VERSION 5.8 ;
BUSBITCHARS "[]" ;
DIVIDERCHAR "/" ;
UNITS
    DATABASE MICRONS 1000 ;
END UNITS

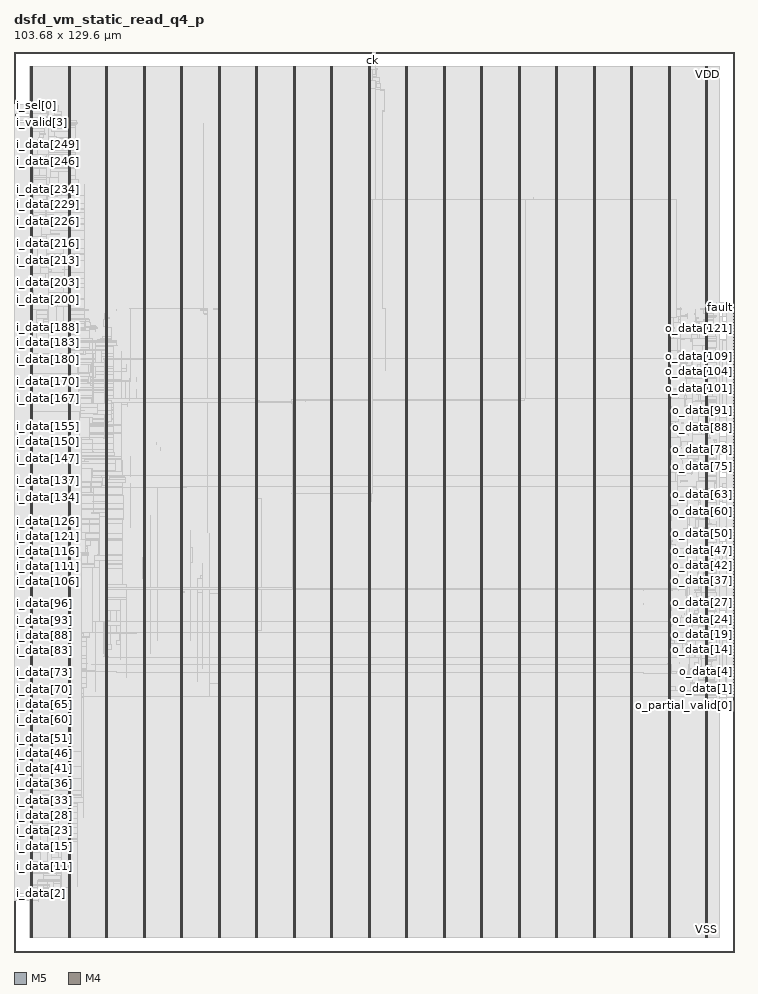
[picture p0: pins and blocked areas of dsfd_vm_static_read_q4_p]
MACRO dsfd_vm_static_read_q4_p
  FOREIGN dsfd_vm_static_read_q4_p 0 0 ;
  CLASS BLOCK ;
  SIZE 103.68 BY 129.6 ;
  PIN ck
    DIRECTION INPUT ;
    USE SIGNAL ;
    PORT
      LAYER M5 ;
        RECT  51.6 129.516 51.624 129.6 ;
    END
  END ck
  PIN fault
    DIRECTION OUTPUT ;
    USE SIGNAL ;
    PORT
      LAYER M4 ;
        RECT  103.596 92.832 103.68 92.856 ;
    END
  END fault
  PIN i_data[0]
    DIRECTION INPUT ;
    USE SIGNAL ;
    PORT
      LAYER M4 ;
        RECT  0 7.536 0.084 7.56 ;
    END
  END i_data[0]
  PIN i_data[100]
    DIRECTION INPUT ;
    USE SIGNAL ;
    PORT
      LAYER M4 ;
        RECT  0 50.736 0.084 50.76 ;
    END
  END i_data[100]
  PIN i_data[101]
    DIRECTION INPUT ;
    USE SIGNAL ;
    PORT
      LAYER M4 ;
        RECT  0 51.168 0.084 51.192 ;
    END
  END i_data[101]
  PIN i_data[102]
    DIRECTION INPUT ;
    USE SIGNAL ;
    PORT
      LAYER M4 ;
        RECT  0 51.6 0.084 51.624 ;
    END
  END i_data[102]
  PIN i_data[103]
    DIRECTION INPUT ;
    USE SIGNAL ;
    PORT
      LAYER M4 ;
        RECT  0 52.032 0.084 52.056 ;
    END
  END i_data[103]
  PIN i_data[104]
    DIRECTION INPUT ;
    USE SIGNAL ;
    PORT
      LAYER M4 ;
        RECT  0 52.464 0.084 52.488 ;
    END
  END i_data[104]
  PIN i_data[105]
    DIRECTION INPUT ;
    USE SIGNAL ;
    PORT
      LAYER M4 ;
        RECT  0 52.896 0.084 52.92 ;
    END
  END i_data[105]
  PIN i_data[106]
    DIRECTION INPUT ;
    USE SIGNAL ;
    PORT
      LAYER M4 ;
        RECT  0 53.328 0.084 53.352 ;
    END
  END i_data[106]
  PIN i_data[107]
    DIRECTION INPUT ;
    USE SIGNAL ;
    PORT
      LAYER M4 ;
        RECT  0 53.76 0.084 53.784 ;
    END
  END i_data[107]
  PIN i_data[108]
    DIRECTION INPUT ;
    USE SIGNAL ;
    PORT
      LAYER M4 ;
        RECT  0 54.192 0.084 54.216 ;
    END
  END i_data[108]
  PIN i_data[109]
    DIRECTION INPUT ;
    USE SIGNAL ;
    PORT
      LAYER M4 ;
        RECT  0 54.624 0.084 54.648 ;
    END
  END i_data[109]
  PIN i_data[10]
    DIRECTION INPUT ;
    USE SIGNAL ;
    PORT
      LAYER M4 ;
        RECT  0 11.856 0.084 11.88 ;
    END
  END i_data[10]
  PIN i_data[110]
    DIRECTION INPUT ;
    USE SIGNAL ;
    PORT
      LAYER M4 ;
        RECT  0 55.056 0.084 55.08 ;
    END
  END i_data[110]
  PIN i_data[111]
    DIRECTION INPUT ;
    USE SIGNAL ;
    PORT
      LAYER M4 ;
        RECT  0 55.488 0.084 55.512 ;
    END
  END i_data[111]
  PIN i_data[112]
    DIRECTION INPUT ;
    USE SIGNAL ;
    PORT
      LAYER M4 ;
        RECT  0 55.92 0.084 55.944 ;
    END
  END i_data[112]
  PIN i_data[113]
    DIRECTION INPUT ;
    USE SIGNAL ;
    PORT
      LAYER M4 ;
        RECT  0 56.352 0.084 56.376 ;
    END
  END i_data[113]
  PIN i_data[114]
    DIRECTION INPUT ;
    USE SIGNAL ;
    PORT
      LAYER M4 ;
        RECT  0 56.784 0.084 56.808 ;
    END
  END i_data[114]
  PIN i_data[115]
    DIRECTION INPUT ;
    USE SIGNAL ;
    PORT
      LAYER M4 ;
        RECT  0 57.216 0.084 57.24 ;
    END
  END i_data[115]
  PIN i_data[116]
    DIRECTION INPUT ;
    USE SIGNAL ;
    PORT
      LAYER M4 ;
        RECT  0 57.648 0.084 57.672 ;
    END
  END i_data[116]
  PIN i_data[117]
    DIRECTION INPUT ;
    USE SIGNAL ;
    PORT
      LAYER M4 ;
        RECT  0 58.08 0.084 58.104 ;
    END
  END i_data[117]
  PIN i_data[118]
    DIRECTION INPUT ;
    USE SIGNAL ;
    PORT
      LAYER M4 ;
        RECT  0 58.512 0.084 58.536 ;
    END
  END i_data[118]
  PIN i_data[119]
    DIRECTION INPUT ;
    USE SIGNAL ;
    PORT
      LAYER M4 ;
        RECT  0 58.944 0.084 58.968 ;
    END
  END i_data[119]
  PIN i_data[11]
    DIRECTION INPUT ;
    USE SIGNAL ;
    PORT
      LAYER M4 ;
        RECT  0 12.288 0.084 12.312 ;
    END
  END i_data[11]
  PIN i_data[120]
    DIRECTION INPUT ;
    USE SIGNAL ;
    PORT
      LAYER M4 ;
        RECT  0 59.376 0.084 59.4 ;
    END
  END i_data[120]
  PIN i_data[121]
    DIRECTION INPUT ;
    USE SIGNAL ;
    PORT
      LAYER M4 ;
        RECT  0 59.808 0.084 59.832 ;
    END
  END i_data[121]
  PIN i_data[122]
    DIRECTION INPUT ;
    USE SIGNAL ;
    PORT
      LAYER M4 ;
        RECT  0 60.24 0.084 60.264 ;
    END
  END i_data[122]
  PIN i_data[123]
    DIRECTION INPUT ;
    USE SIGNAL ;
    PORT
      LAYER M4 ;
        RECT  0 60.672 0.084 60.696 ;
    END
  END i_data[123]
  PIN i_data[124]
    DIRECTION INPUT ;
    USE SIGNAL ;
    PORT
      LAYER M4 ;
        RECT  0 61.104 0.084 61.128 ;
    END
  END i_data[124]
  PIN i_data[125]
    DIRECTION INPUT ;
    USE SIGNAL ;
    PORT
      LAYER M4 ;
        RECT  0 61.536 0.084 61.56 ;
    END
  END i_data[125]
  PIN i_data[126]
    DIRECTION INPUT ;
    USE SIGNAL ;
    PORT
      LAYER M4 ;
        RECT  0 61.968 0.084 61.992 ;
    END
  END i_data[126]
  PIN i_data[127]
    DIRECTION INPUT ;
    USE SIGNAL ;
    PORT
      LAYER M4 ;
        RECT  0 62.4 0.084 62.424 ;
    END
  END i_data[127]
  PIN i_data[128]
    DIRECTION INPUT ;
    USE SIGNAL ;
    PORT
      LAYER M4 ;
        RECT  0 62.832 0.084 62.856 ;
    END
  END i_data[128]
  PIN i_data[129]
    DIRECTION INPUT ;
    USE SIGNAL ;
    PORT
      LAYER M4 ;
        RECT  0 63.264 0.084 63.288 ;
    END
  END i_data[129]
  PIN i_data[12]
    DIRECTION INPUT ;
    USE SIGNAL ;
    PORT
      LAYER M4 ;
        RECT  0 12.72 0.084 12.744 ;
    END
  END i_data[12]
  PIN i_data[130]
    DIRECTION INPUT ;
    USE SIGNAL ;
    PORT
      LAYER M4 ;
        RECT  0 63.696 0.084 63.72 ;
    END
  END i_data[130]
  PIN i_data[131]
    DIRECTION INPUT ;
    USE SIGNAL ;
    PORT
      LAYER M4 ;
        RECT  0 64.128 0.084 64.152 ;
    END
  END i_data[131]
  PIN i_data[132]
    DIRECTION INPUT ;
    USE SIGNAL ;
    PORT
      LAYER M4 ;
        RECT  0 64.56 0.084 64.584 ;
    END
  END i_data[132]
  PIN i_data[133]
    DIRECTION INPUT ;
    USE SIGNAL ;
    PORT
      LAYER M4 ;
        RECT  0 64.992 0.084 65.016 ;
    END
  END i_data[133]
  PIN i_data[134]
    DIRECTION INPUT ;
    USE SIGNAL ;
    PORT
      LAYER M4 ;
        RECT  0 65.424 0.084 65.448 ;
    END
  END i_data[134]
  PIN i_data[135]
    DIRECTION INPUT ;
    USE SIGNAL ;
    PORT
      LAYER M4 ;
        RECT  0 65.856 0.084 65.88 ;
    END
  END i_data[135]
  PIN i_data[136]
    DIRECTION INPUT ;
    USE SIGNAL ;
    PORT
      LAYER M4 ;
        RECT  0 66.288 0.084 66.312 ;
    END
  END i_data[136]
  PIN i_data[137]
    DIRECTION INPUT ;
    USE SIGNAL ;
    PORT
      LAYER M4 ;
        RECT  0 66.72 0.084 66.744 ;
    END
  END i_data[137]
  PIN i_data[138]
    DIRECTION INPUT ;
    USE SIGNAL ;
    PORT
      LAYER M4 ;
        RECT  0 67.152 0.084 67.176 ;
    END
  END i_data[138]
  PIN i_data[139]
    DIRECTION INPUT ;
    USE SIGNAL ;
    PORT
      LAYER M4 ;
        RECT  0 67.584 0.084 67.608 ;
    END
  END i_data[139]
  PIN i_data[13]
    DIRECTION INPUT ;
    USE SIGNAL ;
    PORT
      LAYER M4 ;
        RECT  0 13.152 0.084 13.176 ;
    END
  END i_data[13]
  PIN i_data[140]
    DIRECTION INPUT ;
    USE SIGNAL ;
    PORT
      LAYER M4 ;
        RECT  0 68.016 0.084 68.04 ;
    END
  END i_data[140]
  PIN i_data[141]
    DIRECTION INPUT ;
    USE SIGNAL ;
    PORT
      LAYER M4 ;
        RECT  0 68.448 0.084 68.472 ;
    END
  END i_data[141]
  PIN i_data[142]
    DIRECTION INPUT ;
    USE SIGNAL ;
    PORT
      LAYER M4 ;
        RECT  0 68.88 0.084 68.904 ;
    END
  END i_data[142]
  PIN i_data[143]
    DIRECTION INPUT ;
    USE SIGNAL ;
    PORT
      LAYER M4 ;
        RECT  0 69.312 0.084 69.336 ;
    END
  END i_data[143]
  PIN i_data[144]
    DIRECTION INPUT ;
    USE SIGNAL ;
    PORT
      LAYER M4 ;
        RECT  0 69.744 0.084 69.768 ;
    END
  END i_data[144]
  PIN i_data[145]
    DIRECTION INPUT ;
    USE SIGNAL ;
    PORT
      LAYER M4 ;
        RECT  0 70.176 0.084 70.2 ;
    END
  END i_data[145]
  PIN i_data[146]
    DIRECTION INPUT ;
    USE SIGNAL ;
    PORT
      LAYER M4 ;
        RECT  0 70.608 0.084 70.632 ;
    END
  END i_data[146]
  PIN i_data[147]
    DIRECTION INPUT ;
    USE SIGNAL ;
    PORT
      LAYER M4 ;
        RECT  0 71.04 0.084 71.064 ;
    END
  END i_data[147]
  PIN i_data[148]
    DIRECTION INPUT ;
    USE SIGNAL ;
    PORT
      LAYER M4 ;
        RECT  0 71.472 0.084 71.496 ;
    END
  END i_data[148]
  PIN i_data[149]
    DIRECTION INPUT ;
    USE SIGNAL ;
    PORT
      LAYER M4 ;
        RECT  0 71.904 0.084 71.928 ;
    END
  END i_data[149]
  PIN i_data[14]
    DIRECTION INPUT ;
    USE SIGNAL ;
    PORT
      LAYER M4 ;
        RECT  0 13.584 0.084 13.608 ;
    END
  END i_data[14]
  PIN i_data[150]
    DIRECTION INPUT ;
    USE SIGNAL ;
    PORT
      LAYER M4 ;
        RECT  0 72.336 0.084 72.36 ;
    END
  END i_data[150]
  PIN i_data[151]
    DIRECTION INPUT ;
    USE SIGNAL ;
    PORT
      LAYER M4 ;
        RECT  0 72.768 0.084 72.792 ;
    END
  END i_data[151]
  PIN i_data[152]
    DIRECTION INPUT ;
    USE SIGNAL ;
    PORT
      LAYER M4 ;
        RECT  0 73.2 0.084 73.224 ;
    END
  END i_data[152]
  PIN i_data[153]
    DIRECTION INPUT ;
    USE SIGNAL ;
    PORT
      LAYER M4 ;
        RECT  0 73.632 0.084 73.656 ;
    END
  END i_data[153]
  PIN i_data[154]
    DIRECTION INPUT ;
    USE SIGNAL ;
    PORT
      LAYER M4 ;
        RECT  0 74.064 0.084 74.088 ;
    END
  END i_data[154]
  PIN i_data[155]
    DIRECTION INPUT ;
    USE SIGNAL ;
    PORT
      LAYER M4 ;
        RECT  0 74.496 0.084 74.52 ;
    END
  END i_data[155]
  PIN i_data[156]
    DIRECTION INPUT ;
    USE SIGNAL ;
    PORT
      LAYER M4 ;
        RECT  0 74.928 0.084 74.952 ;
    END
  END i_data[156]
  PIN i_data[157]
    DIRECTION INPUT ;
    USE SIGNAL ;
    PORT
      LAYER M4 ;
        RECT  0 75.36 0.084 75.384 ;
    END
  END i_data[157]
  PIN i_data[158]
    DIRECTION INPUT ;
    USE SIGNAL ;
    PORT
      LAYER M4 ;
        RECT  0 75.792 0.084 75.816 ;
    END
  END i_data[158]
  PIN i_data[159]
    DIRECTION INPUT ;
    USE SIGNAL ;
    PORT
      LAYER M4 ;
        RECT  0 76.224 0.084 76.248 ;
    END
  END i_data[159]
  PIN i_data[15]
    DIRECTION INPUT ;
    USE SIGNAL ;
    PORT
      LAYER M4 ;
        RECT  0 14.016 0.084 14.04 ;
    END
  END i_data[15]
  PIN i_data[160]
    DIRECTION INPUT ;
    USE SIGNAL ;
    PORT
      LAYER M4 ;
        RECT  0 76.656 0.084 76.68 ;
    END
  END i_data[160]
  PIN i_data[161]
    DIRECTION INPUT ;
    USE SIGNAL ;
    PORT
      LAYER M4 ;
        RECT  0 77.088 0.084 77.112 ;
    END
  END i_data[161]
  PIN i_data[162]
    DIRECTION INPUT ;
    USE SIGNAL ;
    PORT
      LAYER M4 ;
        RECT  0 77.52 0.084 77.544 ;
    END
  END i_data[162]
  PIN i_data[163]
    DIRECTION INPUT ;
    USE SIGNAL ;
    PORT
      LAYER M4 ;
        RECT  0 77.952 0.084 77.976 ;
    END
  END i_data[163]
  PIN i_data[164]
    DIRECTION INPUT ;
    USE SIGNAL ;
    PORT
      LAYER M4 ;
        RECT  0 78.384 0.084 78.408 ;
    END
  END i_data[164]
  PIN i_data[165]
    DIRECTION INPUT ;
    USE SIGNAL ;
    PORT
      LAYER M4 ;
        RECT  0 78.816 0.084 78.84 ;
    END
  END i_data[165]
  PIN i_data[166]
    DIRECTION INPUT ;
    USE SIGNAL ;
    PORT
      LAYER M4 ;
        RECT  0 79.248 0.084 79.272 ;
    END
  END i_data[166]
  PIN i_data[167]
    DIRECTION INPUT ;
    USE SIGNAL ;
    PORT
      LAYER M4 ;
        RECT  0 79.68 0.084 79.704 ;
    END
  END i_data[167]
  PIN i_data[168]
    DIRECTION INPUT ;
    USE SIGNAL ;
    PORT
      LAYER M4 ;
        RECT  0 80.112 0.084 80.136 ;
    END
  END i_data[168]
  PIN i_data[169]
    DIRECTION INPUT ;
    USE SIGNAL ;
    PORT
      LAYER M4 ;
        RECT  0 80.544 0.084 80.568 ;
    END
  END i_data[169]
  PIN i_data[16]
    DIRECTION INPUT ;
    USE SIGNAL ;
    PORT
      LAYER M4 ;
        RECT  0 14.448 0.084 14.472 ;
    END
  END i_data[16]
  PIN i_data[170]
    DIRECTION INPUT ;
    USE SIGNAL ;
    PORT
      LAYER M4 ;
        RECT  0 80.976 0.084 81 ;
    END
  END i_data[170]
  PIN i_data[171]
    DIRECTION INPUT ;
    USE SIGNAL ;
    PORT
      LAYER M4 ;
        RECT  0 81.408 0.084 81.432 ;
    END
  END i_data[171]
  PIN i_data[172]
    DIRECTION INPUT ;
    USE SIGNAL ;
    PORT
      LAYER M4 ;
        RECT  0 81.84 0.084 81.864 ;
    END
  END i_data[172]
  PIN i_data[173]
    DIRECTION INPUT ;
    USE SIGNAL ;
    PORT
      LAYER M4 ;
        RECT  0 82.272 0.084 82.296 ;
    END
  END i_data[173]
  PIN i_data[174]
    DIRECTION INPUT ;
    USE SIGNAL ;
    PORT
      LAYER M4 ;
        RECT  0 82.704 0.084 82.728 ;
    END
  END i_data[174]
  PIN i_data[175]
    DIRECTION INPUT ;
    USE SIGNAL ;
    PORT
      LAYER M4 ;
        RECT  0 83.136 0.084 83.16 ;
    END
  END i_data[175]
  PIN i_data[176]
    DIRECTION INPUT ;
    USE SIGNAL ;
    PORT
      LAYER M4 ;
        RECT  0 83.568 0.084 83.592 ;
    END
  END i_data[176]
  PIN i_data[177]
    DIRECTION INPUT ;
    USE SIGNAL ;
    PORT
      LAYER M4 ;
        RECT  0 84 0.084 84.024 ;
    END
  END i_data[177]
  PIN i_data[178]
    DIRECTION INPUT ;
    USE SIGNAL ;
    PORT
      LAYER M4 ;
        RECT  0 84.432 0.084 84.456 ;
    END
  END i_data[178]
  PIN i_data[179]
    DIRECTION INPUT ;
    USE SIGNAL ;
    PORT
      LAYER M4 ;
        RECT  0 84.864 0.084 84.888 ;
    END
  END i_data[179]
  PIN i_data[17]
    DIRECTION INPUT ;
    USE SIGNAL ;
    PORT
      LAYER M4 ;
        RECT  0 14.88 0.084 14.904 ;
    END
  END i_data[17]
  PIN i_data[180]
    DIRECTION INPUT ;
    USE SIGNAL ;
    PORT
      LAYER M4 ;
        RECT  0 85.296 0.084 85.32 ;
    END
  END i_data[180]
  PIN i_data[181]
    DIRECTION INPUT ;
    USE SIGNAL ;
    PORT
      LAYER M4 ;
        RECT  0 85.728 0.084 85.752 ;
    END
  END i_data[181]
  PIN i_data[182]
    DIRECTION INPUT ;
    USE SIGNAL ;
    PORT
      LAYER M4 ;
        RECT  0 86.16 0.084 86.184 ;
    END
  END i_data[182]
  PIN i_data[183]
    DIRECTION INPUT ;
    USE SIGNAL ;
    PORT
      LAYER M4 ;
        RECT  0 86.592 0.084 86.616 ;
    END
  END i_data[183]
  PIN i_data[184]
    DIRECTION INPUT ;
    USE SIGNAL ;
    PORT
      LAYER M4 ;
        RECT  0 87.024 0.084 87.048 ;
    END
  END i_data[184]
  PIN i_data[185]
    DIRECTION INPUT ;
    USE SIGNAL ;
    PORT
      LAYER M4 ;
        RECT  0 87.456 0.084 87.48 ;
    END
  END i_data[185]
  PIN i_data[186]
    DIRECTION INPUT ;
    USE SIGNAL ;
    PORT
      LAYER M4 ;
        RECT  0 87.888 0.084 87.912 ;
    END
  END i_data[186]
  PIN i_data[187]
    DIRECTION INPUT ;
    USE SIGNAL ;
    PORT
      LAYER M4 ;
        RECT  0 88.32 0.084 88.344 ;
    END
  END i_data[187]
  PIN i_data[188]
    DIRECTION INPUT ;
    USE SIGNAL ;
    PORT
      LAYER M4 ;
        RECT  0 88.752 0.084 88.776 ;
    END
  END i_data[188]
  PIN i_data[189]
    DIRECTION INPUT ;
    USE SIGNAL ;
    PORT
      LAYER M4 ;
        RECT  0 89.184 0.084 89.208 ;
    END
  END i_data[189]
  PIN i_data[18]
    DIRECTION INPUT ;
    USE SIGNAL ;
    PORT
      LAYER M4 ;
        RECT  0 15.312 0.084 15.336 ;
    END
  END i_data[18]
  PIN i_data[190]
    DIRECTION INPUT ;
    USE SIGNAL ;
    PORT
      LAYER M4 ;
        RECT  0 89.616 0.084 89.64 ;
    END
  END i_data[190]
  PIN i_data[191]
    DIRECTION INPUT ;
    USE SIGNAL ;
    PORT
      LAYER M4 ;
        RECT  0 90.048 0.084 90.072 ;
    END
  END i_data[191]
  PIN i_data[192]
    DIRECTION INPUT ;
    USE SIGNAL ;
    PORT
      LAYER M4 ;
        RECT  0 90.48 0.084 90.504 ;
    END
  END i_data[192]
  PIN i_data[193]
    DIRECTION INPUT ;
    USE SIGNAL ;
    PORT
      LAYER M4 ;
        RECT  0 90.912 0.084 90.936 ;
    END
  END i_data[193]
  PIN i_data[194]
    DIRECTION INPUT ;
    USE SIGNAL ;
    PORT
      LAYER M4 ;
        RECT  0 91.344 0.084 91.368 ;
    END
  END i_data[194]
  PIN i_data[195]
    DIRECTION INPUT ;
    USE SIGNAL ;
    PORT
      LAYER M4 ;
        RECT  0 91.776 0.084 91.8 ;
    END
  END i_data[195]
  PIN i_data[196]
    DIRECTION INPUT ;
    USE SIGNAL ;
    PORT
      LAYER M4 ;
        RECT  0 92.208 0.084 92.232 ;
    END
  END i_data[196]
  PIN i_data[197]
    DIRECTION INPUT ;
    USE SIGNAL ;
    PORT
      LAYER M4 ;
        RECT  0 92.64 0.084 92.664 ;
    END
  END i_data[197]
  PIN i_data[198]
    DIRECTION INPUT ;
    USE SIGNAL ;
    PORT
      LAYER M4 ;
        RECT  0 93.072 0.084 93.096 ;
    END
  END i_data[198]
  PIN i_data[199]
    DIRECTION INPUT ;
    USE SIGNAL ;
    PORT
      LAYER M4 ;
        RECT  0 93.504 0.084 93.528 ;
    END
  END i_data[199]
  PIN i_data[19]
    DIRECTION INPUT ;
    USE SIGNAL ;
    PORT
      LAYER M4 ;
        RECT  0 15.744 0.084 15.768 ;
    END
  END i_data[19]
  PIN i_data[1]
    DIRECTION INPUT ;
    USE SIGNAL ;
    PORT
      LAYER M4 ;
        RECT  0 7.968 0.084 7.992 ;
    END
  END i_data[1]
  PIN i_data[200]
    DIRECTION INPUT ;
    USE SIGNAL ;
    PORT
      LAYER M4 ;
        RECT  0 93.936 0.084 93.96 ;
    END
  END i_data[200]
  PIN i_data[201]
    DIRECTION INPUT ;
    USE SIGNAL ;
    PORT
      LAYER M4 ;
        RECT  0 94.368 0.084 94.392 ;
    END
  END i_data[201]
  PIN i_data[202]
    DIRECTION INPUT ;
    USE SIGNAL ;
    PORT
      LAYER M4 ;
        RECT  0 94.8 0.084 94.824 ;
    END
  END i_data[202]
  PIN i_data[203]
    DIRECTION INPUT ;
    USE SIGNAL ;
    PORT
      LAYER M4 ;
        RECT  0 95.232 0.084 95.256 ;
    END
  END i_data[203]
  PIN i_data[204]
    DIRECTION INPUT ;
    USE SIGNAL ;
    PORT
      LAYER M4 ;
        RECT  0 95.664 0.084 95.688 ;
    END
  END i_data[204]
  PIN i_data[205]
    DIRECTION INPUT ;
    USE SIGNAL ;
    PORT
      LAYER M4 ;
        RECT  0 96.096 0.084 96.12 ;
    END
  END i_data[205]
  PIN i_data[206]
    DIRECTION INPUT ;
    USE SIGNAL ;
    PORT
      LAYER M4 ;
        RECT  0 96.528 0.084 96.552 ;
    END
  END i_data[206]
  PIN i_data[207]
    DIRECTION INPUT ;
    USE SIGNAL ;
    PORT
      LAYER M4 ;
        RECT  0 96.96 0.084 96.984 ;
    END
  END i_data[207]
  PIN i_data[208]
    DIRECTION INPUT ;
    USE SIGNAL ;
    PORT
      LAYER M4 ;
        RECT  0 97.392 0.084 97.416 ;
    END
  END i_data[208]
  PIN i_data[209]
    DIRECTION INPUT ;
    USE SIGNAL ;
    PORT
      LAYER M4 ;
        RECT  0 97.824 0.084 97.848 ;
    END
  END i_data[209]
  PIN i_data[20]
    DIRECTION INPUT ;
    USE SIGNAL ;
    PORT
      LAYER M4 ;
        RECT  0 16.176 0.084 16.2 ;
    END
  END i_data[20]
  PIN i_data[210]
    DIRECTION INPUT ;
    USE SIGNAL ;
    PORT
      LAYER M4 ;
        RECT  0 98.256 0.084 98.28 ;
    END
  END i_data[210]
  PIN i_data[211]
    DIRECTION INPUT ;
    USE SIGNAL ;
    PORT
      LAYER M4 ;
        RECT  0 98.688 0.084 98.712 ;
    END
  END i_data[211]
  PIN i_data[212]
    DIRECTION INPUT ;
    USE SIGNAL ;
    PORT
      LAYER M4 ;
        RECT  0 99.12 0.084 99.144 ;
    END
  END i_data[212]
  PIN i_data[213]
    DIRECTION INPUT ;
    USE SIGNAL ;
    PORT
      LAYER M4 ;
        RECT  0 99.552 0.084 99.576 ;
    END
  END i_data[213]
  PIN i_data[214]
    DIRECTION INPUT ;
    USE SIGNAL ;
    PORT
      LAYER M4 ;
        RECT  0 99.984 0.084 100.008 ;
    END
  END i_data[214]
  PIN i_data[215]
    DIRECTION INPUT ;
    USE SIGNAL ;
    PORT
      LAYER M4 ;
        RECT  0 100.416 0.084 100.44 ;
    END
  END i_data[215]
  PIN i_data[216]
    DIRECTION INPUT ;
    USE SIGNAL ;
    PORT
      LAYER M4 ;
        RECT  0 100.848 0.084 100.872 ;
    END
  END i_data[216]
  PIN i_data[217]
    DIRECTION INPUT ;
    USE SIGNAL ;
    PORT
      LAYER M4 ;
        RECT  0 101.28 0.084 101.304 ;
    END
  END i_data[217]
  PIN i_data[218]
    DIRECTION INPUT ;
    USE SIGNAL ;
    PORT
      LAYER M4 ;
        RECT  0 101.712 0.084 101.736 ;
    END
  END i_data[218]
  PIN i_data[219]
    DIRECTION INPUT ;
    USE SIGNAL ;
    PORT
      LAYER M4 ;
        RECT  0 102.144 0.084 102.168 ;
    END
  END i_data[219]
  PIN i_data[21]
    DIRECTION INPUT ;
    USE SIGNAL ;
    PORT
      LAYER M4 ;
        RECT  0 16.608 0.084 16.632 ;
    END
  END i_data[21]
  PIN i_data[220]
    DIRECTION INPUT ;
    USE SIGNAL ;
    PORT
      LAYER M4 ;
        RECT  0 102.576 0.084 102.6 ;
    END
  END i_data[220]
  PIN i_data[221]
    DIRECTION INPUT ;
    USE SIGNAL ;
    PORT
      LAYER M4 ;
        RECT  0 103.008 0.084 103.032 ;
    END
  END i_data[221]
  PIN i_data[222]
    DIRECTION INPUT ;
    USE SIGNAL ;
    PORT
      LAYER M4 ;
        RECT  0 103.44 0.084 103.464 ;
    END
  END i_data[222]
  PIN i_data[223]
    DIRECTION INPUT ;
    USE SIGNAL ;
    PORT
      LAYER M4 ;
        RECT  0 103.872 0.084 103.896 ;
    END
  END i_data[223]
  PIN i_data[224]
    DIRECTION INPUT ;
    USE SIGNAL ;
    PORT
      LAYER M4 ;
        RECT  0 104.304 0.084 104.328 ;
    END
  END i_data[224]
  PIN i_data[225]
    DIRECTION INPUT ;
    USE SIGNAL ;
    PORT
      LAYER M4 ;
        RECT  0 104.736 0.084 104.76 ;
    END
  END i_data[225]
  PIN i_data[226]
    DIRECTION INPUT ;
    USE SIGNAL ;
    PORT
      LAYER M4 ;
        RECT  0 105.168 0.084 105.192 ;
    END
  END i_data[226]
  PIN i_data[227]
    DIRECTION INPUT ;
    USE SIGNAL ;
    PORT
      LAYER M4 ;
        RECT  0 105.6 0.084 105.624 ;
    END
  END i_data[227]
  PIN i_data[228]
    DIRECTION INPUT ;
    USE SIGNAL ;
    PORT
      LAYER M4 ;
        RECT  0 106.032 0.084 106.056 ;
    END
  END i_data[228]
  PIN i_data[229]
    DIRECTION INPUT ;
    USE SIGNAL ;
    PORT
      LAYER M4 ;
        RECT  0 106.464 0.084 106.488 ;
    END
  END i_data[229]
  PIN i_data[22]
    DIRECTION INPUT ;
    USE SIGNAL ;
    PORT
      LAYER M4 ;
        RECT  0 17.04 0.084 17.064 ;
    END
  END i_data[22]
  PIN i_data[230]
    DIRECTION INPUT ;
    USE SIGNAL ;
    PORT
      LAYER M4 ;
        RECT  0 106.896 0.084 106.92 ;
    END
  END i_data[230]
  PIN i_data[231]
    DIRECTION INPUT ;
    USE SIGNAL ;
    PORT
      LAYER M4 ;
        RECT  0 107.328 0.084 107.352 ;
    END
  END i_data[231]
  PIN i_data[232]
    DIRECTION INPUT ;
    USE SIGNAL ;
    PORT
      LAYER M4 ;
        RECT  0 107.76 0.084 107.784 ;
    END
  END i_data[232]
  PIN i_data[233]
    DIRECTION INPUT ;
    USE SIGNAL ;
    PORT
      LAYER M4 ;
        RECT  0 108.192 0.084 108.216 ;
    END
  END i_data[233]
  PIN i_data[234]
    DIRECTION INPUT ;
    USE SIGNAL ;
    PORT
      LAYER M4 ;
        RECT  0 108.624 0.084 108.648 ;
    END
  END i_data[234]
  PIN i_data[235]
    DIRECTION INPUT ;
    USE SIGNAL ;
    PORT
      LAYER M4 ;
        RECT  0 109.056 0.084 109.08 ;
    END
  END i_data[235]
  PIN i_data[236]
    DIRECTION INPUT ;
    USE SIGNAL ;
    PORT
      LAYER M4 ;
        RECT  0 109.488 0.084 109.512 ;
    END
  END i_data[236]
  PIN i_data[237]
    DIRECTION INPUT ;
    USE SIGNAL ;
    PORT
      LAYER M4 ;
        RECT  0 109.92 0.084 109.944 ;
    END
  END i_data[237]
  PIN i_data[238]
    DIRECTION INPUT ;
    USE SIGNAL ;
    PORT
      LAYER M4 ;
        RECT  0 110.352 0.084 110.376 ;
    END
  END i_data[238]
  PIN i_data[239]
    DIRECTION INPUT ;
    USE SIGNAL ;
    PORT
      LAYER M4 ;
        RECT  0 110.784 0.084 110.808 ;
    END
  END i_data[239]
  PIN i_data[23]
    DIRECTION INPUT ;
    USE SIGNAL ;
    PORT
      LAYER M4 ;
        RECT  0 17.472 0.084 17.496 ;
    END
  END i_data[23]
  PIN i_data[240]
    DIRECTION INPUT ;
    USE SIGNAL ;
    PORT
      LAYER M4 ;
        RECT  0 111.216 0.084 111.24 ;
    END
  END i_data[240]
  PIN i_data[241]
    DIRECTION INPUT ;
    USE SIGNAL ;
    PORT
      LAYER M4 ;
        RECT  0 111.648 0.084 111.672 ;
    END
  END i_data[241]
  PIN i_data[242]
    DIRECTION INPUT ;
    USE SIGNAL ;
    PORT
      LAYER M4 ;
        RECT  0 112.08 0.084 112.104 ;
    END
  END i_data[242]
  PIN i_data[243]
    DIRECTION INPUT ;
    USE SIGNAL ;
    PORT
      LAYER M4 ;
        RECT  0 112.512 0.084 112.536 ;
    END
  END i_data[243]
  PIN i_data[244]
    DIRECTION INPUT ;
    USE SIGNAL ;
    PORT
      LAYER M4 ;
        RECT  0 112.944 0.084 112.968 ;
    END
  END i_data[244]
  PIN i_data[245]
    DIRECTION INPUT ;
    USE SIGNAL ;
    PORT
      LAYER M4 ;
        RECT  0 113.376 0.084 113.4 ;
    END
  END i_data[245]
  PIN i_data[246]
    DIRECTION INPUT ;
    USE SIGNAL ;
    PORT
      LAYER M4 ;
        RECT  0 113.808 0.084 113.832 ;
    END
  END i_data[246]
  PIN i_data[247]
    DIRECTION INPUT ;
    USE SIGNAL ;
    PORT
      LAYER M4 ;
        RECT  0 114.24 0.084 114.264 ;
    END
  END i_data[247]
  PIN i_data[248]
    DIRECTION INPUT ;
    USE SIGNAL ;
    PORT
      LAYER M4 ;
        RECT  0 114.672 0.084 114.696 ;
    END
  END i_data[248]
  PIN i_data[249]
    DIRECTION INPUT ;
    USE SIGNAL ;
    PORT
      LAYER M4 ;
        RECT  0 115.104 0.084 115.128 ;
    END
  END i_data[249]
  PIN i_data[24]
    DIRECTION INPUT ;
    USE SIGNAL ;
    PORT
      LAYER M4 ;
        RECT  0 17.904 0.084 17.928 ;
    END
  END i_data[24]
  PIN i_data[250]
    DIRECTION INPUT ;
    USE SIGNAL ;
    PORT
      LAYER M4 ;
        RECT  0 115.536 0.084 115.56 ;
    END
  END i_data[250]
  PIN i_data[251]
    DIRECTION INPUT ;
    USE SIGNAL ;
    PORT
      LAYER M4 ;
        RECT  0 115.968 0.084 115.992 ;
    END
  END i_data[251]
  PIN i_data[252]
    DIRECTION INPUT ;
    USE SIGNAL ;
    PORT
      LAYER M4 ;
        RECT  0 116.4 0.084 116.424 ;
    END
  END i_data[252]
  PIN i_data[253]
    DIRECTION INPUT ;
    USE SIGNAL ;
    PORT
      LAYER M4 ;
        RECT  0 116.832 0.084 116.856 ;
    END
  END i_data[253]
  PIN i_data[254]
    DIRECTION INPUT ;
    USE SIGNAL ;
    PORT
      LAYER M4 ;
        RECT  0 117.264 0.084 117.288 ;
    END
  END i_data[254]
  PIN i_data[255]
    DIRECTION INPUT ;
    USE SIGNAL ;
    PORT
      LAYER M4 ;
        RECT  0 117.696 0.084 117.72 ;
    END
  END i_data[255]
  PIN i_data[25]
    DIRECTION INPUT ;
    USE SIGNAL ;
    PORT
      LAYER M4 ;
        RECT  0 18.336 0.084 18.36 ;
    END
  END i_data[25]
  PIN i_data[26]
    DIRECTION INPUT ;
    USE SIGNAL ;
    PORT
      LAYER M4 ;
        RECT  0 18.768 0.084 18.792 ;
    END
  END i_data[26]
  PIN i_data[27]
    DIRECTION INPUT ;
    USE SIGNAL ;
    PORT
      LAYER M4 ;
        RECT  0 19.2 0.084 19.224 ;
    END
  END i_data[27]
  PIN i_data[28]
    DIRECTION INPUT ;
    USE SIGNAL ;
    PORT
      LAYER M4 ;
        RECT  0 19.632 0.084 19.656 ;
    END
  END i_data[28]
  PIN i_data[29]
    DIRECTION INPUT ;
    USE SIGNAL ;
    PORT
      LAYER M4 ;
        RECT  0 20.064 0.084 20.088 ;
    END
  END i_data[29]
  PIN i_data[2]
    DIRECTION INPUT ;
    USE SIGNAL ;
    PORT
      LAYER M4 ;
        RECT  0 8.4 0.084 8.424 ;
    END
  END i_data[2]
  PIN i_data[30]
    DIRECTION INPUT ;
    USE SIGNAL ;
    PORT
      LAYER M4 ;
        RECT  0 20.496 0.084 20.52 ;
    END
  END i_data[30]
  PIN i_data[31]
    DIRECTION INPUT ;
    USE SIGNAL ;
    PORT
      LAYER M4 ;
        RECT  0 20.928 0.084 20.952 ;
    END
  END i_data[31]
  PIN i_data[32]
    DIRECTION INPUT ;
    USE SIGNAL ;
    PORT
      LAYER M4 ;
        RECT  0 21.36 0.084 21.384 ;
    END
  END i_data[32]
  PIN i_data[33]
    DIRECTION INPUT ;
    USE SIGNAL ;
    PORT
      LAYER M4 ;
        RECT  0 21.792 0.084 21.816 ;
    END
  END i_data[33]
  PIN i_data[34]
    DIRECTION INPUT ;
    USE SIGNAL ;
    PORT
      LAYER M4 ;
        RECT  0 22.224 0.084 22.248 ;
    END
  END i_data[34]
  PIN i_data[35]
    DIRECTION INPUT ;
    USE SIGNAL ;
    PORT
      LAYER M4 ;
        RECT  0 22.656 0.084 22.68 ;
    END
  END i_data[35]
  PIN i_data[36]
    DIRECTION INPUT ;
    USE SIGNAL ;
    PORT
      LAYER M4 ;
        RECT  0 23.088 0.084 23.112 ;
    END
  END i_data[36]
  PIN i_data[37]
    DIRECTION INPUT ;
    USE SIGNAL ;
    PORT
      LAYER M4 ;
        RECT  0 23.52 0.084 23.544 ;
    END
  END i_data[37]
  PIN i_data[38]
    DIRECTION INPUT ;
    USE SIGNAL ;
    PORT
      LAYER M4 ;
        RECT  0 23.952 0.084 23.976 ;
    END
  END i_data[38]
  PIN i_data[39]
    DIRECTION INPUT ;
    USE SIGNAL ;
    PORT
      LAYER M4 ;
        RECT  0 24.384 0.084 24.408 ;
    END
  END i_data[39]
  PIN i_data[3]
    DIRECTION INPUT ;
    USE SIGNAL ;
    PORT
      LAYER M4 ;
        RECT  0 8.832 0.084 8.856 ;
    END
  END i_data[3]
  PIN i_data[40]
    DIRECTION INPUT ;
    USE SIGNAL ;
    PORT
      LAYER M4 ;
        RECT  0 24.816 0.084 24.84 ;
    END
  END i_data[40]
  PIN i_data[41]
    DIRECTION INPUT ;
    USE SIGNAL ;
    PORT
      LAYER M4 ;
        RECT  0 25.248 0.084 25.272 ;
    END
  END i_data[41]
  PIN i_data[42]
    DIRECTION INPUT ;
    USE SIGNAL ;
    PORT
      LAYER M4 ;
        RECT  0 25.68 0.084 25.704 ;
    END
  END i_data[42]
  PIN i_data[43]
    DIRECTION INPUT ;
    USE SIGNAL ;
    PORT
      LAYER M4 ;
        RECT  0 26.112 0.084 26.136 ;
    END
  END i_data[43]
  PIN i_data[44]
    DIRECTION INPUT ;
    USE SIGNAL ;
    PORT
      LAYER M4 ;
        RECT  0 26.544 0.084 26.568 ;
    END
  END i_data[44]
  PIN i_data[45]
    DIRECTION INPUT ;
    USE SIGNAL ;
    PORT
      LAYER M4 ;
        RECT  0 26.976 0.084 27 ;
    END
  END i_data[45]
  PIN i_data[46]
    DIRECTION INPUT ;
    USE SIGNAL ;
    PORT
      LAYER M4 ;
        RECT  0 27.408 0.084 27.432 ;
    END
  END i_data[46]
  PIN i_data[47]
    DIRECTION INPUT ;
    USE SIGNAL ;
    PORT
      LAYER M4 ;
        RECT  0 27.84 0.084 27.864 ;
    END
  END i_data[47]
  PIN i_data[48]
    DIRECTION INPUT ;
    USE SIGNAL ;
    PORT
      LAYER M4 ;
        RECT  0 28.272 0.084 28.296 ;
    END
  END i_data[48]
  PIN i_data[49]
    DIRECTION INPUT ;
    USE SIGNAL ;
    PORT
      LAYER M4 ;
        RECT  0 28.704 0.084 28.728 ;
    END
  END i_data[49]
  PIN i_data[4]
    DIRECTION INPUT ;
    USE SIGNAL ;
    PORT
      LAYER M4 ;
        RECT  0 9.264 0.084 9.288 ;
    END
  END i_data[4]
  PIN i_data[50]
    DIRECTION INPUT ;
    USE SIGNAL ;
    PORT
      LAYER M4 ;
        RECT  0 29.136 0.084 29.16 ;
    END
  END i_data[50]
  PIN i_data[51]
    DIRECTION INPUT ;
    USE SIGNAL ;
    PORT
      LAYER M4 ;
        RECT  0 29.568 0.084 29.592 ;
    END
  END i_data[51]
  PIN i_data[52]
    DIRECTION INPUT ;
    USE SIGNAL ;
    PORT
      LAYER M4 ;
        RECT  0 30 0.084 30.024 ;
    END
  END i_data[52]
  PIN i_data[53]
    DIRECTION INPUT ;
    USE SIGNAL ;
    PORT
      LAYER M4 ;
        RECT  0 30.432 0.084 30.456 ;
    END
  END i_data[53]
  PIN i_data[54]
    DIRECTION INPUT ;
    USE SIGNAL ;
    PORT
      LAYER M4 ;
        RECT  0 30.864 0.084 30.888 ;
    END
  END i_data[54]
  PIN i_data[55]
    DIRECTION INPUT ;
    USE SIGNAL ;
    PORT
      LAYER M4 ;
        RECT  0 31.296 0.084 31.32 ;
    END
  END i_data[55]
  PIN i_data[56]
    DIRECTION INPUT ;
    USE SIGNAL ;
    PORT
      LAYER M4 ;
        RECT  0 31.728 0.084 31.752 ;
    END
  END i_data[56]
  PIN i_data[57]
    DIRECTION INPUT ;
    USE SIGNAL ;
    PORT
      LAYER M4 ;
        RECT  0 32.16 0.084 32.184 ;
    END
  END i_data[57]
  PIN i_data[58]
    DIRECTION INPUT ;
    USE SIGNAL ;
    PORT
      LAYER M4 ;
        RECT  0 32.592 0.084 32.616 ;
    END
  END i_data[58]
  PIN i_data[59]
    DIRECTION INPUT ;
    USE SIGNAL ;
    PORT
      LAYER M4 ;
        RECT  0 33.024 0.084 33.048 ;
    END
  END i_data[59]
  PIN i_data[5]
    DIRECTION INPUT ;
    USE SIGNAL ;
    PORT
      LAYER M4 ;
        RECT  0 9.696 0.084 9.72 ;
    END
  END i_data[5]
  PIN i_data[60]
    DIRECTION INPUT ;
    USE SIGNAL ;
    PORT
      LAYER M4 ;
        RECT  0 33.456 0.084 33.48 ;
    END
  END i_data[60]
  PIN i_data[61]
    DIRECTION INPUT ;
    USE SIGNAL ;
    PORT
      LAYER M4 ;
        RECT  0 33.888 0.084 33.912 ;
    END
  END i_data[61]
  PIN i_data[62]
    DIRECTION INPUT ;
    USE SIGNAL ;
    PORT
      LAYER M4 ;
        RECT  0 34.32 0.084 34.344 ;
    END
  END i_data[62]
  PIN i_data[63]
    DIRECTION INPUT ;
    USE SIGNAL ;
    PORT
      LAYER M4 ;
        RECT  0 34.752 0.084 34.776 ;
    END
  END i_data[63]
  PIN i_data[64]
    DIRECTION INPUT ;
    USE SIGNAL ;
    PORT
      LAYER M4 ;
        RECT  0 35.184 0.084 35.208 ;
    END
  END i_data[64]
  PIN i_data[65]
    DIRECTION INPUT ;
    USE SIGNAL ;
    PORT
      LAYER M4 ;
        RECT  0 35.616 0.084 35.64 ;
    END
  END i_data[65]
  PIN i_data[66]
    DIRECTION INPUT ;
    USE SIGNAL ;
    PORT
      LAYER M4 ;
        RECT  0 36.048 0.084 36.072 ;
    END
  END i_data[66]
  PIN i_data[67]
    DIRECTION INPUT ;
    USE SIGNAL ;
    PORT
      LAYER M4 ;
        RECT  0 36.48 0.084 36.504 ;
    END
  END i_data[67]
  PIN i_data[68]
    DIRECTION INPUT ;
    USE SIGNAL ;
    PORT
      LAYER M4 ;
        RECT  0 36.912 0.084 36.936 ;
    END
  END i_data[68]
  PIN i_data[69]
    DIRECTION INPUT ;
    USE SIGNAL ;
    PORT
      LAYER M4 ;
        RECT  0 37.344 0.084 37.368 ;
    END
  END i_data[69]
  PIN i_data[6]
    DIRECTION INPUT ;
    USE SIGNAL ;
    PORT
      LAYER M4 ;
        RECT  0 10.128 0.084 10.152 ;
    END
  END i_data[6]
  PIN i_data[70]
    DIRECTION INPUT ;
    USE SIGNAL ;
    PORT
      LAYER M4 ;
        RECT  0 37.776 0.084 37.8 ;
    END
  END i_data[70]
  PIN i_data[71]
    DIRECTION INPUT ;
    USE SIGNAL ;
    PORT
      LAYER M4 ;
        RECT  0 38.208 0.084 38.232 ;
    END
  END i_data[71]
  PIN i_data[72]
    DIRECTION INPUT ;
    USE SIGNAL ;
    PORT
      LAYER M4 ;
        RECT  0 38.64 0.084 38.664 ;
    END
  END i_data[72]
  PIN i_data[73]
    DIRECTION INPUT ;
    USE SIGNAL ;
    PORT
      LAYER M4 ;
        RECT  0 39.072 0.084 39.096 ;
    END
  END i_data[73]
  PIN i_data[74]
    DIRECTION INPUT ;
    USE SIGNAL ;
    PORT
      LAYER M4 ;
        RECT  0 39.504 0.084 39.528 ;
    END
  END i_data[74]
  PIN i_data[75]
    DIRECTION INPUT ;
    USE SIGNAL ;
    PORT
      LAYER M4 ;
        RECT  0 39.936 0.084 39.96 ;
    END
  END i_data[75]
  PIN i_data[76]
    DIRECTION INPUT ;
    USE SIGNAL ;
    PORT
      LAYER M4 ;
        RECT  0 40.368 0.084 40.392 ;
    END
  END i_data[76]
  PIN i_data[77]
    DIRECTION INPUT ;
    USE SIGNAL ;
    PORT
      LAYER M4 ;
        RECT  0 40.8 0.084 40.824 ;
    END
  END i_data[77]
  PIN i_data[78]
    DIRECTION INPUT ;
    USE SIGNAL ;
    PORT
      LAYER M4 ;
        RECT  0 41.232 0.084 41.256 ;
    END
  END i_data[78]
  PIN i_data[79]
    DIRECTION INPUT ;
    USE SIGNAL ;
    PORT
      LAYER M4 ;
        RECT  0 41.664 0.084 41.688 ;
    END
  END i_data[79]
  PIN i_data[7]
    DIRECTION INPUT ;
    USE SIGNAL ;
    PORT
      LAYER M4 ;
        RECT  0 10.56 0.084 10.584 ;
    END
  END i_data[7]
  PIN i_data[80]
    DIRECTION INPUT ;
    USE SIGNAL ;
    PORT
      LAYER M4 ;
        RECT  0 42.096 0.084 42.12 ;
    END
  END i_data[80]
  PIN i_data[81]
    DIRECTION INPUT ;
    USE SIGNAL ;
    PORT
      LAYER M4 ;
        RECT  0 42.528 0.084 42.552 ;
    END
  END i_data[81]
  PIN i_data[82]
    DIRECTION INPUT ;
    USE SIGNAL ;
    PORT
      LAYER M4 ;
        RECT  0 42.96 0.084 42.984 ;
    END
  END i_data[82]
  PIN i_data[83]
    DIRECTION INPUT ;
    USE SIGNAL ;
    PORT
      LAYER M4 ;
        RECT  0 43.392 0.084 43.416 ;
    END
  END i_data[83]
  PIN i_data[84]
    DIRECTION INPUT ;
    USE SIGNAL ;
    PORT
      LAYER M4 ;
        RECT  0 43.824 0.084 43.848 ;
    END
  END i_data[84]
  PIN i_data[85]
    DIRECTION INPUT ;
    USE SIGNAL ;
    PORT
      LAYER M4 ;
        RECT  0 44.256 0.084 44.28 ;
    END
  END i_data[85]
  PIN i_data[86]
    DIRECTION INPUT ;
    USE SIGNAL ;
    PORT
      LAYER M4 ;
        RECT  0 44.688 0.084 44.712 ;
    END
  END i_data[86]
  PIN i_data[87]
    DIRECTION INPUT ;
    USE SIGNAL ;
    PORT
      LAYER M4 ;
        RECT  0 45.12 0.084 45.144 ;
    END
  END i_data[87]
  PIN i_data[88]
    DIRECTION INPUT ;
    USE SIGNAL ;
    PORT
      LAYER M4 ;
        RECT  0 45.552 0.084 45.576 ;
    END
  END i_data[88]
  PIN i_data[89]
    DIRECTION INPUT ;
    USE SIGNAL ;
    PORT
      LAYER M4 ;
        RECT  0 45.984 0.084 46.008 ;
    END
  END i_data[89]
  PIN i_data[8]
    DIRECTION INPUT ;
    USE SIGNAL ;
    PORT
      LAYER M4 ;
        RECT  0 10.992 0.084 11.016 ;
    END
  END i_data[8]
  PIN i_data[90]
    DIRECTION INPUT ;
    USE SIGNAL ;
    PORT
      LAYER M4 ;
        RECT  0 46.416 0.084 46.44 ;
    END
  END i_data[90]
  PIN i_data[91]
    DIRECTION INPUT ;
    USE SIGNAL ;
    PORT
      LAYER M4 ;
        RECT  0 46.848 0.084 46.872 ;
    END
  END i_data[91]
  PIN i_data[92]
    DIRECTION INPUT ;
    USE SIGNAL ;
    PORT
      LAYER M4 ;
        RECT  0 47.28 0.084 47.304 ;
    END
  END i_data[92]
  PIN i_data[93]
    DIRECTION INPUT ;
    USE SIGNAL ;
    PORT
      LAYER M4 ;
        RECT  0 47.712 0.084 47.736 ;
    END
  END i_data[93]
  PIN i_data[94]
    DIRECTION INPUT ;
    USE SIGNAL ;
    PORT
      LAYER M4 ;
        RECT  0 48.144 0.084 48.168 ;
    END
  END i_data[94]
  PIN i_data[95]
    DIRECTION INPUT ;
    USE SIGNAL ;
    PORT
      LAYER M4 ;
        RECT  0 48.576 0.084 48.6 ;
    END
  END i_data[95]
  PIN i_data[96]
    DIRECTION INPUT ;
    USE SIGNAL ;
    PORT
      LAYER M4 ;
        RECT  0 49.008 0.084 49.032 ;
    END
  END i_data[96]
  PIN i_data[97]
    DIRECTION INPUT ;
    USE SIGNAL ;
    PORT
      LAYER M4 ;
        RECT  0 49.44 0.084 49.464 ;
    END
  END i_data[97]
  PIN i_data[98]
    DIRECTION INPUT ;
    USE SIGNAL ;
    PORT
      LAYER M4 ;
        RECT  0 49.872 0.084 49.896 ;
    END
  END i_data[98]
  PIN i_data[99]
    DIRECTION INPUT ;
    USE SIGNAL ;
    PORT
      LAYER M4 ;
        RECT  0 50.304 0.084 50.328 ;
    END
  END i_data[99]
  PIN i_data[9]
    DIRECTION INPUT ;
    USE SIGNAL ;
    PORT
      LAYER M4 ;
        RECT  0 11.424 0.084 11.448 ;
    END
  END i_data[9]
  PIN i_expected[0]
    DIRECTION INPUT ;
    USE SIGNAL ;
    PORT
      LAYER M4 ;
        RECT  0 119.856 0.084 119.88 ;
    END
  END i_expected[0]
  PIN i_expected[1]
    DIRECTION INPUT ;
    USE SIGNAL ;
    PORT
      LAYER M4 ;
        RECT  0 120.288 0.084 120.312 ;
    END
  END i_expected[1]
  PIN i_sel[0]
    DIRECTION INPUT ;
    USE SIGNAL ;
    PORT
      LAYER M4 ;
        RECT  0 120.72 0.084 120.744 ;
    END
  END i_sel[0]
  PIN i_sel[1]
    DIRECTION INPUT ;
    USE SIGNAL ;
    PORT
      LAYER M4 ;
        RECT  0 121.152 0.084 121.176 ;
    END
  END i_sel[1]
  PIN i_sel[2]
    DIRECTION INPUT ;
    USE SIGNAL ;
    PORT
      LAYER M4 ;
        RECT  0 121.584 0.084 121.608 ;
    END
  END i_sel[2]
  PIN i_sel[3]
    DIRECTION INPUT ;
    USE SIGNAL ;
    PORT
      LAYER M4 ;
        RECT  0 122.016 0.084 122.04 ;
    END
  END i_sel[3]
  PIN i_valid[0]
    DIRECTION INPUT ;
    USE SIGNAL ;
    PORT
      LAYER M4 ;
        RECT  0 118.128 0.084 118.152 ;
    END
  END i_valid[0]
  PIN i_valid[1]
    DIRECTION INPUT ;
    USE SIGNAL ;
    PORT
      LAYER M4 ;
        RECT  0 118.56 0.084 118.584 ;
    END
  END i_valid[1]
  PIN i_valid[2]
    DIRECTION INPUT ;
    USE SIGNAL ;
    PORT
      LAYER M4 ;
        RECT  0 118.992 0.084 119.016 ;
    END
  END i_valid[2]
  PIN i_valid[3]
    DIRECTION INPUT ;
    USE SIGNAL ;
    PORT
      LAYER M4 ;
        RECT  0 119.424 0.084 119.448 ;
    END
  END i_valid[3]
  PIN o_data[0]
    DIRECTION OUTPUT ;
    USE SIGNAL ;
    PORT
      LAYER M4 ;
        RECT  103.596 37.536 103.68 37.56 ;
    END
  END o_data[0]
  PIN o_data[100]
    DIRECTION OUTPUT ;
    USE SIGNAL ;
    PORT
      LAYER M4 ;
        RECT  103.596 80.736 103.68 80.76 ;
    END
  END o_data[100]
  PIN o_data[101]
    DIRECTION OUTPUT ;
    USE SIGNAL ;
    PORT
      LAYER M4 ;
        RECT  103.596 81.168 103.68 81.192 ;
    END
  END o_data[101]
  PIN o_data[102]
    DIRECTION OUTPUT ;
    USE SIGNAL ;
    PORT
      LAYER M4 ;
        RECT  103.596 81.6 103.68 81.624 ;
    END
  END o_data[102]
  PIN o_data[103]
    DIRECTION OUTPUT ;
    USE SIGNAL ;
    PORT
      LAYER M4 ;
        RECT  103.596 82.032 103.68 82.056 ;
    END
  END o_data[103]
  PIN o_data[104]
    DIRECTION OUTPUT ;
    USE SIGNAL ;
    PORT
      LAYER M4 ;
        RECT  103.596 82.464 103.68 82.488 ;
    END
  END o_data[104]
  PIN o_data[105]
    DIRECTION OUTPUT ;
    USE SIGNAL ;
    PORT
      LAYER M4 ;
        RECT  103.596 82.896 103.68 82.92 ;
    END
  END o_data[105]
  PIN o_data[106]
    DIRECTION OUTPUT ;
    USE SIGNAL ;
    PORT
      LAYER M4 ;
        RECT  103.596 83.328 103.68 83.352 ;
    END
  END o_data[106]
  PIN o_data[107]
    DIRECTION OUTPUT ;
    USE SIGNAL ;
    PORT
      LAYER M4 ;
        RECT  103.596 83.76 103.68 83.784 ;
    END
  END o_data[107]
  PIN o_data[108]
    DIRECTION OUTPUT ;
    USE SIGNAL ;
    PORT
      LAYER M4 ;
        RECT  103.596 84.192 103.68 84.216 ;
    END
  END o_data[108]
  PIN o_data[109]
    DIRECTION OUTPUT ;
    USE SIGNAL ;
    PORT
      LAYER M4 ;
        RECT  103.596 84.624 103.68 84.648 ;
    END
  END o_data[109]
  PIN o_data[10]
    DIRECTION OUTPUT ;
    USE SIGNAL ;
    PORT
      LAYER M4 ;
        RECT  103.596 41.856 103.68 41.88 ;
    END
  END o_data[10]
  PIN o_data[110]
    DIRECTION OUTPUT ;
    USE SIGNAL ;
    PORT
      LAYER M4 ;
        RECT  103.596 85.056 103.68 85.08 ;
    END
  END o_data[110]
  PIN o_data[111]
    DIRECTION OUTPUT ;
    USE SIGNAL ;
    PORT
      LAYER M4 ;
        RECT  103.596 85.488 103.68 85.512 ;
    END
  END o_data[111]
  PIN o_data[112]
    DIRECTION OUTPUT ;
    USE SIGNAL ;
    PORT
      LAYER M4 ;
        RECT  103.596 85.92 103.68 85.944 ;
    END
  END o_data[112]
  PIN o_data[113]
    DIRECTION OUTPUT ;
    USE SIGNAL ;
    PORT
      LAYER M4 ;
        RECT  103.596 86.352 103.68 86.376 ;
    END
  END o_data[113]
  PIN o_data[114]
    DIRECTION OUTPUT ;
    USE SIGNAL ;
    PORT
      LAYER M4 ;
        RECT  103.596 86.784 103.68 86.808 ;
    END
  END o_data[114]
  PIN o_data[115]
    DIRECTION OUTPUT ;
    USE SIGNAL ;
    PORT
      LAYER M4 ;
        RECT  103.596 87.216 103.68 87.24 ;
    END
  END o_data[115]
  PIN o_data[116]
    DIRECTION OUTPUT ;
    USE SIGNAL ;
    PORT
      LAYER M4 ;
        RECT  103.596 87.648 103.68 87.672 ;
    END
  END o_data[116]
  PIN o_data[117]
    DIRECTION OUTPUT ;
    USE SIGNAL ;
    PORT
      LAYER M4 ;
        RECT  103.596 88.08 103.68 88.104 ;
    END
  END o_data[117]
  PIN o_data[118]
    DIRECTION OUTPUT ;
    USE SIGNAL ;
    PORT
      LAYER M4 ;
        RECT  103.596 88.512 103.68 88.536 ;
    END
  END o_data[118]
  PIN o_data[119]
    DIRECTION OUTPUT ;
    USE SIGNAL ;
    PORT
      LAYER M4 ;
        RECT  103.596 88.944 103.68 88.968 ;
    END
  END o_data[119]
  PIN o_data[11]
    DIRECTION OUTPUT ;
    USE SIGNAL ;
    PORT
      LAYER M4 ;
        RECT  103.596 42.288 103.68 42.312 ;
    END
  END o_data[11]
  PIN o_data[120]
    DIRECTION OUTPUT ;
    USE SIGNAL ;
    PORT
      LAYER M4 ;
        RECT  103.596 89.376 103.68 89.4 ;
    END
  END o_data[120]
  PIN o_data[121]
    DIRECTION OUTPUT ;
    USE SIGNAL ;
    PORT
      LAYER M4 ;
        RECT  103.596 89.808 103.68 89.832 ;
    END
  END o_data[121]
  PIN o_data[122]
    DIRECTION OUTPUT ;
    USE SIGNAL ;
    PORT
      LAYER M4 ;
        RECT  103.596 90.24 103.68 90.264 ;
    END
  END o_data[122]
  PIN o_data[123]
    DIRECTION OUTPUT ;
    USE SIGNAL ;
    PORT
      LAYER M4 ;
        RECT  103.596 90.672 103.68 90.696 ;
    END
  END o_data[123]
  PIN o_data[124]
    DIRECTION OUTPUT ;
    USE SIGNAL ;
    PORT
      LAYER M4 ;
        RECT  103.596 91.104 103.68 91.128 ;
    END
  END o_data[124]
  PIN o_data[125]
    DIRECTION OUTPUT ;
    USE SIGNAL ;
    PORT
      LAYER M4 ;
        RECT  103.596 91.536 103.68 91.56 ;
    END
  END o_data[125]
  PIN o_data[126]
    DIRECTION OUTPUT ;
    USE SIGNAL ;
    PORT
      LAYER M4 ;
        RECT  103.596 91.968 103.68 91.992 ;
    END
  END o_data[126]
  PIN o_data[127]
    DIRECTION OUTPUT ;
    USE SIGNAL ;
    PORT
      LAYER M4 ;
        RECT  103.596 92.4 103.68 92.424 ;
    END
  END o_data[127]
  PIN o_data[12]
    DIRECTION OUTPUT ;
    USE SIGNAL ;
    PORT
      LAYER M4 ;
        RECT  103.596 42.72 103.68 42.744 ;
    END
  END o_data[12]
  PIN o_data[13]
    DIRECTION OUTPUT ;
    USE SIGNAL ;
    PORT
      LAYER M4 ;
        RECT  103.596 43.152 103.68 43.176 ;
    END
  END o_data[13]
  PIN o_data[14]
    DIRECTION OUTPUT ;
    USE SIGNAL ;
    PORT
      LAYER M4 ;
        RECT  103.596 43.584 103.68 43.608 ;
    END
  END o_data[14]
  PIN o_data[15]
    DIRECTION OUTPUT ;
    USE SIGNAL ;
    PORT
      LAYER M4 ;
        RECT  103.596 44.016 103.68 44.04 ;
    END
  END o_data[15]
  PIN o_data[16]
    DIRECTION OUTPUT ;
    USE SIGNAL ;
    PORT
      LAYER M4 ;
        RECT  103.596 44.448 103.68 44.472 ;
    END
  END o_data[16]
  PIN o_data[17]
    DIRECTION OUTPUT ;
    USE SIGNAL ;
    PORT
      LAYER M4 ;
        RECT  103.596 44.88 103.68 44.904 ;
    END
  END o_data[17]
  PIN o_data[18]
    DIRECTION OUTPUT ;
    USE SIGNAL ;
    PORT
      LAYER M4 ;
        RECT  103.596 45.312 103.68 45.336 ;
    END
  END o_data[18]
  PIN o_data[19]
    DIRECTION OUTPUT ;
    USE SIGNAL ;
    PORT
      LAYER M4 ;
        RECT  103.596 45.744 103.68 45.768 ;
    END
  END o_data[19]
  PIN o_data[1]
    DIRECTION OUTPUT ;
    USE SIGNAL ;
    PORT
      LAYER M4 ;
        RECT  103.596 37.968 103.68 37.992 ;
    END
  END o_data[1]
  PIN o_data[20]
    DIRECTION OUTPUT ;
    USE SIGNAL ;
    PORT
      LAYER M4 ;
        RECT  103.596 46.176 103.68 46.2 ;
    END
  END o_data[20]
  PIN o_data[21]
    DIRECTION OUTPUT ;
    USE SIGNAL ;
    PORT
      LAYER M4 ;
        RECT  103.596 46.608 103.68 46.632 ;
    END
  END o_data[21]
  PIN o_data[22]
    DIRECTION OUTPUT ;
    USE SIGNAL ;
    PORT
      LAYER M4 ;
        RECT  103.596 47.04 103.68 47.064 ;
    END
  END o_data[22]
  PIN o_data[23]
    DIRECTION OUTPUT ;
    USE SIGNAL ;
    PORT
      LAYER M4 ;
        RECT  103.596 47.472 103.68 47.496 ;
    END
  END o_data[23]
  PIN o_data[24]
    DIRECTION OUTPUT ;
    USE SIGNAL ;
    PORT
      LAYER M4 ;
        RECT  103.596 47.904 103.68 47.928 ;
    END
  END o_data[24]
  PIN o_data[25]
    DIRECTION OUTPUT ;
    USE SIGNAL ;
    PORT
      LAYER M4 ;
        RECT  103.596 48.336 103.68 48.36 ;
    END
  END o_data[25]
  PIN o_data[26]
    DIRECTION OUTPUT ;
    USE SIGNAL ;
    PORT
      LAYER M4 ;
        RECT  103.596 48.768 103.68 48.792 ;
    END
  END o_data[26]
  PIN o_data[27]
    DIRECTION OUTPUT ;
    USE SIGNAL ;
    PORT
      LAYER M4 ;
        RECT  103.596 49.2 103.68 49.224 ;
    END
  END o_data[27]
  PIN o_data[28]
    DIRECTION OUTPUT ;
    USE SIGNAL ;
    PORT
      LAYER M4 ;
        RECT  103.596 49.632 103.68 49.656 ;
    END
  END o_data[28]
  PIN o_data[29]
    DIRECTION OUTPUT ;
    USE SIGNAL ;
    PORT
      LAYER M4 ;
        RECT  103.596 50.064 103.68 50.088 ;
    END
  END o_data[29]
  PIN o_data[2]
    DIRECTION OUTPUT ;
    USE SIGNAL ;
    PORT
      LAYER M4 ;
        RECT  103.596 38.4 103.68 38.424 ;
    END
  END o_data[2]
  PIN o_data[30]
    DIRECTION OUTPUT ;
    USE SIGNAL ;
    PORT
      LAYER M4 ;
        RECT  103.596 50.496 103.68 50.52 ;
    END
  END o_data[30]
  PIN o_data[31]
    DIRECTION OUTPUT ;
    USE SIGNAL ;
    PORT
      LAYER M4 ;
        RECT  103.596 50.928 103.68 50.952 ;
    END
  END o_data[31]
  PIN o_data[32]
    DIRECTION OUTPUT ;
    USE SIGNAL ;
    PORT
      LAYER M4 ;
        RECT  103.596 51.36 103.68 51.384 ;
    END
  END o_data[32]
  PIN o_data[33]
    DIRECTION OUTPUT ;
    USE SIGNAL ;
    PORT
      LAYER M4 ;
        RECT  103.596 51.792 103.68 51.816 ;
    END
  END o_data[33]
  PIN o_data[34]
    DIRECTION OUTPUT ;
    USE SIGNAL ;
    PORT
      LAYER M4 ;
        RECT  103.596 52.224 103.68 52.248 ;
    END
  END o_data[34]
  PIN o_data[35]
    DIRECTION OUTPUT ;
    USE SIGNAL ;
    PORT
      LAYER M4 ;
        RECT  103.596 52.656 103.68 52.68 ;
    END
  END o_data[35]
  PIN o_data[36]
    DIRECTION OUTPUT ;
    USE SIGNAL ;
    PORT
      LAYER M4 ;
        RECT  103.596 53.088 103.68 53.112 ;
    END
  END o_data[36]
  PIN o_data[37]
    DIRECTION OUTPUT ;
    USE SIGNAL ;
    PORT
      LAYER M4 ;
        RECT  103.596 53.52 103.68 53.544 ;
    END
  END o_data[37]
  PIN o_data[38]
    DIRECTION OUTPUT ;
    USE SIGNAL ;
    PORT
      LAYER M4 ;
        RECT  103.596 53.952 103.68 53.976 ;
    END
  END o_data[38]
  PIN o_data[39]
    DIRECTION OUTPUT ;
    USE SIGNAL ;
    PORT
      LAYER M4 ;
        RECT  103.596 54.384 103.68 54.408 ;
    END
  END o_data[39]
  PIN o_data[3]
    DIRECTION OUTPUT ;
    USE SIGNAL ;
    PORT
      LAYER M4 ;
        RECT  103.596 38.832 103.68 38.856 ;
    END
  END o_data[3]
  PIN o_data[40]
    DIRECTION OUTPUT ;
    USE SIGNAL ;
    PORT
      LAYER M4 ;
        RECT  103.596 54.816 103.68 54.84 ;
    END
  END o_data[40]
  PIN o_data[41]
    DIRECTION OUTPUT ;
    USE SIGNAL ;
    PORT
      LAYER M4 ;
        RECT  103.596 55.248 103.68 55.272 ;
    END
  END o_data[41]
  PIN o_data[42]
    DIRECTION OUTPUT ;
    USE SIGNAL ;
    PORT
      LAYER M4 ;
        RECT  103.596 55.68 103.68 55.704 ;
    END
  END o_data[42]
  PIN o_data[43]
    DIRECTION OUTPUT ;
    USE SIGNAL ;
    PORT
      LAYER M4 ;
        RECT  103.596 56.112 103.68 56.136 ;
    END
  END o_data[43]
  PIN o_data[44]
    DIRECTION OUTPUT ;
    USE SIGNAL ;
    PORT
      LAYER M4 ;
        RECT  103.596 56.544 103.68 56.568 ;
    END
  END o_data[44]
  PIN o_data[45]
    DIRECTION OUTPUT ;
    USE SIGNAL ;
    PORT
      LAYER M4 ;
        RECT  103.596 56.976 103.68 57 ;
    END
  END o_data[45]
  PIN o_data[46]
    DIRECTION OUTPUT ;
    USE SIGNAL ;
    PORT
      LAYER M4 ;
        RECT  103.596 57.408 103.68 57.432 ;
    END
  END o_data[46]
  PIN o_data[47]
    DIRECTION OUTPUT ;
    USE SIGNAL ;
    PORT
      LAYER M4 ;
        RECT  103.596 57.84 103.68 57.864 ;
    END
  END o_data[47]
  PIN o_data[48]
    DIRECTION OUTPUT ;
    USE SIGNAL ;
    PORT
      LAYER M4 ;
        RECT  103.596 58.272 103.68 58.296 ;
    END
  END o_data[48]
  PIN o_data[49]
    DIRECTION OUTPUT ;
    USE SIGNAL ;
    PORT
      LAYER M4 ;
        RECT  103.596 58.704 103.68 58.728 ;
    END
  END o_data[49]
  PIN o_data[4]
    DIRECTION OUTPUT ;
    USE SIGNAL ;
    PORT
      LAYER M4 ;
        RECT  103.596 39.264 103.68 39.288 ;
    END
  END o_data[4]
  PIN o_data[50]
    DIRECTION OUTPUT ;
    USE SIGNAL ;
    PORT
      LAYER M4 ;
        RECT  103.596 59.136 103.68 59.16 ;
    END
  END o_data[50]
  PIN o_data[51]
    DIRECTION OUTPUT ;
    USE SIGNAL ;
    PORT
      LAYER M4 ;
        RECT  103.596 59.568 103.68 59.592 ;
    END
  END o_data[51]
  PIN o_data[52]
    DIRECTION OUTPUT ;
    USE SIGNAL ;
    PORT
      LAYER M4 ;
        RECT  103.596 60 103.68 60.024 ;
    END
  END o_data[52]
  PIN o_data[53]
    DIRECTION OUTPUT ;
    USE SIGNAL ;
    PORT
      LAYER M4 ;
        RECT  103.596 60.432 103.68 60.456 ;
    END
  END o_data[53]
  PIN o_data[54]
    DIRECTION OUTPUT ;
    USE SIGNAL ;
    PORT
      LAYER M4 ;
        RECT  103.596 60.864 103.68 60.888 ;
    END
  END o_data[54]
  PIN o_data[55]
    DIRECTION OUTPUT ;
    USE SIGNAL ;
    PORT
      LAYER M4 ;
        RECT  103.596 61.296 103.68 61.32 ;
    END
  END o_data[55]
  PIN o_data[56]
    DIRECTION OUTPUT ;
    USE SIGNAL ;
    PORT
      LAYER M4 ;
        RECT  103.596 61.728 103.68 61.752 ;
    END
  END o_data[56]
  PIN o_data[57]
    DIRECTION OUTPUT ;
    USE SIGNAL ;
    PORT
      LAYER M4 ;
        RECT  103.596 62.16 103.68 62.184 ;
    END
  END o_data[57]
  PIN o_data[58]
    DIRECTION OUTPUT ;
    USE SIGNAL ;
    PORT
      LAYER M4 ;
        RECT  103.596 62.592 103.68 62.616 ;
    END
  END o_data[58]
  PIN o_data[59]
    DIRECTION OUTPUT ;
    USE SIGNAL ;
    PORT
      LAYER M4 ;
        RECT  103.596 63.024 103.68 63.048 ;
    END
  END o_data[59]
  PIN o_data[5]
    DIRECTION OUTPUT ;
    USE SIGNAL ;
    PORT
      LAYER M4 ;
        RECT  103.596 39.696 103.68 39.72 ;
    END
  END o_data[5]
  PIN o_data[60]
    DIRECTION OUTPUT ;
    USE SIGNAL ;
    PORT
      LAYER M4 ;
        RECT  103.596 63.456 103.68 63.48 ;
    END
  END o_data[60]
  PIN o_data[61]
    DIRECTION OUTPUT ;
    USE SIGNAL ;
    PORT
      LAYER M4 ;
        RECT  103.596 63.888 103.68 63.912 ;
    END
  END o_data[61]
  PIN o_data[62]
    DIRECTION OUTPUT ;
    USE SIGNAL ;
    PORT
      LAYER M4 ;
        RECT  103.596 64.32 103.68 64.344 ;
    END
  END o_data[62]
  PIN o_data[63]
    DIRECTION OUTPUT ;
    USE SIGNAL ;
    PORT
      LAYER M4 ;
        RECT  103.596 64.752 103.68 64.776 ;
    END
  END o_data[63]
  PIN o_data[64]
    DIRECTION OUTPUT ;
    USE SIGNAL ;
    PORT
      LAYER M4 ;
        RECT  103.596 65.184 103.68 65.208 ;
    END
  END o_data[64]
  PIN o_data[65]
    DIRECTION OUTPUT ;
    USE SIGNAL ;
    PORT
      LAYER M4 ;
        RECT  103.596 65.616 103.68 65.64 ;
    END
  END o_data[65]
  PIN o_data[66]
    DIRECTION OUTPUT ;
    USE SIGNAL ;
    PORT
      LAYER M4 ;
        RECT  103.596 66.048 103.68 66.072 ;
    END
  END o_data[66]
  PIN o_data[67]
    DIRECTION OUTPUT ;
    USE SIGNAL ;
    PORT
      LAYER M4 ;
        RECT  103.596 66.48 103.68 66.504 ;
    END
  END o_data[67]
  PIN o_data[68]
    DIRECTION OUTPUT ;
    USE SIGNAL ;
    PORT
      LAYER M4 ;
        RECT  103.596 66.912 103.68 66.936 ;
    END
  END o_data[68]
  PIN o_data[69]
    DIRECTION OUTPUT ;
    USE SIGNAL ;
    PORT
      LAYER M4 ;
        RECT  103.596 67.344 103.68 67.368 ;
    END
  END o_data[69]
  PIN o_data[6]
    DIRECTION OUTPUT ;
    USE SIGNAL ;
    PORT
      LAYER M4 ;
        RECT  103.596 40.128 103.68 40.152 ;
    END
  END o_data[6]
  PIN o_data[70]
    DIRECTION OUTPUT ;
    USE SIGNAL ;
    PORT
      LAYER M4 ;
        RECT  103.596 67.776 103.68 67.8 ;
    END
  END o_data[70]
  PIN o_data[71]
    DIRECTION OUTPUT ;
    USE SIGNAL ;
    PORT
      LAYER M4 ;
        RECT  103.596 68.208 103.68 68.232 ;
    END
  END o_data[71]
  PIN o_data[72]
    DIRECTION OUTPUT ;
    USE SIGNAL ;
    PORT
      LAYER M4 ;
        RECT  103.596 68.64 103.68 68.664 ;
    END
  END o_data[72]
  PIN o_data[73]
    DIRECTION OUTPUT ;
    USE SIGNAL ;
    PORT
      LAYER M4 ;
        RECT  103.596 69.072 103.68 69.096 ;
    END
  END o_data[73]
  PIN o_data[74]
    DIRECTION OUTPUT ;
    USE SIGNAL ;
    PORT
      LAYER M4 ;
        RECT  103.596 69.504 103.68 69.528 ;
    END
  END o_data[74]
  PIN o_data[75]
    DIRECTION OUTPUT ;
    USE SIGNAL ;
    PORT
      LAYER M4 ;
        RECT  103.596 69.936 103.68 69.96 ;
    END
  END o_data[75]
  PIN o_data[76]
    DIRECTION OUTPUT ;
    USE SIGNAL ;
    PORT
      LAYER M4 ;
        RECT  103.596 70.368 103.68 70.392 ;
    END
  END o_data[76]
  PIN o_data[77]
    DIRECTION OUTPUT ;
    USE SIGNAL ;
    PORT
      LAYER M4 ;
        RECT  103.596 70.8 103.68 70.824 ;
    END
  END o_data[77]
  PIN o_data[78]
    DIRECTION OUTPUT ;
    USE SIGNAL ;
    PORT
      LAYER M4 ;
        RECT  103.596 71.232 103.68 71.256 ;
    END
  END o_data[78]
  PIN o_data[79]
    DIRECTION OUTPUT ;
    USE SIGNAL ;
    PORT
      LAYER M4 ;
        RECT  103.596 71.664 103.68 71.688 ;
    END
  END o_data[79]
  PIN o_data[7]
    DIRECTION OUTPUT ;
    USE SIGNAL ;
    PORT
      LAYER M4 ;
        RECT  103.596 40.56 103.68 40.584 ;
    END
  END o_data[7]
  PIN o_data[80]
    DIRECTION OUTPUT ;
    USE SIGNAL ;
    PORT
      LAYER M4 ;
        RECT  103.596 72.096 103.68 72.12 ;
    END
  END o_data[80]
  PIN o_data[81]
    DIRECTION OUTPUT ;
    USE SIGNAL ;
    PORT
      LAYER M4 ;
        RECT  103.596 72.528 103.68 72.552 ;
    END
  END o_data[81]
  PIN o_data[82]
    DIRECTION OUTPUT ;
    USE SIGNAL ;
    PORT
      LAYER M4 ;
        RECT  103.596 72.96 103.68 72.984 ;
    END
  END o_data[82]
  PIN o_data[83]
    DIRECTION OUTPUT ;
    USE SIGNAL ;
    PORT
      LAYER M4 ;
        RECT  103.596 73.392 103.68 73.416 ;
    END
  END o_data[83]
  PIN o_data[84]
    DIRECTION OUTPUT ;
    USE SIGNAL ;
    PORT
      LAYER M4 ;
        RECT  103.596 73.824 103.68 73.848 ;
    END
  END o_data[84]
  PIN o_data[85]
    DIRECTION OUTPUT ;
    USE SIGNAL ;
    PORT
      LAYER M4 ;
        RECT  103.596 74.256 103.68 74.28 ;
    END
  END o_data[85]
  PIN o_data[86]
    DIRECTION OUTPUT ;
    USE SIGNAL ;
    PORT
      LAYER M4 ;
        RECT  103.596 74.688 103.68 74.712 ;
    END
  END o_data[86]
  PIN o_data[87]
    DIRECTION OUTPUT ;
    USE SIGNAL ;
    PORT
      LAYER M4 ;
        RECT  103.596 75.12 103.68 75.144 ;
    END
  END o_data[87]
  PIN o_data[88]
    DIRECTION OUTPUT ;
    USE SIGNAL ;
    PORT
      LAYER M4 ;
        RECT  103.596 75.552 103.68 75.576 ;
    END
  END o_data[88]
  PIN o_data[89]
    DIRECTION OUTPUT ;
    USE SIGNAL ;
    PORT
      LAYER M4 ;
        RECT  103.596 75.984 103.68 76.008 ;
    END
  END o_data[89]
  PIN o_data[8]
    DIRECTION OUTPUT ;
    USE SIGNAL ;
    PORT
      LAYER M4 ;
        RECT  103.596 40.992 103.68 41.016 ;
    END
  END o_data[8]
  PIN o_data[90]
    DIRECTION OUTPUT ;
    USE SIGNAL ;
    PORT
      LAYER M4 ;
        RECT  103.596 76.416 103.68 76.44 ;
    END
  END o_data[90]
  PIN o_data[91]
    DIRECTION OUTPUT ;
    USE SIGNAL ;
    PORT
      LAYER M4 ;
        RECT  103.596 76.848 103.68 76.872 ;
    END
  END o_data[91]
  PIN o_data[92]
    DIRECTION OUTPUT ;
    USE SIGNAL ;
    PORT
      LAYER M4 ;
        RECT  103.596 77.28 103.68 77.304 ;
    END
  END o_data[92]
  PIN o_data[93]
    DIRECTION OUTPUT ;
    USE SIGNAL ;
    PORT
      LAYER M4 ;
        RECT  103.596 77.712 103.68 77.736 ;
    END
  END o_data[93]
  PIN o_data[94]
    DIRECTION OUTPUT ;
    USE SIGNAL ;
    PORT
      LAYER M4 ;
        RECT  103.596 78.144 103.68 78.168 ;
    END
  END o_data[94]
  PIN o_data[95]
    DIRECTION OUTPUT ;
    USE SIGNAL ;
    PORT
      LAYER M4 ;
        RECT  103.596 78.576 103.68 78.6 ;
    END
  END o_data[95]
  PIN o_data[96]
    DIRECTION OUTPUT ;
    USE SIGNAL ;
    PORT
      LAYER M4 ;
        RECT  103.596 79.008 103.68 79.032 ;
    END
  END o_data[96]
  PIN o_data[97]
    DIRECTION OUTPUT ;
    USE SIGNAL ;
    PORT
      LAYER M4 ;
        RECT  103.596 79.44 103.68 79.464 ;
    END
  END o_data[97]
  PIN o_data[98]
    DIRECTION OUTPUT ;
    USE SIGNAL ;
    PORT
      LAYER M4 ;
        RECT  103.596 79.872 103.68 79.896 ;
    END
  END o_data[98]
  PIN o_data[99]
    DIRECTION OUTPUT ;
    USE SIGNAL ;
    PORT
      LAYER M4 ;
        RECT  103.596 80.304 103.68 80.328 ;
    END
  END o_data[99]
  PIN o_data[9]
    DIRECTION OUTPUT ;
    USE SIGNAL ;
    PORT
      LAYER M4 ;
        RECT  103.596 41.424 103.68 41.448 ;
    END
  END o_data[9]
  PIN o_partial_valid[0]
    DIRECTION OUTPUT ;
    USE SIGNAL ;
    PORT
      LAYER M4 ;
        RECT  103.596 36.672 103.68 36.696 ;
    END
  END o_partial_valid[0]
  PIN o_partial_valid[1]
    DIRECTION OUTPUT ;
    USE SIGNAL ;
    PORT
      LAYER M4 ;
        RECT  103.596 37.104 103.68 37.128 ;
    END
  END o_partial_valid[1]
  PIN rst_n
    DIRECTION INPUT ;
    USE SIGNAL ;
    PORT
      LAYER M5 ;
        RECT  52.032 129.516 52.056 129.6 ;
    END
  END rst_n
  PIN VDD
    DIRECTION INOUT ;
    USE POWER ;
    PORT
      LAYER M5 ;
        RECT  99.792 2.151 99.912 127.449 ;
        RECT  94.392 2.151 94.512 127.449 ;
        RECT  88.992 2.151 89.112 127.449 ;
        RECT  83.592 2.151 83.712 127.449 ;
        RECT  78.192 2.151 78.312 127.449 ;
        RECT  72.792 2.151 72.912 127.449 ;
        RECT  67.392 2.151 67.512 127.449 ;
        RECT  61.992 2.151 62.112 127.449 ;
        RECT  56.592 2.151 56.712 127.449 ;
        RECT  51.192 2.151 51.312 127.449 ;
        RECT  45.792 2.151 45.912 127.449 ;
        RECT  40.392 2.151 40.512 127.449 ;
        RECT  34.992 2.151 35.112 127.449 ;
        RECT  29.592 2.151 29.712 127.449 ;
        RECT  24.192 2.151 24.312 127.449 ;
        RECT  18.792 2.151 18.912 127.449 ;
        RECT  13.392 2.151 13.512 127.449 ;
        RECT  7.992 2.151 8.112 127.449 ;
        RECT  2.592 2.151 2.712 127.449 ;
    END
  END VDD
  PIN VSS
    DIRECTION INOUT ;
    USE GROUND ;
    PORT
      LAYER M5 ;
        RECT  99.6 2.137 99.72 127.463 ;
        RECT  94.2 2.137 94.32 127.463 ;
        RECT  88.8 2.137 88.92 127.463 ;
        RECT  83.4 2.137 83.52 127.463 ;
        RECT  78 2.137 78.12 127.463 ;
        RECT  72.6 2.137 72.72 127.463 ;
        RECT  67.2 2.137 67.32 127.463 ;
        RECT  61.8 2.137 61.92 127.463 ;
        RECT  56.4 2.137 56.52 127.463 ;
        RECT  51 2.137 51.12 127.463 ;
        RECT  45.6 2.137 45.72 127.463 ;
        RECT  40.2 2.137 40.32 127.463 ;
        RECT  34.8 2.137 34.92 127.463 ;
        RECT  29.4 2.137 29.52 127.463 ;
        RECT  24 2.137 24.12 127.463 ;
        RECT  18.6 2.137 18.72 127.463 ;
        RECT  13.2 2.137 13.32 127.463 ;
        RECT  7.8 2.137 7.92 127.463 ;
        RECT  2.4 2.137 2.52 127.463 ;
    END
  END VSS
  # OT_OBS_CLOSED layer=M5 d_um=1.536 added=75
  OBS
    LAYER RVTN ;
     RECT  2.16 2.16 101.52 2.295 ;
     RECT  2.16 2.565 101.52 2.835 ;
     RECT  2.16 3.105 101.52 3.375 ;
     RECT  2.16 3.645 101.52 3.915 ;
     RECT  2.16 4.185 101.52 4.455 ;
     RECT  2.16 4.725 101.52 4.995 ;
     RECT  2.16 5.265 101.52 5.535 ;
     RECT  2.16 5.805 101.52 6.075 ;
     RECT  2.16 6.345 101.52 6.615 ;
     RECT  2.16 6.885 101.52 7.155 ;
     RECT  2.16 7.425 101.52 7.695 ;
     RECT  2.16 7.965 101.52 8.235 ;
     RECT  2.16 8.505 101.52 8.775 ;
     RECT  2.16 9.045 101.52 9.315 ;
     RECT  2.16 9.585 101.52 9.855 ;
     RECT  2.16 10.125 101.52 10.395 ;
     RECT  2.16 10.665 101.52 10.935 ;
     RECT  2.16 11.205 101.52 11.475 ;
     RECT  2.16 11.745 101.52 12.015 ;
     RECT  2.16 12.285 101.52 12.555 ;
     RECT  2.16 12.825 101.52 13.095 ;
     RECT  2.16 13.365 101.52 13.635 ;
     RECT  2.16 13.905 101.52 14.175 ;
     RECT  2.16 14.445 101.52 14.715 ;
     RECT  2.16 14.985 101.52 15.255 ;
     RECT  2.16 15.525 101.52 15.795 ;
     RECT  2.16 16.065 101.52 16.335 ;
     RECT  2.16 16.605 101.52 16.875 ;
     RECT  2.16 17.145 101.52 17.415 ;
     RECT  2.16 17.685 101.52 17.955 ;
     RECT  2.16 18.225 101.52 18.495 ;
     RECT  2.16 18.765 101.52 19.035 ;
     RECT  2.16 19.305 101.52 19.575 ;
     RECT  2.16 19.845 101.52 20.115 ;
     RECT  2.16 20.385 101.52 20.655 ;
     RECT  2.16 20.925 101.52 21.195 ;
     RECT  2.16 21.465 101.52 21.735 ;
     RECT  2.16 22.005 101.52 22.275 ;
     RECT  2.16 22.545 101.52 22.815 ;
     RECT  2.16 23.085 101.52 23.355 ;
     RECT  2.16 23.625 101.52 23.895 ;
     RECT  2.16 24.165 101.52 24.435 ;
     RECT  2.16 24.705 101.52 24.975 ;
     RECT  2.16 25.245 101.52 25.515 ;
     RECT  2.16 25.785 101.52 26.055 ;
     RECT  2.16 26.325 101.52 26.595 ;
     RECT  2.16 26.865 101.52 27.135 ;
     RECT  2.16 27.405 101.52 27.675 ;
     RECT  2.16 27.945 101.52 28.215 ;
     RECT  2.16 28.485 101.52 28.755 ;
     RECT  2.16 29.025 101.52 29.295 ;
     RECT  2.16 29.565 101.52 29.835 ;
     RECT  2.16 30.105 101.52 30.375 ;
     RECT  2.16 30.645 101.52 30.915 ;
     RECT  2.16 31.185 101.52 31.455 ;
     RECT  2.16 31.725 101.52 31.995 ;
     RECT  2.16 32.265 101.52 32.535 ;
     RECT  2.16 32.805 101.52 33.075 ;
     RECT  2.16 33.345 101.52 33.615 ;
     RECT  2.16 33.885 101.52 34.155 ;
     RECT  2.16 34.425 101.52 34.695 ;
     RECT  2.16 34.965 101.52 35.235 ;
     RECT  2.16 35.505 101.52 35.775 ;
     RECT  2.16 36.045 101.52 36.315 ;
     RECT  2.16 36.585 101.52 36.855 ;
     RECT  2.16 37.125 101.52 37.395 ;
     RECT  2.16 37.665 101.52 37.935 ;
     RECT  2.16 38.205 101.52 38.475 ;
     RECT  2.16 38.745 101.52 39.015 ;
     RECT  2.16 39.285 101.52 39.555 ;
     RECT  2.16 39.825 101.52 40.095 ;
     RECT  2.16 40.365 101.52 40.635 ;
     RECT  2.16 40.905 101.52 41.175 ;
     RECT  2.16 41.445 101.52 41.715 ;
     RECT  2.16 41.985 101.52 42.255 ;
     RECT  2.16 42.525 101.52 42.795 ;
     RECT  2.16 43.065 101.52 43.335 ;
     RECT  2.16 43.605 101.52 43.875 ;
     RECT  2.16 44.145 101.52 44.415 ;
     RECT  2.16 44.685 101.52 44.955 ;
     RECT  2.16 45.225 101.52 45.495 ;
     RECT  2.16 45.765 101.52 46.035 ;
     RECT  2.16 46.305 101.52 46.575 ;
     RECT  2.16 46.845 101.52 47.115 ;
     RECT  2.16 47.385 101.52 47.655 ;
     RECT  2.16 47.925 101.52 48.195 ;
     RECT  2.16 48.465 101.52 48.735 ;
     RECT  2.16 49.005 101.52 49.275 ;
     RECT  2.16 49.545 101.52 49.815 ;
     RECT  2.16 50.085 101.52 50.355 ;
     RECT  2.16 50.625 101.52 50.895 ;
     RECT  2.16 51.165 101.52 51.435 ;
     RECT  2.16 51.705 101.52 51.975 ;
     RECT  2.16 52.245 101.52 52.515 ;
     RECT  2.16 52.785 101.52 53.055 ;
     RECT  2.16 53.325 101.52 53.595 ;
     RECT  2.16 53.865 101.52 54.135 ;
     RECT  2.16 54.405 101.52 54.675 ;
     RECT  2.16 54.945 101.52 55.215 ;
     RECT  2.16 55.485 101.52 55.755 ;
     RECT  2.16 56.025 101.52 56.295 ;
     RECT  2.16 56.565 101.52 56.835 ;
     RECT  2.16 57.105 101.52 57.375 ;
     RECT  2.16 57.645 101.52 57.915 ;
     RECT  2.16 58.185 101.52 58.455 ;
     RECT  2.16 58.725 101.52 58.995 ;
     RECT  2.16 59.265 101.52 59.535 ;
     RECT  2.16 59.805 101.52 60.075 ;
     RECT  2.16 60.345 101.52 60.615 ;
     RECT  2.16 60.885 101.52 61.155 ;
     RECT  2.16 61.425 101.52 61.695 ;
     RECT  2.16 61.965 101.52 62.235 ;
     RECT  2.16 62.505 101.52 62.775 ;
     RECT  2.16 63.045 101.52 63.315 ;
     RECT  2.16 63.585 101.52 63.855 ;
     RECT  2.16 64.125 101.52 64.395 ;
     RECT  2.16 64.665 101.52 64.935 ;
     RECT  2.16 65.205 101.52 65.475 ;
     RECT  2.16 65.745 101.52 66.015 ;
     RECT  2.16 66.285 101.52 66.555 ;
     RECT  2.16 66.825 101.52 67.095 ;
     RECT  2.16 67.365 101.52 67.635 ;
     RECT  2.16 67.905 101.52 68.175 ;
     RECT  2.16 68.445 101.52 68.715 ;
     RECT  2.16 68.985 101.52 69.255 ;
     RECT  2.16 69.525 101.52 69.795 ;
     RECT  2.16 70.065 101.52 70.335 ;
     RECT  2.16 70.605 101.52 70.875 ;
     RECT  2.16 71.145 101.52 71.415 ;
     RECT  2.16 71.685 101.52 71.955 ;
     RECT  2.16 72.225 101.52 72.495 ;
     RECT  2.16 72.765 101.52 73.035 ;
     RECT  2.16 73.305 101.52 73.575 ;
     RECT  2.16 73.845 101.52 74.115 ;
     RECT  2.16 74.385 101.52 74.655 ;
     RECT  2.16 74.925 101.52 75.195 ;
     RECT  2.16 75.465 101.52 75.735 ;
     RECT  2.16 76.005 101.52 76.275 ;
     RECT  2.16 76.545 101.52 76.815 ;
     RECT  2.16 77.085 101.52 77.355 ;
     RECT  2.16 77.625 101.52 77.895 ;
     RECT  2.16 78.165 101.52 78.435 ;
     RECT  2.16 78.705 101.52 78.975 ;
     RECT  2.16 79.245 101.52 79.515 ;
     RECT  2.16 79.785 101.52 80.055 ;
     RECT  2.16 80.325 101.52 80.595 ;
     RECT  2.16 80.865 101.52 81.135 ;
     RECT  2.16 81.405 101.52 81.675 ;
     RECT  2.16 81.945 101.52 82.215 ;
     RECT  2.16 82.485 101.52 82.755 ;
     RECT  2.16 83.025 101.52 83.295 ;
     RECT  2.16 83.565 101.52 83.835 ;
     RECT  2.16 84.105 101.52 84.375 ;
     RECT  2.16 84.645 101.52 84.915 ;
     RECT  2.16 85.185 101.52 85.455 ;
     RECT  2.16 85.725 101.52 85.995 ;
     RECT  2.16 86.265 101.52 86.535 ;
     RECT  2.16 86.805 101.52 87.075 ;
     RECT  2.16 87.345 101.52 87.615 ;
     RECT  2.16 87.885 101.52 88.155 ;
     RECT  2.16 88.425 101.52 88.695 ;
     RECT  2.16 88.965 101.52 89.235 ;
     RECT  2.16 89.505 101.52 89.775 ;
     RECT  2.16 90.045 101.52 90.315 ;
     RECT  2.16 90.585 101.52 90.855 ;
     RECT  2.16 91.125 101.52 91.395 ;
     RECT  2.16 91.665 101.52 91.935 ;
     RECT  2.16 92.205 101.52 92.475 ;
     RECT  2.16 92.745 101.52 93.015 ;
     RECT  2.16 93.285 101.52 93.555 ;
     RECT  2.16 93.825 101.52 94.095 ;
     RECT  2.16 94.365 101.52 94.635 ;
     RECT  2.16 94.905 101.52 95.175 ;
     RECT  2.16 95.445 101.52 95.715 ;
     RECT  2.16 95.985 101.52 96.255 ;
     RECT  2.16 96.525 101.52 96.795 ;
     RECT  2.16 97.065 101.52 97.335 ;
     RECT  2.16 97.605 101.52 97.875 ;
     RECT  2.16 98.145 101.52 98.415 ;
     RECT  2.16 98.685 101.52 98.955 ;
     RECT  2.16 99.225 101.52 99.495 ;
     RECT  2.16 99.765 101.52 100.035 ;
     RECT  2.16 100.305 101.52 100.575 ;
     RECT  2.16 100.845 101.52 101.115 ;
     RECT  2.16 101.385 101.52 101.655 ;
     RECT  2.16 101.925 101.52 102.195 ;
     RECT  2.16 102.465 101.52 102.735 ;
     RECT  2.16 103.005 101.52 103.275 ;
     RECT  2.16 103.545 101.52 103.815 ;
     RECT  2.16 104.085 101.52 104.355 ;
     RECT  2.16 104.625 101.52 104.895 ;
     RECT  2.16 105.165 101.52 105.435 ;
     RECT  2.16 105.705 101.52 105.975 ;
     RECT  2.16 106.245 101.52 106.515 ;
     RECT  2.16 106.785 101.52 107.055 ;
     RECT  2.16 107.325 101.52 107.595 ;
     RECT  2.16 107.865 101.52 108.135 ;
     RECT  2.16 108.405 101.52 108.675 ;
     RECT  2.16 108.945 101.52 109.215 ;
     RECT  2.16 109.485 101.52 109.755 ;
     RECT  2.16 110.025 101.52 110.295 ;
     RECT  2.16 110.565 101.52 110.835 ;
     RECT  2.16 111.105 101.52 111.375 ;
     RECT  2.16 111.645 101.52 111.915 ;
     RECT  2.16 112.185 101.52 112.455 ;
     RECT  2.16 112.725 101.52 112.995 ;
     RECT  2.16 113.265 101.52 113.535 ;
     RECT  2.16 113.805 101.52 114.075 ;
     RECT  2.16 114.345 101.52 114.615 ;
     RECT  2.16 114.885 101.52 115.155 ;
     RECT  2.16 115.425 101.52 115.695 ;
     RECT  2.16 115.965 101.52 116.235 ;
     RECT  2.16 116.505 101.52 116.775 ;
     RECT  2.16 117.045 101.52 117.315 ;
     RECT  2.16 117.585 101.52 117.855 ;
     RECT  2.16 118.125 101.52 118.395 ;
     RECT  2.16 118.665 101.52 118.935 ;
     RECT  2.16 119.205 101.52 119.475 ;
     RECT  2.16 119.745 101.52 120.015 ;
     RECT  2.16 120.285 101.52 120.555 ;
     RECT  2.16 120.825 101.52 121.095 ;
     RECT  2.16 121.365 101.52 121.635 ;
     RECT  2.16 121.905 101.52 122.175 ;
     RECT  2.16 122.445 101.52 122.715 ;
     RECT  2.16 122.985 101.52 123.255 ;
     RECT  2.16 123.525 101.52 123.795 ;
     RECT  2.16 124.065 101.52 124.335 ;
     RECT  2.16 124.605 101.52 124.875 ;
     RECT  2.16 125.145 101.52 125.415 ;
     RECT  2.16 125.685 101.52 125.955 ;
     RECT  2.16 126.225 101.52 126.495 ;
     RECT  2.16 126.765 101.52 127.035 ;
     RECT  2.16 127.305 101.52 127.44 ;
    LAYER RVTP ;
     RECT  2.16 2.295 101.52 2.565 ;
     RECT  2.16 2.835 101.52 3.105 ;
     RECT  2.16 3.375 101.52 3.645 ;
     RECT  2.16 3.915 101.52 4.185 ;
     RECT  2.16 4.455 101.52 4.725 ;
     RECT  2.16 4.995 101.52 5.265 ;
     RECT  2.16 5.535 101.52 5.805 ;
     RECT  2.16 6.075 101.52 6.345 ;
     RECT  2.16 6.615 101.52 6.885 ;
     RECT  2.16 7.155 101.52 7.425 ;
     RECT  2.16 7.695 101.52 7.965 ;
     RECT  2.16 8.235 101.52 8.505 ;
     RECT  2.16 8.775 101.52 9.045 ;
     RECT  2.16 9.315 101.52 9.585 ;
     RECT  2.16 9.855 101.52 10.125 ;
     RECT  2.16 10.395 101.52 10.665 ;
     RECT  2.16 10.935 101.52 11.205 ;
     RECT  2.16 11.475 101.52 11.745 ;
     RECT  2.16 12.015 101.52 12.285 ;
     RECT  2.16 12.555 101.52 12.825 ;
     RECT  2.16 13.095 101.52 13.365 ;
     RECT  2.16 13.635 101.52 13.905 ;
     RECT  2.16 14.175 101.52 14.445 ;
     RECT  2.16 14.715 101.52 14.985 ;
     RECT  2.16 15.255 101.52 15.525 ;
     RECT  2.16 15.795 101.52 16.065 ;
     RECT  2.16 16.335 101.52 16.605 ;
     RECT  2.16 16.875 101.52 17.145 ;
     RECT  2.16 17.415 101.52 17.685 ;
     RECT  2.16 17.955 101.52 18.225 ;
     RECT  2.16 18.495 101.52 18.765 ;
     RECT  2.16 19.035 101.52 19.305 ;
     RECT  2.16 19.575 101.52 19.845 ;
     RECT  2.16 20.115 101.52 20.385 ;
     RECT  2.16 20.655 101.52 20.925 ;
     RECT  2.16 21.195 101.52 21.465 ;
     RECT  2.16 21.735 101.52 22.005 ;
     RECT  2.16 22.275 101.52 22.545 ;
     RECT  2.16 22.815 101.52 23.085 ;
     RECT  2.16 23.355 101.52 23.625 ;
     RECT  2.16 23.895 101.52 24.165 ;
     RECT  2.16 24.435 101.52 24.705 ;
     RECT  2.16 24.975 101.52 25.245 ;
     RECT  2.16 25.515 101.52 25.785 ;
     RECT  2.16 26.055 101.52 26.325 ;
     RECT  2.16 26.595 101.52 26.865 ;
     RECT  2.16 27.135 101.52 27.405 ;
     RECT  2.16 27.675 101.52 27.945 ;
     RECT  2.16 28.215 101.52 28.485 ;
     RECT  2.16 28.755 101.52 29.025 ;
     RECT  2.16 29.295 101.52 29.565 ;
     RECT  2.16 29.835 101.52 30.105 ;
     RECT  2.16 30.375 101.52 30.645 ;
     RECT  2.16 30.915 101.52 31.185 ;
     RECT  2.16 31.455 101.52 31.725 ;
     RECT  2.16 31.995 101.52 32.265 ;
     RECT  2.16 32.535 101.52 32.805 ;
     RECT  2.16 33.075 101.52 33.345 ;
     RECT  2.16 33.615 101.52 33.885 ;
     RECT  2.16 34.155 101.52 34.425 ;
     RECT  2.16 34.695 101.52 34.965 ;
     RECT  2.16 35.235 101.52 35.505 ;
     RECT  2.16 35.775 101.52 36.045 ;
     RECT  2.16 36.315 101.52 36.585 ;
     RECT  2.16 36.855 101.52 37.125 ;
     RECT  2.16 37.395 101.52 37.665 ;
     RECT  2.16 37.935 101.52 38.205 ;
     RECT  2.16 38.475 101.52 38.745 ;
     RECT  2.16 39.015 101.52 39.285 ;
     RECT  2.16 39.555 101.52 39.825 ;
     RECT  2.16 40.095 101.52 40.365 ;
     RECT  2.16 40.635 101.52 40.905 ;
     RECT  2.16 41.175 101.52 41.445 ;
     RECT  2.16 41.715 101.52 41.985 ;
     RECT  2.16 42.255 101.52 42.525 ;
     RECT  2.16 42.795 101.52 43.065 ;
     RECT  2.16 43.335 101.52 43.605 ;
     RECT  2.16 43.875 101.52 44.145 ;
     RECT  2.16 44.415 101.52 44.685 ;
     RECT  2.16 44.955 101.52 45.225 ;
     RECT  2.16 45.495 101.52 45.765 ;
     RECT  2.16 46.035 101.52 46.305 ;
     RECT  2.16 46.575 101.52 46.845 ;
     RECT  2.16 47.115 101.52 47.385 ;
     RECT  2.16 47.655 101.52 47.925 ;
     RECT  2.16 48.195 101.52 48.465 ;
     RECT  2.16 48.735 101.52 49.005 ;
     RECT  2.16 49.275 101.52 49.545 ;
     RECT  2.16 49.815 101.52 50.085 ;
     RECT  2.16 50.355 101.52 50.625 ;
     RECT  2.16 50.895 101.52 51.165 ;
     RECT  2.16 51.435 101.52 51.705 ;
     RECT  2.16 51.975 101.52 52.245 ;
     RECT  2.16 52.515 101.52 52.785 ;
     RECT  2.16 53.055 101.52 53.325 ;
     RECT  2.16 53.595 101.52 53.865 ;
     RECT  2.16 54.135 101.52 54.405 ;
     RECT  2.16 54.675 101.52 54.945 ;
     RECT  2.16 55.215 101.52 55.485 ;
     RECT  2.16 55.755 101.52 56.025 ;
     RECT  2.16 56.295 101.52 56.565 ;
     RECT  2.16 56.835 101.52 57.105 ;
     RECT  2.16 57.375 101.52 57.645 ;
     RECT  2.16 57.915 101.52 58.185 ;
     RECT  2.16 58.455 101.52 58.725 ;
     RECT  2.16 58.995 101.52 59.265 ;
     RECT  2.16 59.535 101.52 59.805 ;
     RECT  2.16 60.075 101.52 60.345 ;
     RECT  2.16 60.615 101.52 60.885 ;
     RECT  2.16 61.155 101.52 61.425 ;
     RECT  2.16 61.695 101.52 61.965 ;
     RECT  2.16 62.235 101.52 62.505 ;
     RECT  2.16 62.775 101.52 63.045 ;
     RECT  2.16 63.315 101.52 63.585 ;
     RECT  2.16 63.855 101.52 64.125 ;
     RECT  2.16 64.395 101.52 64.665 ;
     RECT  2.16 64.935 101.52 65.205 ;
     RECT  2.16 65.475 101.52 65.745 ;
     RECT  2.16 66.015 101.52 66.285 ;
     RECT  2.16 66.555 101.52 66.825 ;
     RECT  2.16 67.095 101.52 67.365 ;
     RECT  2.16 67.635 101.52 67.905 ;
     RECT  2.16 68.175 101.52 68.445 ;
     RECT  2.16 68.715 101.52 68.985 ;
     RECT  2.16 69.255 101.52 69.525 ;
     RECT  2.16 69.795 101.52 70.065 ;
     RECT  2.16 70.335 101.52 70.605 ;
     RECT  2.16 70.875 101.52 71.145 ;
     RECT  2.16 71.415 101.52 71.685 ;
     RECT  2.16 71.955 101.52 72.225 ;
     RECT  2.16 72.495 101.52 72.765 ;
     RECT  2.16 73.035 101.52 73.305 ;
     RECT  2.16 73.575 101.52 73.845 ;
     RECT  2.16 74.115 101.52 74.385 ;
     RECT  2.16 74.655 101.52 74.925 ;
     RECT  2.16 75.195 101.52 75.465 ;
     RECT  2.16 75.735 101.52 76.005 ;
     RECT  2.16 76.275 101.52 76.545 ;
     RECT  2.16 76.815 101.52 77.085 ;
     RECT  2.16 77.355 101.52 77.625 ;
     RECT  2.16 77.895 101.52 78.165 ;
     RECT  2.16 78.435 101.52 78.705 ;
     RECT  2.16 78.975 101.52 79.245 ;
     RECT  2.16 79.515 101.52 79.785 ;
     RECT  2.16 80.055 101.52 80.325 ;
     RECT  2.16 80.595 101.52 80.865 ;
     RECT  2.16 81.135 101.52 81.405 ;
     RECT  2.16 81.675 101.52 81.945 ;
     RECT  2.16 82.215 101.52 82.485 ;
     RECT  2.16 82.755 101.52 83.025 ;
     RECT  2.16 83.295 101.52 83.565 ;
     RECT  2.16 83.835 101.52 84.105 ;
     RECT  2.16 84.375 101.52 84.645 ;
     RECT  2.16 84.915 101.52 85.185 ;
     RECT  2.16 85.455 101.52 85.725 ;
     RECT  2.16 85.995 101.52 86.265 ;
     RECT  2.16 86.535 101.52 86.805 ;
     RECT  2.16 87.075 101.52 87.345 ;
     RECT  2.16 87.615 101.52 87.885 ;
     RECT  2.16 88.155 101.52 88.425 ;
     RECT  2.16 88.695 101.52 88.965 ;
     RECT  2.16 89.235 101.52 89.505 ;
     RECT  2.16 89.775 101.52 90.045 ;
     RECT  2.16 90.315 101.52 90.585 ;
     RECT  2.16 90.855 101.52 91.125 ;
     RECT  2.16 91.395 101.52 91.665 ;
     RECT  2.16 91.935 101.52 92.205 ;
     RECT  2.16 92.475 101.52 92.745 ;
     RECT  2.16 93.015 101.52 93.285 ;
     RECT  2.16 93.555 101.52 93.825 ;
     RECT  2.16 94.095 101.52 94.365 ;
     RECT  2.16 94.635 101.52 94.905 ;
     RECT  2.16 95.175 101.52 95.445 ;
     RECT  2.16 95.715 101.52 95.985 ;
     RECT  2.16 96.255 101.52 96.525 ;
     RECT  2.16 96.795 101.52 97.065 ;
     RECT  2.16 97.335 101.52 97.605 ;
     RECT  2.16 97.875 101.52 98.145 ;
     RECT  2.16 98.415 101.52 98.685 ;
     RECT  2.16 98.955 101.52 99.225 ;
     RECT  2.16 99.495 101.52 99.765 ;
     RECT  2.16 100.035 101.52 100.305 ;
     RECT  2.16 100.575 101.52 100.845 ;
     RECT  2.16 101.115 101.52 101.385 ;
     RECT  2.16 101.655 101.52 101.925 ;
     RECT  2.16 102.195 101.52 102.465 ;
     RECT  2.16 102.735 101.52 103.005 ;
     RECT  2.16 103.275 101.52 103.545 ;
     RECT  2.16 103.815 101.52 104.085 ;
     RECT  2.16 104.355 101.52 104.625 ;
     RECT  2.16 104.895 101.52 105.165 ;
     RECT  2.16 105.435 101.52 105.705 ;
     RECT  2.16 105.975 101.52 106.245 ;
     RECT  2.16 106.515 101.52 106.785 ;
     RECT  2.16 107.055 101.52 107.325 ;
     RECT  2.16 107.595 101.52 107.865 ;
     RECT  2.16 108.135 101.52 108.405 ;
     RECT  2.16 108.675 101.52 108.945 ;
     RECT  2.16 109.215 101.52 109.485 ;
     RECT  2.16 109.755 101.52 110.025 ;
     RECT  2.16 110.295 101.52 110.565 ;
     RECT  2.16 110.835 101.52 111.105 ;
     RECT  2.16 111.375 101.52 111.645 ;
     RECT  2.16 111.915 101.52 112.185 ;
     RECT  2.16 112.455 101.52 112.725 ;
     RECT  2.16 112.995 101.52 113.265 ;
     RECT  2.16 113.535 101.52 113.805 ;
     RECT  2.16 114.075 101.52 114.345 ;
     RECT  2.16 114.615 101.52 114.885 ;
     RECT  2.16 115.155 101.52 115.425 ;
     RECT  2.16 115.695 101.52 115.965 ;
     RECT  2.16 116.235 101.52 116.505 ;
     RECT  2.16 116.775 101.52 117.045 ;
     RECT  2.16 117.315 101.52 117.585 ;
     RECT  2.16 117.855 101.52 118.125 ;
     RECT  2.16 118.395 101.52 118.665 ;
     RECT  2.16 118.935 101.52 119.205 ;
     RECT  2.16 119.475 101.52 119.745 ;
     RECT  2.16 120.015 101.52 120.285 ;
     RECT  2.16 120.555 101.52 120.825 ;
     RECT  2.16 121.095 101.52 121.365 ;
     RECT  2.16 121.635 101.52 121.905 ;
     RECT  2.16 122.175 101.52 122.445 ;
     RECT  2.16 122.715 101.52 122.985 ;
     RECT  2.16 123.255 101.52 123.525 ;
     RECT  2.16 123.795 101.52 124.065 ;
     RECT  2.16 124.335 101.52 124.605 ;
     RECT  2.16 124.875 101.52 125.145 ;
     RECT  2.16 125.415 101.52 125.685 ;
     RECT  2.16 125.955 101.52 126.225 ;
     RECT  2.16 126.495 101.52 126.765 ;
     RECT  2.16 127.035 101.52 127.305 ;
    LAYER M1 ;
     RECT  2.16 2.151 101.52 127.449 ;
    LAYER M2 ;
     RECT  0.103 7.362 2.16 7.956 ;
     RECT  0.103 13.032 2.16 13.05 ;
     RECT  0.103 22.212 2.16 22.23 ;
     RECT  0.103 23.832 2.16 23.85 ;
     RECT  0.535 27.342 2.16 27.36 ;
     RECT  0.535 38.142 2.16 38.16 ;
     RECT  0.103 63.252 2.16 63.27 ;
     RECT  0.103 64.944 2.16 64.962 ;
     RECT  0.103 73.512 2.16 73.53 ;
     RECT  0.103 79.182 2.16 79.2 ;
     RECT  0.103 84.348 2.16 84.366 ;
     RECT  0.103 95.112 2.16 95.13 ;
     RECT  0.103 104.292 2.16 104.31 ;
     RECT  0.103 105.912 2.16 105.93 ;
     RECT  0.103 109.422 2.16 109.44 ;
     RECT  0.103 114.552 2.16 114.57 ;
     RECT  0.103 119.682 2.16 120.276 ;
     RECT  2.16 2.151 101.52 127.449 ;
     RECT  101.52 49.176 101.543 55.674 ;
     RECT  101.52 44.046 102.011 47.034 ;
     RECT  101.52 40.986 102.047 43.254 ;
     RECT  101.52 56.466 102.047 59.184 ;
     RECT  101.52 77.796 102.047 88.254 ;
     RECT  101.52 89.316 102.047 91.584 ;
     RECT  101.52 38.682 102.515 40.158 ;
     RECT  102.047 56.466 102.551 58.374 ;
     RECT  101.52 59.976 102.551 64.044 ;
     RECT  101.52 75.096 102.551 77.004 ;
     RECT  101.52 93.186 102.551 93.474 ;
     RECT  102.515 39.186 102.587 40.158 ;
     RECT  102.047 41.076 102.587 43.254 ;
     RECT  102.011 44.046 102.587 44.604 ;
     RECT  102.011 45.396 102.587 47.034 ;
     RECT  101.52 47.826 102.587 48.384 ;
     RECT  101.543 49.176 102.587 53.244 ;
     RECT  101.543 54.036 102.587 55.674 ;
     RECT  102.551 56.466 102.587 56.484 ;
     RECT  102.551 57.276 102.587 58.374 ;
     RECT  102.047 59.166 102.587 59.184 ;
     RECT  102.551 59.976 102.587 60.534 ;
     RECT  102.551 61.326 102.587 64.044 ;
     RECT  101.52 64.836 102.587 66.204 ;
     RECT  101.52 66.996 102.587 68.364 ;
     RECT  101.52 69.156 102.587 69.714 ;
     RECT  101.52 70.506 102.587 70.83 ;
     RECT  101.52 71.586 102.587 72.684 ;
     RECT  101.52 73.476 102.587 74.304 ;
     RECT  102.551 75.096 102.587 75.114 ;
     RECT  102.551 75.906 102.587 77.004 ;
     RECT  102.047 77.796 102.587 88.182 ;
     RECT  102.047 89.406 102.587 90.774 ;
     RECT  102.047 91.566 102.587 91.584 ;
     RECT  102.551 93.456 102.587 93.474 ;
     RECT  101.52 36.396 102.623 36.684 ;
     RECT  102.587 42.156 102.623 42.174 ;
     RECT  102.587 46.116 102.623 46.134 ;
     RECT  102.587 78.066 102.623 78.084 ;
     RECT  102.587 79.758 102.623 79.776 ;
     RECT  102.587 81.486 102.623 81.504 ;
     RECT  102.587 84.888 102.623 84.906 ;
     RECT  102.587 87.156 102.623 87.174 ;
     RECT  102.587 88.164 102.623 88.182 ;
     RECT  102.623 36.396 102.659 36.414 ;
     RECT  101.52 37.476 102.659 37.494 ;
     RECT  102.587 54.684 103.595 54.702 ;
     RECT  102.587 82.566 103.595 82.584 ;
    LAYER M3 ;
     RECT  2.415 2.143 2.505 2.413 ;
     RECT  7.815 2.143 7.905 2.413 ;
     RECT  13.215 2.143 13.305 2.413 ;
     RECT  18.615 2.143 18.705 2.413 ;
     RECT  24.015 2.143 24.105 2.413 ;
     RECT  29.415 2.143 29.505 2.413 ;
     RECT  34.815 2.143 34.905 2.413 ;
     RECT  40.215 2.143 40.305 2.413 ;
     RECT  45.615 2.143 45.705 2.413 ;
     RECT  51.015 2.143 51.105 2.413 ;
     RECT  56.415 2.143 56.505 2.413 ;
     RECT  61.815 2.143 61.905 2.413 ;
     RECT  67.215 2.143 67.305 2.413 ;
     RECT  72.615 2.143 72.705 2.413 ;
     RECT  78.015 2.143 78.105 2.413 ;
     RECT  83.415 2.143 83.505 2.413 ;
     RECT  88.815 2.143 88.905 2.413 ;
     RECT  94.215 2.143 94.305 2.413 ;
     RECT  99.615 2.143 99.705 2.413 ;
     RECT  2.415 2.413 2.697 7.465 ;
     RECT  3.528 7.321 3.546 7.465 ;
     RECT  2.415 7.465 3.546 7.867 ;
     RECT  4.32 7.771 4.338 7.867 ;
     RECT  0.108 7.357 0.126 7.997 ;
     RECT  2.415 7.867 4.338 8.395 ;
     RECT  2.304 8.395 4.338 8.465 ;
     RECT  2.415 8.465 4.338 8.735 ;
     RECT  5.616 7.897 5.634 8.815 ;
     RECT  4.176 8.735 4.338 9.085 ;
     RECT  4.176 9.085 4.554 9.211 ;
     RECT  5.364 8.815 5.634 9.211 ;
     RECT  2.415 8.735 3.438 9.247 ;
     RECT  4.176 9.211 5.634 9.311 ;
     RECT  7.815 2.413 8.097 9.349 ;
     RECT  7.524 9.349 8.097 9.389 ;
     RECT  2.304 9.247 3.438 9.661 ;
     RECT  4.176 9.311 4.806 9.661 ;
     RECT  2.304 9.661 4.806 9.677 ;
     RECT  5.616 9.311 5.634 9.931 ;
     RECT  6.66 8.851 6.678 9.931 ;
     RECT  3.42 9.677 4.806 10.201 ;
     RECT  5.616 9.931 6.678 10.201 ;
     RECT  3.42 10.201 6.678 10.319 ;
     RECT  3.456 10.319 6.678 10.463 ;
     RECT  4.176 10.463 6.678 11.011 ;
     RECT  2.304 9.677 2.697 11.021 ;
     RECT  2.415 11.021 2.697 11.245 ;
     RECT  2.415 11.245 3.294 11.281 ;
     RECT  4.176 11.011 7.038 11.281 ;
     RECT  2.415 11.281 7.038 11.851 ;
     RECT  2.304 11.851 7.038 11.975 ;
     RECT  2.415 11.975 7.038 12.281 ;
     RECT  7.815 9.389 8.097 12.451 ;
     RECT  2.415 12.281 4.338 12.715 ;
     RECT  2.304 12.715 4.338 12.785 ;
     RECT  2.415 12.785 4.338 13.027 ;
     RECT  5.076 12.281 7.038 13.027 ;
     RECT  0.108 13.027 0.126 13.181 ;
     RECT  2.415 13.027 7.038 13.325 ;
     RECT  2.415 13.325 2.826 14.107 ;
     RECT  3.636 13.325 7.038 14.107 ;
     RECT  0.108 14.011 0.126 14.141 ;
     RECT  2.415 14.107 7.038 14.443 ;
     RECT  2.34 14.443 7.038 14.521 ;
     RECT  7.815 12.451 8.19 14.521 ;
     RECT  2.34 14.521 8.19 14.675 ;
     RECT  2.412 14.675 8.19 14.945 ;
     RECT  2.415 14.945 8.19 15.871 ;
     RECT  9.144 9.391 9.162 15.871 ;
     RECT  2.415 15.871 9.162 16.171 ;
     RECT  2.304 16.171 9.162 16.295 ;
     RECT  2.415 16.295 9.162 17.035 ;
     RECT  2.34 17.035 9.162 17.105 ;
     RECT  2.415 17.105 9.162 17.887 ;
     RECT  2.304 17.887 9.162 18.455 ;
     RECT  2.415 18.455 9.162 19.195 ;
     RECT  2.412 19.195 9.162 19.265 ;
     RECT  2.415 19.265 9.162 20.093 ;
     RECT  2.415 20.093 2.697 20.491 ;
     RECT  2.304 20.491 2.697 20.893 ;
     RECT  3.42 20.093 9.162 20.893 ;
     RECT  2.304 20.893 9.162 21.425 ;
     RECT  2.415 21.425 9.162 21.541 ;
     RECT  10.008 19.381 10.026 21.541 ;
     RECT  2.415 21.541 10.026 22.235 ;
     RECT  0.108 22.207 0.126 22.253 ;
     RECT  3.672 22.235 10.026 22.253 ;
     RECT  2.415 22.235 2.862 22.469 ;
     RECT  2.415 22.469 2.697 22.651 ;
     RECT  2.304 22.651 2.697 23.287 ;
     RECT  3.672 22.253 9.162 23.287 ;
     RECT  2.304 23.287 9.162 23.585 ;
     RECT  2.415 23.585 9.162 23.819 ;
     RECT  0.108 23.827 0.126 23.981 ;
     RECT  2.415 23.819 2.697 24.379 ;
     RECT  2.304 24.379 2.697 25.003 ;
     RECT  3.42 23.819 9.162 25.003 ;
     RECT  2.304 25.003 9.162 25.205 ;
     RECT  2.304 25.205 2.697 25.745 ;
     RECT  2.34 25.745 2.697 26.527 ;
     RECT  2.304 26.527 2.697 26.683 ;
     RECT  3.42 25.205 9.162 26.683 ;
     RECT  2.304 26.683 9.162 27.095 ;
     RECT  0.54 27.337 0.558 27.437 ;
     RECT  2.415 27.095 9.162 27.635 ;
     RECT  2.415 27.635 2.697 27.835 ;
     RECT  2.412 27.835 2.697 27.905 ;
     RECT  2.415 27.905 2.697 28.561 ;
     RECT  3.6 27.635 9.162 28.561 ;
     RECT  2.415 28.561 9.162 28.687 ;
     RECT  2.304 28.687 9.162 29.219 ;
     RECT  2.304 29.219 2.97 29.255 ;
     RECT  2.304 29.255 2.79 30.145 ;
     RECT  3.708 29.219 9.162 30.145 ;
     RECT  2.304 30.145 9.162 30.335 ;
     RECT  3.42 30.335 9.162 30.839 ;
     RECT  3.456 30.839 9.162 30.983 ;
     RECT  3.564 30.983 9.162 31.891 ;
     RECT  2.304 30.335 2.697 31.915 ;
     RECT  3.42 31.891 9.162 31.915 ;
     RECT  2.304 31.915 9.162 34.385 ;
     RECT  2.415 34.385 9.162 35.167 ;
     RECT  2.304 35.167 9.162 35.735 ;
     RECT  100.836 36.085 100.854 36.121 ;
     RECT  100.836 36.121 101.07 36.211 ;
     RECT  100.836 36.211 101.178 36.391 ;
     RECT  99.615 2.413 99.897 36.625 ;
     RECT  100.764 36.391 101.178 36.625 ;
     RECT  3.708 35.735 9.162 36.661 ;
     RECT  10.008 22.253 10.026 36.661 ;
     RECT  102.636 36.391 102.654 36.661 ;
     RECT  102.6 36.661 102.654 36.701 ;
     RECT  13.215 2.413 13.497 36.751 ;
     RECT  18.615 2.413 18.897 36.751 ;
     RECT  24.015 2.413 24.297 36.751 ;
     RECT  34.815 2.413 35.097 36.763 ;
     RECT  45.615 2.413 45.897 36.763 ;
     RECT  56.415 2.413 56.697 36.763 ;
     RECT  67.215 2.413 67.497 36.763 ;
     RECT  78.015 2.413 78.297 36.763 ;
     RECT  88.815 2.413 89.097 36.763 ;
     RECT  13.104 36.751 13.497 36.797 ;
     RECT  18 36.751 18.897 36.797 ;
     RECT  23.904 36.751 24.297 36.797 ;
     RECT  34.704 36.763 35.097 36.815 ;
     RECT  45.504 36.763 45.897 36.815 ;
     RECT  56.304 36.763 56.697 36.815 ;
     RECT  67.104 36.763 67.497 36.815 ;
     RECT  77.904 36.763 78.297 36.815 ;
     RECT  88.704 36.763 89.097 36.815 ;
     RECT  99.615 36.625 101.178 36.895 ;
     RECT  97.56 36.763 97.578 37.003 ;
     RECT  97.38 37.003 97.578 37.057 ;
     RECT  97.38 37.057 98.226 37.093 ;
     RECT  99 36.895 101.178 37.093 ;
     RECT  96.912 37.093 101.178 37.121 ;
     RECT  2.304 35.735 2.697 37.165 ;
     RECT  3.708 36.661 10.026 37.165 ;
     RECT  97.848 37.121 101.178 37.355 ;
     RECT  102.6 36.701 102.618 37.471 ;
     RECT  96.912 37.121 96.93 37.561 ;
     RECT  102.6 37.471 102.654 37.565 ;
     RECT  94.215 2.413 94.497 37.627 ;
     RECT  96.84 37.561 96.93 37.661 ;
     RECT  96.84 37.661 96.858 37.733 ;
     RECT  99.576 37.355 99.99 37.859 ;
     RECT  2.304 37.165 10.026 37.895 ;
     RECT  102.636 37.565 102.654 37.997 ;
     RECT  97.848 37.355 98.514 38.011 ;
     RECT  2.415 37.895 10.026 38.101 ;
     RECT  99.615 37.859 99.99 38.101 ;
     RECT  100.728 37.355 101.178 38.101 ;
     RECT  94.215 37.627 95.202 38.165 ;
     RECT  99.615 38.101 101.178 38.173 ;
     RECT  0.54 38.137 0.558 38.237 ;
     RECT  94.215 38.165 95.13 38.273 ;
     RECT  2.415 38.101 10.494 38.635 ;
     RECT  28.152 36.751 28.17 38.641 ;
     RECT  29.415 2.413 29.697 38.641 ;
     RECT  2.304 38.635 10.494 38.705 ;
     RECT  102.492 38.395 102.51 38.705 ;
     RECT  97.776 38.011 98.514 38.731 ;
     RECT  97.74 38.731 98.514 38.849 ;
     RECT  99.615 38.173 101.394 38.861 ;
     RECT  99.615 38.861 101.214 38.939 ;
     RECT  97.74 38.849 97.758 39.055 ;
     RECT  97.704 39.055 97.758 39.083 ;
     RECT  98.496 38.849 98.514 39.091 ;
     RECT  99.615 38.939 100.926 39.091 ;
     RECT  98.496 39.091 100.926 39.245 ;
     RECT  99.324 39.245 99.897 39.479 ;
     RECT  2.415 38.705 10.494 39.515 ;
     RECT  97.704 39.083 97.722 39.631 ;
     RECT  96.984 39.631 97.722 39.749 ;
     RECT  2.415 39.515 2.754 39.785 ;
     RECT  99.432 39.479 99.897 39.785 ;
     RECT  96.984 39.749 97.29 39.917 ;
     RECT  2.415 39.785 2.697 39.931 ;
     RECT  95.4 40.123 95.418 40.135 ;
     RECT  100.908 39.245 100.926 40.135 ;
     RECT  96.984 39.917 97.146 40.171 ;
     RECT  95.22 40.135 95.418 40.199 ;
     RECT  99.615 39.785 99.897 40.261 ;
     RECT  100.908 40.135 101.178 40.261 ;
     RECT  96.192 40.171 97.146 40.289 ;
     RECT  99.615 40.261 101.178 40.289 ;
     RECT  90.648 40.123 90.666 40.301 ;
     RECT  96.192 40.289 96.21 40.325 ;
     RECT  11.7 37.561 11.718 40.36 ;
     RECT  11.7 40.36 11.862 40.397 ;
     RECT  14.796 40.267 14.814 40.397 ;
     RECT  3.528 39.515 10.494 40.411 ;
     RECT  11.7 40.397 11.718 40.411 ;
     RECT  94.215 38.273 94.497 40.411 ;
     RECT  95.22 40.199 95.238 40.411 ;
     RECT  94.215 40.411 95.238 40.445 ;
     RECT  3.528 40.411 11.718 40.469 ;
     RECT  2.304 39.931 2.697 40.675 ;
     RECT  3.528 40.469 10.494 40.675 ;
     RECT  98.496 39.245 98.514 40.711 ;
     RECT  99.615 40.289 100.998 40.711 ;
     RECT  2.304 40.675 10.494 40.865 ;
     RECT  98.496 40.711 100.998 40.901 ;
     RECT  94.215 40.445 94.698 40.973 ;
     RECT  102.564 39.181 102.582 40.981 ;
     RECT  102.024 40.981 102.582 41.021 ;
     RECT  98.496 40.901 100.602 41.099 ;
     RECT  98.496 41.099 98.694 41.135 ;
     RECT  2.304 40.865 2.697 41.261 ;
     RECT  11.7 40.469 11.718 41.341 ;
     RECT  98.496 41.135 98.586 41.341 ;
     RECT  99.432 41.099 100.494 41.369 ;
     RECT  94.215 40.973 94.662 41.371 ;
     RECT  11.232 41.341 11.718 41.405 ;
     RECT  94.068 41.371 94.662 41.405 ;
     RECT  97.128 40.289 97.146 41.405 ;
     RECT  99.54 41.369 100.494 41.405 ;
     RECT  3.42 40.865 10.494 41.513 ;
     RECT  94.068 41.405 94.497 41.513 ;
     RECT  3.708 41.513 10.494 41.521 ;
     RECT  3.708 41.521 10.566 41.597 ;
     RECT  98.028 41.341 98.586 41.639 ;
     RECT  2.415 41.261 2.697 41.647 ;
     RECT  95.76 41.521 95.778 41.675 ;
     RECT  98.316 41.639 98.514 41.675 ;
     RECT  99.615 41.405 100.494 41.881 ;
     RECT  99.615 41.881 100.638 42.025 ;
     RECT  2.415 41.647 2.826 42.091 ;
     RECT  102.564 41.021 102.582 42.151 ;
     RECT  99.615 42.025 101.106 42.187 ;
     RECT  2.304 42.091 2.826 42.295 ;
     RECT  3.708 41.597 10.494 42.295 ;
     RECT  102.564 42.151 102.618 42.317 ;
     RECT  18.615 36.797 18.897 42.421 ;
     RECT  98.496 41.675 98.514 42.421 ;
     RECT  99.288 42.187 101.106 42.421 ;
     RECT  13.215 36.797 13.497 42.427 ;
     RECT  18.252 42.421 19.386 42.461 ;
     RECT  13.215 42.427 13.59 42.557 ;
     RECT  98.496 42.421 101.106 42.565 ;
     RECT  2.304 42.295 10.494 42.755 ;
     RECT  97.272 41.521 97.29 42.871 ;
     RECT  98.496 42.565 101.214 42.871 ;
     RECT  97.272 42.871 101.214 42.989 ;
     RECT  2.304 42.755 2.862 43.025 ;
     RECT  13.215 42.557 13.497 43.033 ;
     RECT  2.415 43.025 2.862 43.169 ;
     RECT  97.272 42.989 100.746 43.169 ;
     RECT  102.564 42.317 102.582 43.259 ;
     RECT  94.215 41.513 94.497 43.411 ;
     RECT  97.272 43.169 100.638 43.529 ;
     RECT  98.496 43.529 98.766 43.565 ;
     RECT  12.816 43.033 13.497 43.609 ;
     RECT  94.215 43.411 94.662 43.637 ;
     RECT  96.264 43.501 96.282 43.681 ;
     RECT  97.272 43.529 97.362 43.681 ;
     RECT  97.056 43.681 97.362 43.799 ;
     RECT  2.415 43.169 2.79 43.807 ;
     RECT  97.056 43.799 97.074 43.835 ;
     RECT  96.264 43.681 96.318 43.879 ;
     RECT  2.304 43.807 2.79 43.951 ;
     RECT  3.708 42.755 10.494 43.951 ;
     RECT  99.615 43.529 100.638 43.951 ;
     RECT  102.024 43.579 102.042 44.011 ;
     RECT  99.615 43.951 100.746 44.185 ;
     RECT  12.816 43.609 14.022 44.339 ;
     RECT  99.615 44.185 101.034 44.339 ;
     RECT  15.336 42.151 15.354 44.347 ;
     RECT  98.496 43.565 98.514 44.383 ;
     RECT  99.615 44.339 100.422 44.419 ;
     RECT  94.215 43.637 94.497 44.443 ;
     RECT  99.324 44.419 100.422 44.609 ;
     RECT  2.304 43.951 10.494 44.645 ;
     RECT  98.496 44.383 98.55 44.645 ;
     RECT  96.264 43.879 96.786 44.689 ;
     RECT  98.496 44.645 98.514 44.761 ;
     RECT  102.024 44.011 102.582 44.851 ;
     RECT  98.244 44.761 98.514 44.875 ;
     RECT  14.796 44.347 15.354 44.879 ;
     RECT  94.215 44.443 95.058 44.879 ;
     RECT  96.264 44.689 97.182 44.879 ;
     RECT  99.396 44.609 100.422 44.879 ;
     RECT  101.988 44.851 102.582 44.909 ;
     RECT  99.468 44.879 100.422 44.915 ;
     RECT  94.215 44.879 94.698 44.951 ;
     RECT  11.7 41.405 11.718 44.995 ;
     RECT  96.264 44.879 97.074 45.149 ;
     RECT  2.304 44.645 2.934 45.185 ;
     RECT  96.264 45.149 96.534 45.185 ;
     RECT  99.615 44.915 100.422 45.265 ;
     RECT  101.16 44.581 101.178 45.265 ;
     RECT  3.672 44.645 10.494 45.301 ;
     RECT  96.264 45.185 96.282 45.329 ;
     RECT  3.672 45.301 10.818 45.419 ;
     RECT  99.615 45.265 101.178 45.455 ;
     RECT  98.1 44.875 98.514 45.581 ;
     RECT  94.215 44.951 94.662 45.599 ;
     RECT  2.34 45.185 2.934 45.805 ;
     RECT  3.672 45.419 10.026 45.805 ;
     RECT  15.192 44.879 15.354 45.841 ;
     RECT  97.2 45.925 97.218 45.931 ;
     RECT  97.2 45.931 97.362 45.965 ;
     RECT  17.028 45.931 17.658 45.968 ;
     RECT  17.64 45.968 17.658 46.013 ;
     RECT  97.344 45.965 97.362 46.013 ;
     RECT  98.496 45.581 98.514 46.111 ;
     RECT  102.564 44.909 102.582 46.111 ;
     RECT  102.564 46.111 102.618 46.205 ;
     RECT  97.596 46.171 97.65 46.229 ;
     RECT  2.34 45.805 10.026 46.265 ;
     RECT  34.815 36.815 35.097 46.309 ;
     RECT  98.496 46.111 98.658 46.381 ;
     RECT  99.615 45.455 100.926 46.381 ;
     RECT  2.34 46.265 2.862 46.411 ;
     RECT  98.496 46.381 100.926 46.885 ;
     RECT  94.215 45.599 94.497 46.921 ;
     RECT  12.816 44.339 13.914 47.083 ;
     RECT  14.688 45.841 15.354 47.083 ;
     RECT  98.496 46.885 101.034 47.155 ;
     RECT  2.304 46.411 2.862 47.191 ;
     RECT  3.672 46.265 10.026 47.191 ;
     RECT  94.215 46.921 94.698 47.191 ;
     RECT  97.596 46.229 97.614 47.191 ;
     RECT  10.8 45.419 10.818 47.219 ;
     RECT  94.215 47.191 95.166 47.309 ;
     RECT  96.84 47.191 97.614 47.315 ;
     RECT  2.304 47.191 10.026 47.345 ;
     RECT  96.84 47.315 96.858 47.345 ;
     RECT  18.615 42.461 18.897 47.551 ;
     RECT  24.015 36.797 24.297 47.551 ;
     RECT  34.815 46.309 35.622 47.551 ;
     RECT  45.615 36.815 45.897 47.551 ;
     RECT  56.415 36.815 56.697 47.551 ;
     RECT  67.215 36.815 67.497 47.551 ;
     RECT  78.015 36.815 78.297 47.551 ;
     RECT  88.815 36.815 89.097 47.551 ;
     RECT  97.596 47.315 97.614 47.551 ;
     RECT  98.496 47.155 101.142 47.551 ;
     RECT  12.816 47.083 15.354 47.579 ;
     RECT  18.18 47.551 18.897 47.597 ;
     RECT  23.904 47.551 24.297 47.597 ;
     RECT  34.704 47.551 35.622 47.597 ;
     RECT  45.504 47.551 45.897 47.597 ;
     RECT  56.304 47.551 56.697 47.597 ;
     RECT  67.104 47.551 67.497 47.597 ;
     RECT  77.904 47.551 78.297 47.597 ;
     RECT  88.704 47.551 89.097 47.597 ;
     RECT  2.415 47.345 10.026 47.615 ;
     RECT  97.596 47.551 101.142 47.615 ;
     RECT  11.664 44.995 11.718 47.731 ;
     RECT  12.816 47.579 13.914 47.731 ;
     RECT  97.884 47.615 101.142 47.731 ;
     RECT  2.415 47.615 2.862 47.885 ;
     RECT  97.884 47.731 101.178 47.885 ;
     RECT  2.415 47.885 2.697 48.139 ;
     RECT  102.564 46.205 102.582 48.271 ;
     RECT  97.884 47.885 100.926 48.361 ;
     RECT  102.024 48.271 102.582 48.365 ;
     RECT  96.048 48.091 96.066 48.389 ;
     RECT  97.812 48.361 100.926 48.425 ;
     RECT  97.812 48.425 98.514 48.541 ;
     RECT  97.38 48.541 98.514 48.695 ;
     RECT  96.588 48.541 96.606 48.731 ;
     RECT  3.672 47.615 10.026 48.901 ;
     RECT  10.836 48.703 10.854 48.901 ;
     RECT  99.615 48.425 100.926 49.081 ;
     RECT  11.664 47.731 13.914 49.171 ;
     RECT  14.688 47.579 15.354 49.171 ;
     RECT  94.215 47.309 94.497 49.171 ;
     RECT  99.615 49.081 101.178 49.171 ;
     RECT  102.564 48.365 102.582 49.195 ;
     RECT  3.672 48.901 10.854 49.199 ;
     RECT  98.028 48.695 98.514 49.199 ;
     RECT  2.304 48.139 2.697 49.235 ;
     RECT  99.504 49.171 101.178 49.235 ;
     RECT  2.412 49.235 2.697 49.315 ;
     RECT  3.672 49.199 10.494 49.315 ;
     RECT  102.528 49.195 102.582 49.469 ;
     RECT  2.412 49.315 10.494 49.505 ;
     RECT  94.215 49.171 94.662 49.577 ;
     RECT  98.388 49.199 98.514 49.613 ;
     RECT  97.524 49.579 97.542 49.739 ;
     RECT  99.504 49.235 101.07 49.811 ;
     RECT  95.58 49.579 95.598 49.891 ;
     RECT  99.504 49.811 100.098 49.891 ;
     RECT  2.412 49.505 2.697 49.901 ;
     RECT  95.58 49.891 95.778 50.009 ;
     RECT  99.324 49.891 100.098 50.009 ;
     RECT  3.672 49.505 10.494 50.017 ;
     RECT  98.46 49.613 98.514 50.045 ;
     RECT  98.496 50.045 98.514 50.125 ;
     RECT  99.324 50.009 99.897 50.125 ;
     RECT  90.648 50.017 90.666 50.153 ;
     RECT  97.272 50.125 97.506 50.279 ;
     RECT  97.272 50.279 97.29 50.315 ;
     RECT  98.496 50.125 99.897 50.315 ;
     RECT  95.76 50.009 95.778 50.459 ;
     RECT  3.672 50.017 10.818 50.549 ;
     RECT  101.16 50.125 101.178 50.665 ;
     RECT  101.016 50.665 101.178 50.701 ;
     RECT  2.415 49.901 2.697 50.731 ;
     RECT  3.672 50.549 10.494 50.731 ;
     RECT  11.664 49.171 15.354 50.791 ;
     RECT  16.236 39.487 16.254 50.791 ;
     RECT  99.324 50.315 99.897 50.791 ;
     RECT  100.692 50.701 101.178 50.791 ;
     RECT  11.664 50.791 16.254 51.089 ;
     RECT  98.496 50.315 98.55 51.241 ;
     RECT  99.324 50.791 101.178 51.241 ;
     RECT  96.768 51.307 96.786 51.359 ;
     RECT  2.304 50.731 10.494 51.395 ;
     RECT  28.152 38.641 29.697 51.629 ;
     RECT  2.304 51.395 2.697 51.665 ;
     RECT  96.912 51.511 96.93 51.665 ;
     RECT  98.244 51.241 101.178 51.701 ;
     RECT  24.015 47.597 24.297 51.709 ;
     RECT  26.388 38.947 26.406 51.781 ;
     RECT  27.144 40.801 27.162 51.781 ;
     RECT  98.244 51.701 101.07 51.781 ;
     RECT  24.015 51.709 24.534 51.935 ;
     RECT  98.064 51.781 101.07 52.015 ;
     RECT  94.215 49.577 94.497 52.051 ;
     RECT  34.815 47.597 35.622 52.141 ;
     RECT  90.648 52.051 90.666 52.169 ;
     RECT  95.652 52.051 95.742 52.169 ;
     RECT  98.028 52.015 101.07 52.169 ;
     RECT  95.652 52.169 95.67 52.205 ;
     RECT  94.215 52.051 94.878 52.241 ;
     RECT  40.215 2.413 40.497 52.267 ;
     RECT  3.42 51.395 10.494 52.321 ;
     RECT  11.664 51.089 12.186 52.321 ;
     RECT  34.812 52.141 35.622 52.405 ;
     RECT  40.032 52.267 40.518 52.405 ;
     RECT  24.015 51.935 24.297 52.411 ;
     RECT  39.888 52.405 40.518 52.439 ;
     RECT  34.704 52.405 35.622 52.445 ;
     RECT  39.888 52.439 40.497 52.445 ;
     RECT  94.215 52.241 94.734 52.445 ;
     RECT  2.415 51.665 2.697 52.447 ;
     RECT  23.904 52.411 24.297 52.448 ;
     RECT  98.496 52.169 101.07 52.475 ;
     RECT  40.032 52.445 40.497 52.511 ;
     RECT  2.304 52.447 2.697 52.591 ;
     RECT  3.42 52.321 12.186 52.591 ;
     RECT  100.836 52.475 101.07 52.591 ;
     RECT  102.564 49.469 102.582 52.651 ;
     RECT  102.024 52.651 102.582 52.817 ;
     RECT  12.96 51.089 16.254 52.889 ;
     RECT  98.496 52.475 99.897 53.285 ;
     RECT  97.632 52.939 97.65 53.329 ;
     RECT  98.496 53.285 98.514 53.329 ;
     RECT  99.288 53.285 99.897 53.401 ;
     RECT  100.836 52.591 101.178 53.401 ;
     RECT  99.288 53.401 101.538 53.519 ;
     RECT  97.632 53.329 98.514 53.527 ;
     RECT  99.324 53.519 101.538 53.549 ;
     RECT  95.832 53.635 95.85 53.755 ;
     RECT  26.388 51.781 27.162 53.789 ;
     RECT  95.652 53.755 95.85 53.789 ;
     RECT  97.416 53.527 98.514 53.789 ;
     RECT  18.615 47.597 18.897 53.797 ;
     RECT  95.652 53.789 95.67 53.825 ;
     RECT  96.48 53.869 96.498 53.941 ;
     RECT  97.416 53.789 97.578 53.941 ;
     RECT  96.48 53.941 97.578 54.059 ;
     RECT  2.304 52.591 12.186 54.095 ;
     RECT  96.48 54.059 96.642 54.095 ;
     RECT  99.324 53.549 101.214 54.095 ;
     RECT  26.856 53.789 27.162 54.239 ;
     RECT  97.416 54.059 97.578 54.329 ;
     RECT  99.324 54.095 101.178 54.481 ;
     RECT  99.288 54.481 101.178 54.599 ;
     RECT  98.352 53.789 98.514 54.635 ;
     RECT  103.572 54.679 103.59 54.845 ;
     RECT  2.34 54.095 12.186 55.051 ;
     RECT  97.416 54.329 97.434 55.111 ;
     RECT  2.304 55.051 12.186 55.175 ;
     RECT  98.496 54.635 98.514 55.255 ;
     RECT  12.96 52.889 15.678 55.291 ;
     RECT  94.215 52.445 94.497 55.291 ;
     RECT  97.416 55.111 97.47 55.291 ;
     RECT  94.215 55.291 94.554 55.387 ;
     RECT  95.508 55.255 95.526 55.421 ;
     RECT  99.54 54.599 101.178 55.481 ;
     RECT  96.84 55.291 97.47 55.561 ;
     RECT  98.496 55.255 98.622 55.561 ;
     RECT  99.54 55.481 100.926 55.561 ;
     RECT  96.84 55.561 100.926 55.589 ;
     RECT  96.912 55.589 97.29 55.679 ;
     RECT  94.215 55.387 94.59 55.687 ;
     RECT  95.364 55.561 95.382 55.687 ;
     RECT  94.215 55.687 95.382 55.715 ;
     RECT  94.215 55.715 94.662 55.787 ;
     RECT  2.34 55.175 12.186 55.831 ;
     RECT  12.924 55.291 15.678 55.831 ;
     RECT  96.912 55.679 96.93 55.859 ;
     RECT  2.34 55.831 15.678 55.915 ;
     RECT  2.304 55.915 15.678 55.949 ;
     RECT  27.144 54.239 27.162 55.949 ;
     RECT  2.304 55.949 10.638 55.985 ;
     RECT  25.344 44.923 25.362 56.101 ;
     RECT  98.064 55.589 100.926 56.371 ;
     RECT  11.592 55.949 15.678 56.381 ;
     RECT  98.064 56.371 101.034 56.429 ;
     RECT  98.496 56.429 101.034 56.525 ;
     RECT  18.504 53.797 18.897 56.759 ;
     RECT  18.576 56.759 18.897 56.831 ;
     RECT  102.564 52.817 102.582 56.971 ;
     RECT  11.664 56.381 15.678 57.029 ;
     RECT  98.496 56.525 98.586 57.029 ;
     RECT  102.528 56.971 102.582 57.029 ;
     RECT  96.912 56.911 96.93 57.065 ;
     RECT  2.415 55.985 10.638 57.145 ;
     RECT  11.844 57.029 15.678 57.149 ;
     RECT  94.215 55.787 94.497 57.181 ;
     RECT  95.328 56.911 95.346 57.181 ;
     RECT  98.496 57.029 98.514 57.181 ;
     RECT  2.415 57.145 10.746 57.211 ;
     RECT  99.615 56.525 100.638 57.271 ;
     RECT  12.024 57.149 15.678 57.299 ;
     RECT  2.304 57.211 10.746 57.335 ;
     RECT  98.424 57.181 98.514 57.451 ;
     RECT  94.215 57.181 95.346 57.479 ;
     RECT  95.328 57.479 95.346 57.485 ;
     RECT  97.704 57.451 98.514 57.569 ;
     RECT  2.415 57.335 10.746 57.581 ;
     RECT  96.336 57.451 96.354 57.605 ;
     RECT  99.615 57.271 101.07 57.685 ;
     RECT  99.615 57.685 101.106 57.955 ;
     RECT  2.415 57.581 10.638 58.075 ;
     RECT  99.615 57.955 101.178 58.109 ;
     RECT  96.696 58.117 96.714 58.157 ;
     RECT  97.812 57.569 98.514 58.261 ;
     RECT  25.344 56.101 25.686 58.289 ;
     RECT  94.215 57.479 94.497 58.387 ;
     RECT  2.304 58.075 10.638 58.415 ;
     RECT  2.415 58.415 10.638 58.531 ;
     RECT  97.812 58.261 98.622 58.531 ;
     RECT  97.812 58.531 98.802 58.685 ;
     RECT  99.615 58.109 100.782 59.035 ;
     RECT  94.215 58.387 94.662 59.071 ;
     RECT  97.812 58.685 98.622 59.071 ;
     RECT  102.564 57.029 102.582 59.071 ;
     RECT  97.776 59.071 98.622 59.099 ;
     RECT  102.024 59.071 102.582 59.165 ;
     RECT  94.215 59.071 94.806 59.189 ;
     RECT  97.776 59.099 98.514 59.189 ;
     RECT  95.58 59.071 95.598 59.225 ;
     RECT  2.415 58.531 11.07 59.305 ;
     RECT  12.132 57.299 15.678 59.305 ;
     RECT  2.415 59.305 15.678 59.371 ;
     RECT  99.615 59.035 101.214 59.459 ;
     RECT  2.304 59.371 15.678 59.495 ;
     RECT  99.615 59.459 101.178 59.575 ;
     RECT  99.324 59.575 101.178 59.645 ;
     RECT  97.992 59.189 98.514 59.947 ;
     RECT  102.564 59.165 102.582 59.995 ;
     RECT  97.848 59.947 98.514 59.999 ;
     RECT  2.415 59.495 15.678 60.235 ;
     RECT  28.152 51.629 28.17 60.269 ;
     RECT  102.528 59.995 102.582 60.269 ;
     RECT  94.215 59.189 94.497 60.691 ;
     RECT  25.344 58.289 25.362 60.719 ;
     RECT  94.215 60.691 94.662 60.781 ;
     RECT  94.215 60.781 94.698 60.917 ;
     RECT  94.215 60.917 94.662 60.953 ;
     RECT  98.064 59.999 98.514 60.961 ;
     RECT  99.615 59.645 101.178 60.961 ;
     RECT  96.372 60.925 96.39 60.989 ;
     RECT  97.668 60.961 98.514 61.115 ;
     RECT  99.468 60.961 101.178 61.115 ;
     RECT  102.564 60.269 102.582 61.231 ;
     RECT  102.528 61.231 102.582 61.325 ;
     RECT  99.615 61.115 101.178 61.619 ;
     RECT  2.304 60.235 15.678 61.655 ;
     RECT  99.615 61.619 100.422 61.691 ;
     RECT  101.16 61.619 101.178 61.961 ;
     RECT  94.215 60.953 94.497 62.203 ;
     RECT  2.415 61.655 15.678 62.311 ;
     RECT  98.136 61.115 98.514 62.311 ;
     RECT  99.615 61.691 100.206 62.311 ;
     RECT  2.415 62.311 15.714 62.395 ;
     RECT  98.136 62.311 100.206 62.429 ;
     RECT  2.304 62.395 15.714 62.465 ;
     RECT  97.2 61.579 97.218 62.509 ;
     RECT  97.02 62.509 97.218 62.581 ;
     RECT  98.136 62.429 98.73 62.581 ;
     RECT  96.048 62.545 96.066 62.669 ;
     RECT  99.612 62.429 100.206 62.671 ;
     RECT  94.215 62.203 94.662 62.699 ;
     RECT  97.02 62.581 98.73 62.699 ;
     RECT  99.612 62.671 100.746 62.735 ;
     RECT  19.656 42.961 19.674 62.879 ;
     RECT  0.108 63.247 0.126 63.293 ;
     RECT  99.612 62.735 100.35 63.391 ;
     RECT  101.124 62.851 101.142 63.481 ;
     RECT  97.344 62.699 98.73 63.545 ;
     RECT  99.54 63.391 100.35 63.545 ;
     RECT  97.344 63.545 97.506 63.553 ;
     RECT  99.615 63.545 100.35 63.661 ;
     RECT  101.124 63.481 101.178 63.661 ;
     RECT  2.415 62.465 15.714 63.691 ;
     RECT  2.304 63.691 15.714 63.815 ;
     RECT  96.912 63.553 97.506 63.815 ;
     RECT  98.496 63.545 98.73 63.815 ;
     RECT  96.912 63.815 96.93 64.201 ;
     RECT  96.84 64.201 96.93 64.319 ;
     RECT  95.22 64.357 95.238 64.397 ;
     RECT  2.415 63.815 15.714 64.555 ;
     RECT  2.412 64.555 15.714 64.625 ;
     RECT  98.496 63.815 98.514 64.705 ;
     RECT  98.496 64.705 98.874 64.741 ;
     RECT  99.615 63.661 101.178 64.741 ;
     RECT  102.564 61.325 102.582 64.747 ;
     RECT  51.015 2.413 51.297 64.903 ;
     RECT  98.496 64.741 101.178 65.011 ;
     RECT  0.108 64.939 0.126 65.021 ;
     RECT  96.912 64.319 96.93 65.129 ;
     RECT  97.992 65.011 101.178 65.131 ;
     RECT  102.024 64.747 102.582 65.237 ;
     RECT  96.768 65.272 96.786 65.281 ;
     RECT  97.812 65.131 101.178 65.281 ;
     RECT  34.815 52.445 35.622 65.309 ;
     RECT  96.48 65.281 96.786 65.309 ;
     RECT  97.704 65.281 101.178 65.309 ;
     RECT  98.496 65.309 101.178 65.399 ;
     RECT  97.704 65.309 97.722 65.435 ;
     RECT  2.415 64.625 15.714 65.669 ;
     RECT  98.496 65.399 100.458 65.705 ;
     RECT  2.415 65.669 15.678 65.851 ;
     RECT  51.015 64.903 51.462 65.939 ;
     RECT  96.48 65.309 96.498 65.975 ;
     RECT  51.015 65.939 51.39 65.983 ;
     RECT  50.94 65.983 51.39 66.011 ;
     RECT  50.94 66.011 51.297 66.029 ;
     RECT  97.56 66.019 97.578 66.091 ;
     RECT  97.452 66.091 97.578 66.209 ;
     RECT  97.452 66.209 97.47 66.245 ;
     RECT  99.324 65.705 100.458 66.245 ;
     RECT  99.612 66.245 100.458 66.325 ;
     RECT  99.612 66.325 101.178 66.479 ;
     RECT  98.496 65.705 98.514 66.595 ;
     RECT  20.592 44.887 20.61 66.749 ;
     RECT  99.612 66.479 101.106 66.785 ;
     RECT  24.015 52.448 24.297 66.859 ;
     RECT  102.564 65.237 102.582 66.907 ;
     RECT  98.424 66.595 98.514 66.955 ;
     RECT  24.015 66.859 24.822 66.991 ;
     RECT  24.015 66.991 25.506 67.019 ;
     RECT  97.74 66.955 98.514 67.019 ;
     RECT  2.304 65.851 15.678 67.055 ;
     RECT  25.488 67.019 25.506 67.085 ;
     RECT  97.884 67.019 98.514 67.085 ;
     RECT  98.496 67.085 98.514 67.171 ;
     RECT  99.612 66.785 99.897 67.171 ;
     RECT  102.024 66.907 102.582 67.397 ;
     RECT  100.908 66.785 101.106 67.405 ;
     RECT  94.215 62.699 94.497 67.441 ;
     RECT  16.776 61.159 16.794 67.469 ;
     RECT  94.215 67.441 95.094 67.559 ;
     RECT  100.908 67.405 101.178 67.559 ;
     RECT  2.34 67.055 15.678 67.675 ;
     RECT  95.904 67.603 95.922 67.711 ;
     RECT  94.215 67.559 94.95 67.757 ;
     RECT  98.496 67.171 99.897 67.801 ;
     RECT  100.908 67.559 101.142 67.801 ;
     RECT  94.215 67.757 94.662 67.829 ;
     RECT  95.904 67.711 97.038 67.829 ;
     RECT  98.496 67.801 101.142 67.829 ;
     RECT  96.408 67.829 96.426 67.865 ;
     RECT  2.34 67.675 16.002 68.011 ;
     RECT  98.496 67.829 98.802 68.099 ;
     RECT  2.304 68.011 16.002 68.369 ;
     RECT  2.304 68.369 15.858 68.405 ;
     RECT  99.576 67.829 101.142 68.405 ;
     RECT  99.615 68.405 101.142 68.485 ;
     RECT  99.615 68.485 101.214 68.639 ;
     RECT  2.34 68.405 15.858 68.675 ;
     RECT  96.732 68.635 96.75 68.755 ;
     RECT  97.524 68.791 97.542 68.923 ;
     RECT  96.588 68.755 96.75 68.957 ;
     RECT  102.564 67.397 102.582 69.067 ;
     RECT  2.34 68.675 15.678 69.179 ;
     RECT  95.508 68.971 95.526 69.215 ;
     RECT  2.34 69.179 14.598 69.295 ;
     RECT  97.524 68.923 97.65 69.331 ;
     RECT  97.236 69.331 97.65 69.449 ;
     RECT  101.988 69.067 102.582 69.449 ;
     RECT  96.444 69.331 96.462 69.485 ;
     RECT  99.615 68.639 101.178 69.485 ;
     RECT  94.215 67.829 94.497 69.601 ;
     RECT  98.496 68.099 98.694 69.601 ;
     RECT  99.615 69.485 99.954 69.601 ;
     RECT  94.215 69.601 94.734 69.791 ;
     RECT  94.215 69.791 94.662 69.899 ;
     RECT  97.632 69.449 97.65 70.069 ;
     RECT  98.496 69.601 99.954 70.069 ;
     RECT  100.98 69.485 101.178 70.231 ;
     RECT  2.304 69.295 14.598 70.295 ;
     RECT  102.564 69.449 102.582 70.363 ;
     RECT  97.632 70.069 99.954 70.411 ;
     RECT  100.728 70.231 101.178 70.411 ;
     RECT  97.632 70.411 99.99 70.565 ;
     RECT  100.728 70.411 101.214 70.565 ;
     RECT  102.024 70.363 102.582 70.637 ;
     RECT  97.632 70.565 98.514 70.699 ;
     RECT  15.408 69.179 15.678 70.799 ;
     RECT  96.192 70.375 96.21 70.799 ;
     RECT  2.415 70.295 14.598 70.915 ;
     RECT  15.408 70.799 15.426 70.915 ;
     RECT  94.215 69.899 94.497 70.951 ;
     RECT  97.452 70.699 98.514 70.951 ;
     RECT  99.615 70.565 99.99 70.951 ;
     RECT  100.728 70.565 101.178 70.951 ;
     RECT  2.415 70.915 15.426 71.035 ;
     RECT  97.128 70.951 98.514 71.041 ;
     RECT  94.215 70.951 94.734 71.069 ;
     RECT  96.048 70.915 96.066 71.069 ;
     RECT  99.615 70.951 101.178 71.105 ;
     RECT  2.304 71.035 15.426 71.411 ;
     RECT  16.74 68.521 16.758 71.411 ;
     RECT  97.02 71.041 98.514 71.491 ;
     RECT  99.615 71.105 99.99 71.491 ;
     RECT  2.304 71.411 14.454 71.501 ;
     RECT  94.215 71.069 94.662 71.519 ;
     RECT  100.728 71.105 101.178 71.609 ;
     RECT  2.415 71.501 14.454 71.879 ;
     RECT  101.16 71.609 101.178 71.951 ;
     RECT  97.02 71.491 99.99 72.121 ;
     RECT  97.02 72.121 100.314 72.221 ;
     RECT  2.415 71.879 14.346 72.329 ;
     RECT  2.415 72.329 14.31 72.331 ;
     RECT  97.02 72.221 99.99 72.419 ;
     RECT  97.02 72.419 98.766 72.455 ;
     RECT  21.096 72.157 21.114 72.599 ;
     RECT  96.156 72.571 96.174 72.689 ;
     RECT  96.012 72.841 96.03 72.893 ;
     RECT  97.02 72.455 98.694 72.959 ;
     RECT  97.02 72.959 97.182 72.995 ;
     RECT  99.615 72.419 99.99 72.995 ;
     RECT  2.304 72.331 14.31 73.265 ;
     RECT  101.196 73.111 101.214 73.301 ;
     RECT  102.564 70.637 102.582 73.387 ;
     RECT  20.52 73.111 20.538 73.409 ;
     RECT  97.02 72.995 97.038 73.483 ;
     RECT  96.948 73.483 97.038 73.499 ;
     RECT  98.064 72.959 98.694 73.507 ;
     RECT  99.615 72.995 99.897 73.507 ;
     RECT  96.948 73.499 96.966 73.535 ;
     RECT  100.872 73.381 101.178 73.651 ;
     RECT  0.108 73.507 0.126 73.661 ;
     RECT  100.728 73.651 101.178 73.769 ;
     RECT  102.528 73.387 102.582 73.769 ;
     RECT  98.064 73.507 99.897 73.805 ;
     RECT  101.16 73.769 101.178 73.841 ;
     RECT  98.496 73.805 99.897 73.921 ;
     RECT  2.415 73.265 14.31 74.047 ;
     RECT  98.496 73.921 100.314 74.075 ;
     RECT  95.652 73.849 95.67 74.107 ;
     RECT  95.508 74.107 95.67 74.309 ;
     RECT  95.508 74.309 95.526 74.345 ;
     RECT  97.056 74.425 97.074 74.461 ;
     RECT  2.34 74.047 14.31 74.491 ;
     RECT  96.444 74.461 97.074 74.579 ;
     RECT  96.444 74.579 96.462 74.615 ;
     RECT  15.408 71.411 15.426 74.659 ;
     RECT  2.304 74.491 14.31 74.731 ;
     RECT  15.408 74.659 15.498 74.731 ;
     RECT  98.496 74.075 100.17 74.731 ;
     RECT  98.208 74.731 100.17 74.779 ;
     RECT  2.304 74.731 15.498 74.849 ;
     RECT  98.064 74.779 100.17 75.001 ;
     RECT  98.064 75.001 100.494 75.053 ;
     RECT  98.496 75.053 100.494 75.091 ;
     RECT  102.564 73.769 102.582 75.115 ;
     RECT  98.496 75.091 101.178 75.155 ;
     RECT  99.324 75.155 101.178 75.191 ;
     RECT  99.324 75.191 101.034 75.389 ;
     RECT  102.528 75.115 102.582 75.659 ;
     RECT  2.304 74.849 14.31 75.695 ;
     RECT  2.34 75.695 14.31 75.811 ;
     RECT  15.48 74.849 15.498 75.811 ;
     RECT  94.215 71.519 94.497 75.811 ;
     RECT  98.496 75.155 98.514 75.811 ;
     RECT  97.056 75.811 98.514 75.835 ;
     RECT  2.34 75.811 15.498 75.929 ;
     RECT  96.912 75.835 98.514 75.929 ;
     RECT  96.912 75.929 96.93 75.965 ;
     RECT  94.215 75.811 94.734 76.045 ;
     RECT  97.776 75.929 98.514 76.109 ;
     RECT  99.54 75.389 101.034 76.171 ;
     RECT  96.12 76.081 96.39 76.199 ;
     RECT  99.54 76.171 101.178 76.199 ;
     RECT  96.12 76.199 96.138 76.235 ;
     RECT  97.848 76.109 98.514 76.235 ;
     RECT  101.016 76.199 101.178 76.271 ;
     RECT  94.215 76.045 95.202 76.397 ;
     RECT  2.34 75.929 14.31 76.651 ;
     RECT  98.496 76.235 98.514 76.747 ;
     RECT  2.304 76.651 14.31 76.775 ;
     RECT  99.615 76.199 100.17 77.045 ;
     RECT  94.215 76.397 94.497 77.125 ;
     RECT  101.016 76.271 101.034 77.125 ;
     RECT  98.496 76.747 98.55 77.161 ;
     RECT  99.615 77.045 99.897 77.161 ;
     RECT  101.016 77.125 101.178 77.161 ;
     RECT  94.215 77.125 94.662 77.279 ;
     RECT  98.496 77.161 99.897 77.279 ;
     RECT  98.496 77.279 98.694 77.315 ;
     RECT  98.496 77.315 98.55 77.431 ;
     RECT  100.98 77.161 101.178 77.431 ;
     RECT  2.415 76.775 14.31 77.515 ;
     RECT  2.304 77.515 14.31 77.585 ;
     RECT  98.244 77.431 98.55 77.585 ;
     RECT  102.564 75.659 102.582 77.707 ;
     RECT  99.615 77.279 99.897 77.935 ;
     RECT  100.62 77.431 101.178 77.935 ;
     RECT  102.528 77.707 102.582 77.999 ;
     RECT  95.832 77.521 95.85 78.043 ;
     RECT  15.48 75.929 15.498 78.061 ;
     RECT  102.564 77.999 102.582 78.061 ;
     RECT  95.688 78.043 95.85 78.089 ;
     RECT  102.564 78.061 102.618 78.173 ;
     RECT  98.496 77.585 98.55 78.205 ;
     RECT  94.215 77.279 94.497 78.241 ;
     RECT  97.056 77.161 97.074 78.241 ;
     RECT  98.496 78.205 98.586 78.359 ;
     RECT  99.615 77.935 101.178 78.359 ;
     RECT  2.415 77.585 14.31 78.367 ;
     RECT  96.624 78.241 97.074 78.367 ;
     RECT  98.496 78.359 98.55 78.367 ;
     RECT  96.624 78.367 97.362 78.413 ;
     RECT  98.424 78.367 98.55 78.413 ;
     RECT  98.424 78.413 98.514 78.511 ;
     RECT  99.615 78.359 100.062 78.511 ;
     RECT  94.215 78.241 94.662 78.539 ;
     RECT  96.624 78.413 97.074 78.619 ;
     RECT  15.408 78.061 15.498 78.629 ;
     RECT  96.588 78.619 97.074 78.653 ;
     RECT  15.48 78.629 15.498 78.781 ;
     RECT  16.308 78.601 16.326 78.781 ;
     RECT  2.304 78.367 14.31 78.935 ;
     RECT  2.415 78.935 14.31 79.015 ;
     RECT  15.48 78.781 16.326 79.079 ;
     RECT  98.28 78.511 98.514 79.141 ;
     RECT  99.36 78.511 100.062 79.141 ;
     RECT  101.16 78.359 101.178 79.141 ;
     RECT  40.215 52.511 40.497 79.147 ;
     RECT  98.064 79.141 98.514 79.243 ;
     RECT  99.36 79.141 101.178 79.243 ;
     RECT  0.108 79.177 0.126 79.277 ;
     RECT  34.815 65.309 35.097 79.321 ;
     RECT  15.48 79.079 16.254 79.439 ;
     RECT  34.776 79.321 35.298 79.439 ;
     RECT  98.064 79.243 101.178 79.439 ;
     RECT  15.48 79.439 16.074 79.475 ;
     RECT  98.064 79.439 98.874 79.475 ;
     RECT  102.564 78.173 102.582 79.475 ;
     RECT  39.924 79.147 40.497 79.511 ;
     RECT  41.904 79.321 41.922 79.517 ;
     RECT  96.588 78.653 96.75 79.555 ;
     RECT  99.615 79.439 101.178 79.555 ;
     RECT  2.415 79.015 14.346 79.675 ;
     RECT  96.588 79.555 96.858 79.675 ;
     RECT  95.724 79.675 95.742 79.681 ;
     RECT  2.304 79.675 14.346 79.709 ;
     RECT  96.588 79.675 97.146 79.715 ;
     RECT  95.652 79.681 95.742 79.745 ;
     RECT  34.776 79.439 35.097 79.757 ;
     RECT  96.588 79.715 96.93 79.757 ;
     RECT  95.652 79.745 95.67 79.853 ;
     RECT  94.215 78.539 94.497 79.861 ;
     RECT  102.6 79.753 102.618 79.901 ;
     RECT  99.615 79.555 101.214 79.979 ;
     RECT  96.588 79.757 96.894 80.087 ;
     RECT  2.304 79.709 14.31 80.141 ;
     RECT  96.588 80.087 96.75 80.159 ;
     RECT  17.568 79.591 17.586 80.249 ;
     RECT  98.496 79.475 98.874 80.329 ;
     RECT  99.615 79.979 100.53 80.555 ;
     RECT  2.415 80.141 14.31 80.905 ;
     RECT  98.208 80.329 98.874 80.941 ;
     RECT  99.615 80.555 100.062 80.941 ;
     RECT  96.732 80.159 96.75 80.957 ;
     RECT  17.676 80.329 17.694 80.969 ;
     RECT  2.415 80.905 14.346 80.971 ;
     RECT  94.215 79.861 94.662 81.059 ;
     RECT  94.215 81.059 94.518 81.101 ;
     RECT  98.208 80.941 100.062 81.175 ;
     RECT  102.564 80.221 102.582 81.203 ;
     RECT  2.304 80.971 14.346 81.239 ;
     RECT  97.812 81.175 100.062 81.329 ;
     RECT  96.588 81.175 96.606 81.365 ;
     RECT  100.8 80.761 101.178 81.445 ;
     RECT  99.615 81.329 100.062 81.481 ;
     RECT  100.8 81.445 101.214 81.481 ;
     RECT  98.208 81.329 98.874 81.485 ;
     RECT  102.6 81.481 102.618 81.629 ;
     RECT  99.615 81.481 101.214 81.869 ;
     RECT  2.304 81.239 14.31 81.905 ;
     RECT  15.48 79.475 16.002 82.123 ;
     RECT  2.415 81.905 14.31 82.183 ;
     RECT  15.48 82.123 16.686 82.183 ;
     RECT  17.64 82.183 17.658 82.291 ;
     RECT  2.415 82.183 16.686 82.319 ;
     RECT  2.415 82.319 15.498 82.409 ;
     RECT  17.64 82.291 17.694 82.409 ;
     RECT  97.452 82.255 97.47 82.538 ;
     RECT  98.208 81.485 98.514 82.561 ;
     RECT  99.615 81.869 101.106 82.561 ;
     RECT  15.408 82.409 15.498 82.589 ;
     RECT  96.84 82.538 97.47 82.589 ;
     RECT  16.668 82.319 16.686 82.637 ;
     RECT  17.676 82.409 17.694 82.679 ;
     RECT  98.208 82.561 101.106 82.679 ;
     RECT  98.208 82.679 101.034 82.715 ;
     RECT  96.84 82.589 96.858 82.789 ;
     RECT  96.696 82.789 96.858 82.829 ;
     RECT  98.208 82.715 98.586 82.831 ;
     RECT  103.572 82.561 103.59 82.925 ;
     RECT  94.215 81.101 94.497 83.101 ;
     RECT  2.415 82.409 14.31 83.131 ;
     RECT  94.215 83.101 94.662 83.219 ;
     RECT  97.704 82.831 98.586 83.255 ;
     RECT  97.812 83.255 98.586 83.489 ;
     RECT  2.304 83.131 14.31 83.56 ;
     RECT  15.408 82.589 15.426 83.56 ;
     RECT  2.304 83.56 15.426 83.597 ;
     RECT  99.324 82.715 101.034 83.605 ;
     RECT  15.408 83.597 15.426 83.641 ;
     RECT  96.3 83.641 96.318 83.731 ;
     RECT  98.208 83.489 98.586 83.795 ;
     RECT  98.352 83.795 98.586 83.839 ;
     RECT  99.324 83.605 101.178 83.839 ;
     RECT  15.408 83.641 16.146 84.029 ;
     RECT  2.304 83.597 14.31 84.065 ;
     RECT  98.352 83.839 101.178 84.065 ;
     RECT  95.94 83.731 96.318 84.145 ;
     RECT  2.415 84.065 14.31 84.299 ;
     RECT  95.94 84.145 96.822 84.379 ;
     RECT  0.108 84.343 0.126 84.461 ;
     RECT  94.215 83.219 94.497 84.541 ;
     RECT  16.2 84.181 16.218 84.569 ;
     RECT  98.352 84.065 98.802 84.569 ;
     RECT  95.832 84.379 96.822 84.605 ;
     RECT  98.424 84.569 98.802 84.605 ;
     RECT  94.215 84.541 94.662 84.713 ;
     RECT  95.94 84.605 96.822 84.721 ;
     RECT  102.564 82.027 102.582 84.749 ;
     RECT  2.415 84.299 13.497 84.839 ;
     RECT  95.94 84.721 96.93 84.839 ;
     RECT  2.415 84.839 11.754 84.847 ;
     RECT  96.768 84.839 96.786 84.875 ;
     RECT  99.615 84.065 101.178 84.955 ;
     RECT  102.6 84.883 102.618 85.085 ;
     RECT  99.615 84.955 101.214 85.109 ;
     RECT  2.412 84.847 11.754 85.291 ;
     RECT  98.784 84.605 98.802 85.387 ;
     RECT  2.304 85.291 11.754 85.415 ;
     RECT  17.64 85.351 17.658 85.421 ;
     RECT  18.615 56.831 18.897 85.423 ;
     RECT  97.56 85.339 97.578 85.423 ;
     RECT  18.324 85.423 18.897 85.469 ;
     RECT  97.56 85.423 97.722 85.483 ;
     RECT  98.64 85.387 98.802 85.483 ;
     RECT  97.56 85.483 98.802 85.517 ;
     RECT  94.215 84.713 94.497 85.531 ;
     RECT  99.615 85.109 101.178 85.531 ;
     RECT  98.064 85.517 98.082 85.649 ;
     RECT  12.528 84.839 13.497 85.801 ;
     RECT  14.292 84.299 14.31 85.801 ;
     RECT  94.215 85.531 94.662 85.829 ;
     RECT  99 85.531 101.178 85.955 ;
     RECT  2.415 85.415 11.754 86.155 ;
     RECT  12.528 85.801 14.31 86.189 ;
     RECT  2.412 86.155 11.754 86.225 ;
     RECT  99.615 85.955 101.178 86.261 ;
     RECT  95.94 84.839 95.958 86.305 ;
     RECT  95.508 86.305 95.958 86.341 ;
     RECT  15.408 84.029 15.426 86.459 ;
     RECT  95.508 86.341 96.462 86.495 ;
     RECT  2.415 86.225 11.754 86.587 ;
     RECT  12.528 86.189 13.497 86.587 ;
     RECT  95.508 86.495 95.958 86.621 ;
     RECT  2.415 86.587 13.497 86.729 ;
     RECT  98.604 86.701 98.622 86.837 ;
     RECT  99.615 86.261 101.034 86.845 ;
     RECT  2.415 86.729 10.854 87.007 ;
     RECT  98.964 86.845 101.034 87.115 ;
     RECT  11.736 86.729 13.497 87.151 ;
     RECT  14.292 86.189 14.31 87.151 ;
     RECT  102.564 85.483 102.582 87.151 ;
     RECT  102.564 87.151 102.618 87.245 ;
     RECT  11.736 87.151 14.31 87.277 ;
     RECT  94.215 85.829 94.497 87.277 ;
     RECT  11.736 87.277 14.85 87.377 ;
     RECT  2.304 87.007 10.854 87.781 ;
     RECT  11.736 87.377 14.814 87.781 ;
     RECT  94.215 87.277 94.662 87.781 ;
     RECT  94.215 87.781 94.698 87.917 ;
     RECT  2.304 87.781 14.814 87.953 ;
     RECT  98.964 87.115 101.214 87.961 ;
     RECT  2.415 87.953 14.814 87.989 ;
     RECT  102.564 87.245 102.582 88.075 ;
     RECT  12.06 87.989 14.814 88.079 ;
     RECT  98.928 87.961 101.214 88.115 ;
     RECT  12.06 88.079 14.058 88.151 ;
     RECT  97.38 87.925 97.614 88.151 ;
     RECT  97.56 88.151 97.614 88.159 ;
     RECT  102.024 88.075 102.582 88.159 ;
     RECT  95.94 86.621 95.958 88.195 ;
     RECT  102.024 88.159 102.618 88.259 ;
     RECT  2.415 87.989 11.286 88.349 ;
     RECT  12.456 88.151 14.058 88.349 ;
     RECT  95.94 88.195 96.606 88.349 ;
     RECT  98.532 88.123 98.55 88.349 ;
     RECT  97.56 88.159 97.65 88.363 ;
     RECT  97.56 88.363 98.442 88.385 ;
     RECT  102.564 88.259 102.618 88.541 ;
     RECT  12.708 88.349 14.058 88.619 ;
     RECT  99.615 88.115 101.178 88.619 ;
     RECT  94.215 87.917 94.662 88.727 ;
     RECT  97.596 88.385 98.442 88.889 ;
     RECT  99.615 88.619 101.034 89.041 ;
     RECT  102.564 88.541 102.582 89.311 ;
     RECT  102.024 89.311 102.582 89.405 ;
     RECT  97.596 88.889 98.01 89.429 ;
     RECT  99.288 89.041 101.034 89.581 ;
     RECT  2.415 88.349 10.854 89.611 ;
     RECT  2.304 89.611 10.854 89.671 ;
     RECT  11.664 89.401 11.682 89.671 ;
     RECT  2.304 89.671 11.682 89.735 ;
     RECT  98.892 89.581 101.034 89.735 ;
     RECT  2.415 89.735 11.682 89.851 ;
     RECT  94.215 88.727 94.497 89.851 ;
     RECT  2.415 89.851 12.078 89.879 ;
     RECT  13.215 88.619 14.058 89.879 ;
     RECT  10.944 89.879 12.078 89.969 ;
     RECT  94.215 89.851 95.094 89.981 ;
     RECT  10.944 89.969 11.934 90.029 ;
     RECT  99.576 89.735 101.034 90.085 ;
     RECT  13.215 89.879 13.497 90.121 ;
     RECT  95.94 88.349 95.958 90.121 ;
     RECT  10.944 90.029 11.682 90.239 ;
     RECT  95.94 90.121 96.462 90.239 ;
     RECT  99.576 90.085 101.214 90.239 ;
     RECT  95.94 90.239 96.282 90.275 ;
     RECT  98.604 89.941 98.658 90.413 ;
     RECT  94.215 89.981 94.662 90.419 ;
     RECT  2.415 89.879 10.134 90.475 ;
     RECT  99.576 90.239 100.746 90.509 ;
     RECT  2.304 90.475 10.134 90.545 ;
     RECT  95.94 90.275 95.958 90.619 ;
     RECT  10.944 90.239 10.962 90.653 ;
     RECT  98.208 90.625 98.226 90.715 ;
     RECT  2.415 90.545 10.134 90.859 ;
     RECT  10.872 90.661 10.89 90.859 ;
     RECT  99.576 90.509 100.71 90.931 ;
     RECT  2.415 90.859 10.89 91.049 ;
     RECT  12.852 90.121 13.497 91.049 ;
     RECT  95.652 90.619 95.958 91.085 ;
     RECT  99.324 90.931 100.71 91.085 ;
     RECT  13.032 91.049 13.497 91.165 ;
     RECT  98.064 90.715 98.226 91.165 ;
     RECT  2.415 91.049 10.746 91.229 ;
     RECT  13.032 91.165 13.806 91.319 ;
     RECT  98.064 91.165 98.586 91.319 ;
     RECT  99.615 91.085 100.71 91.435 ;
     RECT  95.724 91.085 95.958 91.469 ;
     RECT  95.94 91.469 95.958 91.471 ;
     RECT  96.912 91.165 96.93 91.471 ;
     RECT  99.615 91.435 101.07 91.471 ;
     RECT  102.564 89.405 102.582 91.471 ;
     RECT  102.024 91.471 102.582 91.565 ;
     RECT  102.528 91.565 102.582 91.589 ;
     RECT  94.215 90.419 94.497 91.597 ;
     RECT  95.94 91.471 96.93 91.625 ;
     RECT  99.615 91.471 101.142 91.625 ;
     RECT  94.215 91.597 94.662 91.697 ;
     RECT  2.415 91.229 10.134 91.771 ;
     RECT  96.732 91.625 96.93 91.859 ;
     RECT  27.9 60.385 27.918 91.867 ;
     RECT  98.064 91.319 98.118 91.867 ;
     RECT  13.032 91.319 13.497 91.931 ;
     RECT  96.912 91.859 96.93 91.931 ;
     RECT  27.468 91.867 27.918 91.975 ;
     RECT  97.992 91.867 98.118 92.003 ;
     RECT  99.615 91.625 100.746 92.011 ;
     RECT  27.288 91.975 27.918 92.371 ;
     RECT  102.528 91.589 102.546 92.395 ;
     RECT  98.064 92.003 98.118 92.399 ;
     RECT  2.304 91.771 10.134 92.407 ;
     RECT  14.76 92.371 14.778 92.407 ;
     RECT  26.784 92.371 27.918 92.471 ;
     RECT  98.064 92.399 98.082 92.471 ;
     RECT  29.415 51.629 29.697 92.479 ;
     RECT  2.304 92.407 10.782 92.507 ;
     RECT  14.724 92.407 14.778 92.507 ;
     RECT  95.94 91.625 95.958 92.515 ;
     RECT  95.544 92.515 95.958 92.551 ;
     RECT  99.216 92.011 100.746 92.551 ;
     RECT  14.724 92.507 14.742 92.579 ;
     RECT  53.424 83.767 53.442 92.641 ;
     RECT  27.288 92.471 27.918 92.669 ;
     RECT  53.028 92.641 53.442 92.669 ;
     RECT  95.544 92.551 96.138 92.677 ;
     RECT  2.304 92.507 10.134 92.705 ;
     RECT  28.692 92.479 29.697 92.705 ;
     RECT  95.4 92.677 96.138 92.705 ;
     RECT  98.892 92.551 100.962 92.705 ;
     RECT  27.288 92.669 27.738 92.717 ;
     RECT  95.4 92.705 95.958 92.717 ;
     RECT  95.94 92.717 95.958 92.741 ;
     RECT  99.615 92.705 100.962 92.821 ;
     RECT  102.024 92.395 102.546 92.827 ;
     RECT  99.615 92.821 101.214 92.975 ;
     RECT  100.908 92.975 101.214 93.245 ;
     RECT  102.024 92.827 102.582 93.389 ;
     RECT  102.564 93.389 102.582 93.479 ;
     RECT  101.16 93.245 101.178 93.515 ;
     RECT  2.415 92.705 10.134 93.931 ;
     RECT  2.304 93.931 10.134 94.055 ;
     RECT  0.108 95.107 0.126 95.261 ;
     RECT  2.415 94.055 10.134 95.647 ;
     RECT  2.304 95.647 10.134 96.215 ;
     RECT  2.415 96.215 10.134 96.955 ;
     RECT  2.304 96.955 10.134 97.025 ;
     RECT  2.415 97.025 10.134 97.807 ;
     RECT  2.304 97.807 10.134 99.581 ;
     RECT  2.415 99.581 10.134 100.411 ;
     RECT  2.304 100.411 10.134 100.535 ;
     RECT  2.34 100.535 10.134 101.275 ;
     RECT  2.304 101.275 10.134 101.345 ;
     RECT  2.415 101.345 10.134 102.571 ;
     RECT  2.304 102.571 10.134 103.901 ;
     RECT  0.108 104.287 0.126 104.333 ;
     RECT  2.415 103.901 10.134 104.731 ;
     RECT  2.304 104.731 10.134 104.855 ;
     RECT  2.415 104.855 10.134 105.595 ;
     RECT  2.412 105.595 10.134 105.665 ;
     RECT  0.108 105.907 0.126 106.061 ;
     RECT  2.415 105.665 10.134 106.447 ;
     RECT  2.412 106.447 10.134 106.891 ;
     RECT  2.304 106.891 10.134 107.015 ;
     RECT  2.415 107.015 10.134 107.755 ;
     RECT  2.304 107.755 10.134 107.825 ;
     RECT  73.62 108.283 73.638 108.329 ;
     RECT  75.168 108.301 75.186 108.331 ;
     RECT  74.808 108.331 75.186 108.365 ;
     RECT  74.808 108.365 74.826 108.599 ;
     RECT  2.415 107.825 10.134 108.869 ;
     RECT  2.415 108.869 9.306 109.051 ;
     RECT  0.108 109.417 0.126 109.517 ;
     RECT  2.304 109.051 9.306 109.985 ;
     RECT  2.412 109.985 9.306 110.381 ;
     RECT  10.116 108.869 10.134 110.489 ;
     RECT  2.415 110.381 9.306 111.211 ;
     RECT  2.304 111.211 9.306 111.299 ;
     RECT  2.304 111.299 8.838 111.875 ;
     RECT  2.304 111.875 2.826 112.145 ;
     RECT  2.415 112.145 2.826 112.801 ;
     RECT  3.636 111.875 8.838 112.801 ;
     RECT  2.415 112.801 8.838 112.927 ;
     RECT  2.304 112.927 8.838 113.459 ;
     RECT  2.304 113.459 2.97 113.495 ;
     RECT  2.304 113.495 2.697 113.873 ;
     RECT  0.108 114.547 0.126 114.701 ;
     RECT  2.415 113.873 2.697 114.811 ;
     RECT  3.78 113.459 8.838 114.811 ;
     RECT  2.415 114.811 8.838 115.079 ;
     RECT  5.832 115.079 8.838 115.349 ;
     RECT  2.415 115.079 5.058 115.385 ;
     RECT  2.415 115.385 2.697 115.531 ;
     RECT  2.304 115.531 2.697 116.107 ;
     RECT  3.528 115.385 5.058 116.107 ;
     RECT  2.304 116.107 5.058 116.159 ;
     RECT  3.42 116.159 5.058 116.231 ;
     RECT  2.304 116.159 2.697 116.861 ;
     RECT  3.42 116.231 4.086 117.005 ;
     RECT  5.04 116.231 5.058 117.121 ;
     RECT  5.832 115.349 8.097 117.121 ;
     RECT  4.968 117.121 8.097 117.239 ;
     RECT  3.492 117.005 4.086 117.275 ;
     RECT  3.6 117.275 4.086 117.355 ;
     RECT  4.968 117.239 4.986 117.437 ;
     RECT  3.6 117.355 4.194 117.661 ;
     RECT  2.412 116.861 2.697 117.691 ;
     RECT  2.304 117.691 2.697 117.815 ;
     RECT  3.6 117.661 4.518 117.815 ;
     RECT  3.6 117.815 4.41 118.129 ;
     RECT  2.415 117.815 2.697 118.201 ;
     RECT  3.42 118.129 4.41 118.201 ;
     RECT  5.832 117.239 8.097 118.201 ;
     RECT  2.415 118.201 4.41 118.555 ;
     RECT  2.304 118.555 4.41 118.625 ;
     RECT  5.4 118.201 8.097 118.633 ;
     RECT  2.415 118.625 4.41 118.669 ;
     RECT  5.328 118.633 8.097 118.669 ;
     RECT  2.415 118.669 8.097 118.741 ;
     RECT  8.82 115.349 8.838 118.741 ;
     RECT  2.415 118.741 8.838 119.021 ;
     RECT  3.42 119.021 8.838 119.137 ;
     RECT  3.42 119.137 9.054 119.245 ;
     RECT  27.288 92.717 27.306 119.309 ;
     RECT  2.415 119.021 2.697 119.407 ;
     RECT  2.412 119.407 2.697 119.453 ;
     RECT  3.42 119.245 9.126 119.507 ;
     RECT  3.42 119.507 8.946 119.669 ;
     RECT  2.415 119.453 2.697 119.821 ;
     RECT  3.42 119.669 8.097 119.821 ;
     RECT  2.415 119.821 8.097 119.939 ;
     RECT  2.415 119.939 6.786 120.209 ;
     RECT  0.108 119.677 0.126 120.317 ;
     RECT  5.58 120.209 6.786 120.515 ;
     RECT  5.832 120.515 6.786 120.623 ;
     RECT  2.415 120.209 4.806 120.715 ;
     RECT  2.304 120.715 4.806 120.785 ;
     RECT  53.028 92.669 53.046 120.991 ;
     RECT  5.868 120.623 6.786 121.019 ;
     RECT  5.868 121.019 6.39 121.181 ;
     RECT  53.028 120.991 53.406 121.199 ;
     RECT  2.415 120.785 3.762 121.289 ;
     RECT  6.012 121.181 6.39 121.289 ;
     RECT  2.415 121.289 3.51 121.567 ;
     RECT  6.372 121.289 6.39 121.829 ;
     RECT  4.716 120.785 4.806 121.945 ;
     RECT  4.356 121.945 4.806 121.981 ;
     RECT  4.356 121.981 4.914 122.099 ;
     RECT  2.304 121.567 3.51 122.135 ;
     RECT  4.356 122.099 4.374 122.135 ;
     RECT  3.492 122.135 3.51 122.207 ;
     RECT  53.388 121.199 53.406 122.909 ;
     RECT  53.316 123.025 53.334 124.069 ;
     RECT  52.74 124.069 53.334 124.141 ;
     RECT  52.452 124.141 53.334 124.259 ;
     RECT  52.452 124.259 52.83 124.267 ;
     RECT  52.02 124.267 52.83 124.445 ;
     RECT  52.236 124.445 52.83 125.069 ;
     RECT  52.236 125.069 52.686 125.311 ;
     RECT  51.015 66.029 51.297 125.347 ;
     RECT  52.164 125.311 52.686 125.347 ;
     RECT  51.015 125.347 52.686 125.879 ;
     RECT  51.015 125.879 52.362 125.987 ;
     RECT  51.015 125.987 52.254 126.023 ;
     RECT  51.015 126.023 52.218 126.419 ;
     RECT  52.056 126.419 52.218 126.841 ;
     RECT  52.056 126.841 52.254 127.075 ;
     RECT  52.056 127.075 52.326 127.085 ;
     RECT  2.415 122.135 2.697 127.187 ;
     RECT  7.815 119.939 8.097 127.187 ;
     RECT  13.215 91.931 13.497 127.187 ;
     RECT  18.615 85.469 18.897 127.187 ;
     RECT  24.015 67.019 24.297 127.187 ;
     RECT  29.415 92.705 29.697 127.187 ;
     RECT  34.815 79.757 35.097 127.187 ;
     RECT  40.215 79.511 40.497 127.187 ;
     RECT  45.615 47.597 45.897 127.187 ;
     RECT  51.015 126.419 51.297 127.187 ;
     RECT  56.415 47.597 56.697 127.187 ;
     RECT  61.815 2.413 62.097 127.187 ;
     RECT  67.215 47.597 67.497 127.187 ;
     RECT  72.615 2.413 72.897 127.187 ;
     RECT  78.015 47.597 78.297 127.187 ;
     RECT  83.415 2.413 83.697 127.187 ;
     RECT  88.815 47.597 89.097 127.187 ;
     RECT  94.215 91.697 94.497 127.187 ;
     RECT  99.615 92.975 99.897 127.187 ;
     RECT  52.236 127.085 52.326 127.229 ;
     RECT  52.236 127.229 52.254 127.265 ;
     RECT  2.415 127.187 2.505 127.457 ;
     RECT  7.815 127.187 7.905 127.457 ;
     RECT  13.215 127.187 13.305 127.457 ;
     RECT  18.615 127.187 18.705 127.457 ;
     RECT  24.015 127.187 24.105 127.457 ;
     RECT  29.415 127.187 29.505 127.457 ;
     RECT  34.815 127.187 34.905 127.457 ;
     RECT  40.215 127.187 40.305 127.457 ;
     RECT  45.615 127.187 45.705 127.457 ;
     RECT  51.015 127.187 51.105 127.457 ;
     RECT  56.415 127.187 56.505 127.457 ;
     RECT  61.815 127.187 61.905 127.457 ;
     RECT  67.215 127.187 67.305 127.457 ;
     RECT  72.615 127.187 72.705 127.457 ;
     RECT  78.015 127.187 78.105 127.457 ;
     RECT  83.415 127.187 83.505 127.457 ;
     RECT  88.815 127.187 88.905 127.457 ;
     RECT  94.215 127.187 94.305 127.457 ;
     RECT  99.615 127.187 99.705 127.457 ;
    LAYER M4 ;
     RECT  0.06 7.536 0.137 122.04 ;
     RECT  0.137 8.4 2.408 119.448 ;
     RECT  0.137 120.72 2.408 122.04 ;
     RECT  2.408 2.148 2.512 127.452 ;
     RECT  2.512 2.418 2.704 127.182 ;
     RECT  2.704 17.472 2.765 20.088 ;
     RECT  2.704 38.688 2.765 39.528 ;
     RECT  2.704 82.032 2.765 82.728 ;
     RECT  2.704 114.816 2.765 115.128 ;
     RECT  2.704 11.376 2.801 14.28 ;
     RECT  2.704 28.704 2.801 30.216 ;
     RECT  2.704 47.712 2.801 47.88 ;
     RECT  2.704 59.808 2.801 59.832 ;
     RECT  2.704 85.104 2.801 87 ;
     RECT  2.704 90.048 2.801 91.368 ;
     RECT  2.704 107.184 2.801 108.888 ;
     RECT  2.801 108.864 2.819 108.888 ;
     RECT  2.801 12.912 2.837 14.28 ;
     RECT  2.704 15.312 2.837 16.008 ;
     RECT  2.765 17.472 2.837 18.792 ;
     RECT  2.765 19.92 2.837 20.088 ;
     RECT  2.704 34.752 2.837 35.352 ;
     RECT  2.765 38.688 2.837 39.096 ;
     RECT  2.704 65.424 2.837 65.448 ;
     RECT  2.801 90.624 2.837 91.368 ;
     RECT  2.704 95.184 2.837 95.208 ;
     RECT  2.704 98.88 2.837 102.408 ;
     RECT  2.801 107.184 2.837 107.736 ;
     RECT  2.704 110.784 2.837 112.536 ;
     RECT  2.704 118.992 2.837 119.016 ;
     RECT  2.837 107.184 2.867 107.208 ;
     RECT  2.837 111.072 2.867 112.344 ;
     RECT  2.704 54.144 3.089 56.376 ;
     RECT  2.704 66.672 3.089 74.568 ;
     RECT  2.704 40.704 3.155 43.944 ;
     RECT  3.089 54.144 3.155 55.992 ;
     RECT  2.837 14.112 3.197 14.28 ;
     RECT  2.704 52.992 3.197 53.016 ;
     RECT  3.197 14.256 3.305 14.28 ;
     RECT  3.155 40.704 3.305 42.984 ;
     RECT  2.704 50.736 3.305 51.336 ;
     RECT  2.837 12.912 3.34 13.08 ;
     RECT  2.837 19.92 3.34 19.944 ;
     RECT  2.704 116.112 3.395 116.712 ;
     RECT  2.704 76.896 3.443 76.92 ;
     RECT  2.837 102.384 3.443 102.408 ;
     RECT  2.704 93.504 3.449 94.056 ;
     RECT  2.704 121.296 3.449 121.32 ;
     RECT  2.837 100.848 3.484 101.112 ;
     RECT  2.704 75.648 3.485 75.816 ;
     RECT  3.089 67.008 3.521 74.568 ;
     RECT  2.704 60.96 3.557 61.08 ;
     RECT  2.765 82.032 3.673 82.104 ;
     RECT  2.704 26.688 3.685 26.712 ;
     RECT  2.704 80.448 3.685 80.472 ;
     RECT  2.704 106.032 3.697 106.056 ;
     RECT  2.837 98.88 3.737 99.576 ;
     RECT  3.697 106.032 3.737 106.2 ;
     RECT  2.704 58.56 3.769 58.584 ;
     RECT  2.704 62.592 3.769 64.2 ;
     RECT  3.557 61.008 3.773 61.08 ;
     RECT  3.737 98.88 3.779 98.904 ;
     RECT  3.769 62.592 3.781 64.344 ;
     RECT  2.704 77.904 3.841 78.12 ;
     RECT  2.704 23.328 3.845 23.88 ;
     RECT  2.704 25.008 3.877 25.032 ;
     RECT  2.704 104.256 3.877 104.28 ;
     RECT  2.837 18.192 3.917 18.792 ;
     RECT  3.836 103.104 3.923 103.128 ;
     RECT  3.877 104.256 3.923 104.808 ;
     RECT  3.305 51.312 3.949 51.336 ;
     RECT  3.769 52.464 3.949 52.488 ;
     RECT  3.781 62.16 3.953 64.344 ;
     RECT  3.395 116.688 3.953 116.712 ;
     RECT  3.877 25.008 3.985 25.08 ;
     RECT  3.449 94.032 4.019 94.056 ;
     RECT  2.801 85.104 4.021 85.944 ;
     RECT  2.801 86.976 4.021 87 ;
     RECT  3.98 44.784 4.067 44.808 ;
     RECT  2.837 15.984 4.093 16.008 ;
     RECT  3.685 80.4 4.093 80.472 ;
     RECT  3.917 18.72 4.097 18.792 ;
     RECT  2.704 83.808 4.117 83.832 ;
     RECT  4.021 85.104 4.117 87.768 ;
     RECT  2.801 28.704 4.124 28.872 ;
     RECT  3.953 62.208 4.129 64.344 ;
     RECT  4.129 62.208 4.133 64.728 ;
     RECT  2.704 31.92 4.157 32.472 ;
     RECT  3.685 26.688 4.165 26.76 ;
     RECT  3.484 101.088 4.165 101.112 ;
     RECT  2.704 21.408 4.201 21.432 ;
     RECT  2.704 33.504 4.201 33.528 ;
     RECT  4.133 63.216 4.201 64.728 ;
     RECT  2.704 7.872 4.205 7.896 ;
     RECT  4.117 83.808 4.205 87.768 ;
     RECT  4.165 101.088 4.205 101.496 ;
     RECT  3.985 25.008 4.211 25.656 ;
     RECT  4.165 26.688 4.211 26.952 ;
     RECT  4.124 28.704 4.211 28.968 ;
     RECT  3.521 74.544 4.237 74.568 ;
     RECT  3.34 13.056 4.241 13.08 ;
     RECT  3.845 23.328 4.241 23.832 ;
     RECT  4.211 25.008 4.241 25.08 ;
     RECT  2.801 30.192 4.241 30.216 ;
     RECT  4.157 31.872 4.241 32.472 ;
     RECT  3.305 42.96 4.241 42.984 ;
     RECT  2.837 90.624 4.241 91.176 ;
     RECT  3.949 51.312 4.277 52.488 ;
     RECT  3.521 67.008 4.277 73.512 ;
     RECT  4.205 85.104 4.301 87.768 ;
     RECT  4.201 33.504 4.355 33.576 ;
     RECT  3.769 57.6 4.357 58.584 ;
     RECT  4.201 63.216 4.385 64.824 ;
     RECT  4.301 85.104 4.385 87.816 ;
     RECT  3.155 54.144 4.44 55.56 ;
     RECT  4.357 56.976 4.44 58.584 ;
     RECT  4.201 21.408 4.451 21.576 ;
     RECT  4.237 74.544 4.451 74.712 ;
     RECT  3.305 41.664 4.457 41.688 ;
     RECT  3.98 59.616 4.481 59.64 ;
     RECT  4.277 70.464 4.493 73.512 ;
     RECT  4.093 80.4 4.493 81.432 ;
     RECT  4.385 85.104 4.493 87 ;
     RECT  4.385 63.792 4.499 64.824 ;
     RECT  2.704 46.128 4.501 46.152 ;
     RECT  4.44 54.144 4.501 58.584 ;
     RECT  4.481 59.616 4.501 59.88 ;
     RECT  4.46 96.288 4.501 96.312 ;
     RECT  2.704 49.344 4.525 49.368 ;
     RECT  3.773 61.008 4.525 61.032 ;
     RECT  2.704 79.248 4.525 79.272 ;
     RECT  2.704 97.68 4.525 97.704 ;
     RECT  4.501 96.288 4.547 96.648 ;
     RECT  2.837 35.328 4.549 35.352 ;
     RECT  3.737 106.176 4.549 106.2 ;
     RECT  4.525 49.008 4.565 49.368 ;
     RECT  4.501 54.144 4.565 59.88 ;
     RECT  4.525 60.912 4.565 61.032 ;
     RECT  4.499 63.84 4.565 64.344 ;
     RECT  4.493 81.408 4.565 81.432 ;
     RECT  4.525 97.68 4.565 98.616 ;
     RECT  2.765 114.816 4.565 114.84 ;
     RECT  4.501 46.128 4.588 46.776 ;
     RECT  4.549 34.8 4.595 35.352 ;
     RECT  2.837 38.688 4.597 38.712 ;
     RECT  4.549 106.176 4.636 106.92 ;
     RECT  4.493 85.92 4.637 86.664 ;
     RECT  4.597 38.208 4.643 38.712 ;
     RECT  4.636 106.176 4.643 106.44 ;
     RECT  4.277 67.008 4.645 69.384 ;
     RECT  4.451 74.544 4.645 74.568 ;
     RECT  4.597 114 4.669 114.552 ;
     RECT  4.565 54.144 4.709 56.52 ;
     RECT  4.565 57.6 4.709 59.256 ;
     RECT  4.645 66.72 4.709 69.384 ;
     RECT  3.985 108.288 4.741 108.312 ;
     RECT  4.097 18.768 4.769 18.792 ;
     RECT  3.485 75.792 4.769 75.816 ;
     RECT  3.841 76.944 4.769 78.12 ;
     RECT  4.165 82.608 4.777 82.632 ;
     RECT  4.705 120.288 4.777 120.312 ;
     RECT  4.741 108.288 4.781 108.792 ;
     RECT  4.769 18.768 4.796 18.888 ;
     RECT  4.241 23.808 4.835 23.832 ;
     RECT  4.709 54.144 4.837 54.168 ;
     RECT  4.241 91.152 4.844 91.176 ;
     RECT  3.973 92.544 4.844 93 ;
     RECT  4.525 79.248 4.849 79.368 ;
     RECT  4.777 82.608 4.849 82.68 ;
     RECT  4.205 83.808 4.849 83.832 ;
     RECT  4.769 75.792 4.853 78.12 ;
     RECT  2.801 11.376 4.861 11.4 ;
     RECT  4.796 18.768 4.883 19.176 ;
     RECT  4.241 25.008 4.885 25.032 ;
     RECT  4.849 79.152 4.885 79.368 ;
     RECT  4.853 76.944 4.897 78.12 ;
     RECT  4.597 39.888 4.921 39.912 ;
     RECT  4.493 70.464 4.925 71.352 ;
     RECT  4.885 24.48 4.931 25.032 ;
     RECT  4.211 26.736 4.931 26.952 ;
     RECT  4.844 91.152 4.931 93 ;
     RECT  4.565 98.064 4.931 98.616 ;
     RECT  4.669 113.184 4.931 114.552 ;
     RECT  4.777 119.472 4.931 121.176 ;
     RECT  3.985 17.088 4.961 17.112 ;
     RECT  4.093 15.312 4.997 16.008 ;
     RECT  4.897 77.52 5.029 78.12 ;
     RECT  4.885 79.152 5.029 79.752 ;
     RECT  4.849 82.608 5.029 83.832 ;
     RECT  4.997 15.36 5.069 15.912 ;
     RECT  4.565 63.84 5.069 64.2 ;
     RECT  4.709 66.72 5.069 66.744 ;
     RECT  2.704 9.648 5.077 9.672 ;
     RECT  5.021 29.04 5.105 29.064 ;
     RECT  4.931 91.152 5.105 91.176 ;
     RECT  4.547 96.624 5.105 96.648 ;
     RECT  5.029 82.08 5.113 83.832 ;
     RECT  5.077 8.832 5.123 9.672 ;
     RECT  4.921 39.888 5.123 41.016 ;
     RECT  2.801 47.856 5.132 47.88 ;
     RECT  4.565 49.008 5.132 49.032 ;
     RECT  3.923 104.784 5.132 104.808 ;
     RECT  5.123 40.464 5.141 41.016 ;
     RECT  4.205 101.472 5.141 101.496 ;
     RECT  5.057 110.544 5.141 110.568 ;
     RECT  4.277 51.888 5.173 52.488 ;
     RECT  5.132 47.856 5.177 49.032 ;
     RECT  5.029 77.52 5.177 79.752 ;
     RECT  5.132 104.784 5.219 105.048 ;
     RECT  4.931 113.184 5.219 114.264 ;
     RECT  4.525 31.104 5.221 31.128 ;
     RECT  5.173 51.888 5.249 53.064 ;
     RECT  5.219 113.712 5.285 114.264 ;
     RECT  5.141 40.464 5.315 40.824 ;
     RECT  4.355 33.504 5.349 33.528 ;
     RECT  4.709 68.304 5.353 69.384 ;
     RECT  5.113 82.656 5.353 83.832 ;
     RECT  3.769 89.136 5.353 89.16 ;
     RECT  5.065 12.528 5.363 12.552 ;
     RECT  5.249 53.04 5.365 53.064 ;
     RECT  4.837 54.096 5.365 54.168 ;
     RECT  5.123 8.832 5.393 8.856 ;
     RECT  5.317 13.536 5.404 14.376 ;
     RECT  5.317 18.576 5.404 18.6 ;
     RECT  5.365 53.04 5.411 54.168 ;
     RECT  4.133 62.208 5.425 62.232 ;
     RECT  4.931 98.064 5.429 98.232 ;
     RECT  4.925 70.704 5.461 71.352 ;
     RECT  4.493 72.384 5.461 72.984 ;
     RECT  5.249 51.888 5.465 51.912 ;
     RECT  5.429 98.208 5.465 98.232 ;
     RECT  5.209 66 5.497 66.36 ;
     RECT  4.645 74.064 5.497 74.568 ;
     RECT  4.853 75.792 5.497 75.816 ;
     RECT  5.221 31.008 5.501 31.128 ;
     RECT  4.241 32.448 5.501 32.472 ;
     RECT  4.709 55.2 5.501 56.52 ;
     RECT  5.353 68.304 5.501 69.624 ;
     RECT  4.637 86.208 5.501 86.664 ;
     RECT  5.177 77.664 5.533 79.752 ;
     RECT  5.425 62.208 5.569 62.424 ;
     RECT  5.497 65.184 5.603 66.36 ;
     RECT  5.569 62.16 5.653 62.424 ;
     RECT  5.461 70.704 5.677 72.984 ;
     RECT  5.497 74.064 5.677 75.816 ;
     RECT  5.353 82.656 5.677 84.6 ;
     RECT  5.353 89.136 5.677 89.4 ;
     RECT  4.709 57.6 5.681 58.728 ;
     RECT  5.177 48.288 5.699 49.032 ;
     RECT  5.603 65.184 5.717 66.168 ;
     RECT  4.501 20.208 5.747 20.232 ;
     RECT  5.501 86.208 5.753 86.616 ;
     RECT  4.643 106.176 5.753 106.2 ;
     RECT  4.595 34.8 5.756 34.824 ;
     RECT  5.677 89.136 5.777 89.496 ;
     RECT  5.677 70.704 5.789 75.816 ;
     RECT  5.777 88.848 5.804 89.496 ;
     RECT  5.425 27.312 5.836 27.912 ;
     RECT  5.756 33.984 5.843 34.824 ;
     RECT  5.804 88.848 5.845 89.688 ;
     RECT  5.501 56.496 5.857 56.52 ;
     RECT  5.653 62.16 5.857 62.472 ;
     RECT  5.789 70.704 5.891 71.832 ;
     RECT  5.845 88.224 5.891 89.688 ;
     RECT  4.931 24.48 5.893 24.504 ;
     RECT  4.931 92.976 5.893 93 ;
     RECT  5.501 55.2 5.897 55.464 ;
     RECT  5.857 56.496 5.897 57 ;
     RECT  5.219 105.024 5.897 105.048 ;
     RECT  5.285 114.24 5.897 114.264 ;
     RECT  4.931 121.152 5.897 121.176 ;
     RECT  5.677 82.656 5.965 84.888 ;
     RECT  5.891 71.04 5.969 71.832 ;
     RECT  4.451 21.408 5.989 21.432 ;
     RECT  5.411 53.472 6.001 54.168 ;
     RECT  5.897 55.2 6.001 55.224 ;
     RECT  5.753 86.208 6.005 86.232 ;
     RECT  5.857 62.16 6.037 62.856 ;
     RECT  5.069 64.032 6.037 64.2 ;
     RECT  5.893 24.384 6.041 24.504 ;
     RECT  5.065 10.992 6.073 11.016 ;
     RECT  5.989 21.024 6.076 21.432 ;
     RECT  6.073 10.992 6.113 11.4 ;
     RECT  5.965 82.656 6.113 84.984 ;
     RECT  5.891 89.376 6.149 89.496 ;
     RECT  6.085 116.016 6.172 116.04 ;
     RECT  4.957 117.408 6.177 117.432 ;
     RECT  5.533 77.664 6.179 80.424 ;
     RECT  5.843 34.752 6.181 34.824 ;
     RECT  6.179 77.664 6.185 80.376 ;
     RECT  5.039 22.656 6.217 22.68 ;
     RECT  6.037 62.16 6.217 64.2 ;
     RECT  6.217 62.16 6.257 65.016 ;
     RECT  5.789 72.816 6.257 75.816 ;
     RECT  6.037 94.944 6.275 94.968 ;
     RECT  6.037 43.728 6.277 43.752 ;
     RECT  5.315 40.464 6.293 40.488 ;
     RECT  4.781 108.768 6.293 108.792 ;
     RECT  6.277 43.152 6.323 43.752 ;
     RECT  5.404 13.584 6.371 14.376 ;
     RECT  2.867 111.552 6.38 111.576 ;
     RECT  5.897 56.976 6.401 57 ;
     RECT  6.257 62.448 6.401 65.016 ;
     RECT  4.643 38.208 6.437 38.232 ;
     RECT  5.969 71.328 6.437 71.832 ;
     RECT  6.257 72.816 6.437 73.224 ;
     RECT  6.185 79.152 6.437 80.376 ;
     RECT  6.253 110.496 6.467 110.52 ;
     RECT  6.38 111.552 6.467 112.392 ;
     RECT  5.893 92.928 6.473 93 ;
     RECT  5.641 51.792 6.505 51.816 ;
     RECT  6.001 53.472 6.505 55.224 ;
     RECT  6.257 74.352 6.505 75.816 ;
     RECT  6.401 62.448 6.515 64.392 ;
     RECT  5.821 26.208 6.517 26.232 ;
     RECT  6.437 73.2 6.545 73.224 ;
     RECT  6.253 42.144 6.563 42.168 ;
     RECT  4.565 60.912 6.577 60.936 ;
     RECT  6.469 18.768 6.611 18.792 ;
     RECT  5.501 68.352 6.613 69.624 ;
     RECT  5.135 103.392 6.617 103.416 ;
     RECT  5.891 88.224 6.649 88.248 ;
     RECT  6.517 26.208 6.653 26.568 ;
     RECT  5.681 58.56 6.685 58.584 ;
     RECT  6.437 79.248 6.689 80.376 ;
     RECT  6.181 34.752 6.707 35.064 ;
     RECT  6.685 58.56 6.725 58.728 ;
     RECT  6.505 74.352 6.725 76.392 ;
     RECT  6.649 87.792 6.733 88.248 ;
     RECT  5.717 66 6.757 66.168 ;
     RECT  6.613 68.16 6.757 69.624 ;
     RECT  6.371 14.352 6.761 14.376 ;
     RECT  5.713 17.52 6.793 17.544 ;
     RECT  6.323 43.152 6.797 43.176 ;
     RECT  6.685 81.408 6.797 81.432 ;
     RECT  6.001 12.384 6.803 12.408 ;
     RECT  6.725 74.352 6.803 75.384 ;
     RECT  6.113 11.376 6.829 11.4 ;
     RECT  4.588 46.752 6.829 46.776 ;
     RECT  5.996 29.952 6.956 29.976 ;
     RECT  6.956 29.616 6.973 29.976 ;
     RECT  6.757 67.248 7.045 69.624 ;
     RECT  7.009 92.688 7.081 92.712 ;
     RECT  6.437 71.664 7.093 71.832 ;
     RECT  6.505 33.072 7.1 33.096 ;
     RECT  5.501 31.104 7.141 31.128 ;
     RECT  6.949 89.52 7.225 89.784 ;
     RECT  6.217 22.512 7.297 22.68 ;
     RECT  7.081 92.496 7.297 92.712 ;
     RECT  6.577 60.816 7.369 60.936 ;
     RECT  6.515 62.448 7.369 63.288 ;
     RECT  6.113 82.656 7.429 84.888 ;
     RECT  6.853 86.16 7.429 86.184 ;
     RECT  7.1 32.928 7.436 33.096 ;
     RECT  6.733 88.224 7.549 88.248 ;
     RECT  7.225 89.52 7.549 90.6 ;
     RECT  7.369 60.816 7.573 63.288 ;
     RECT  6.757 65.568 7.573 66.168 ;
     RECT  7.045 67.248 7.573 69.816 ;
     RECT  6.515 64.368 7.621 64.392 ;
     RECT  7.573 65.568 7.621 69.816 ;
     RECT  7.093 71.664 7.621 71.88 ;
     RECT  6.239 36.48 7.669 36.504 ;
     RECT  7.549 88.224 7.669 90.6 ;
     RECT  5.653 50.256 7.693 50.28 ;
     RECT  6.853 9.36 7.808 9.384 ;
     RECT  6.829 11.376 7.808 12.024 ;
     RECT  5.069 15.84 7.808 15.912 ;
     RECT  6.793 17.52 7.808 17.976 ;
     RECT  6.076 21.408 7.808 21.432 ;
     RECT  7.297 22.512 7.808 22.776 ;
     RECT  6.041 24.384 7.808 24.408 ;
     RECT  6.757 26.16 7.808 26.184 ;
     RECT  5.836 27.792 7.808 27.912 ;
     RECT  6.973 29.616 7.808 30.072 ;
     RECT  7.141 31.104 7.808 31.896 ;
     RECT  7.436 32.928 7.808 33.48 ;
     RECT  7.1 35.088 7.808 35.112 ;
     RECT  7.669 36.48 7.808 36.888 ;
     RECT  6.073 45.024 7.808 45.048 ;
     RECT  6.829 46.752 7.808 46.872 ;
     RECT  5.699 48.288 7.808 48.312 ;
     RECT  7.693 50.256 7.808 50.376 ;
     RECT  6.505 51.792 7.808 55.224 ;
     RECT  6.937 56.688 7.808 56.712 ;
     RECT  6.973 57.696 7.808 57.72 ;
     RECT  6.725 58.704 7.808 58.728 ;
     RECT  7.573 60.72 7.808 63.288 ;
     RECT  7.621 64.368 7.808 69.816 ;
     RECT  7.621 71.664 7.808 71.928 ;
     RECT  6.803 74.352 7.808 74.616 ;
     RECT  6.725 76.368 7.808 76.392 ;
     RECT  6.185 77.664 7.808 78.12 ;
     RECT  6.689 79.248 7.808 79.752 ;
     RECT  7.009 81.456 7.808 81.48 ;
     RECT  7.429 82.656 7.808 86.184 ;
     RECT  7.477 87.216 7.808 87.24 ;
     RECT  7.669 88.224 7.808 91.368 ;
     RECT  7.297 92.448 7.808 92.712 ;
     RECT  6.685 96.912 7.808 96.936 ;
     RECT  6.973 98.256 7.808 98.28 ;
     RECT  5.713 100.272 7.808 100.296 ;
     RECT  7.117 102.048 7.808 102.072 ;
     RECT  4.931 119.472 7.808 119.496 ;
     RECT  7.808 2.148 7.912 127.452 ;
     RECT  7.912 2.418 8.104 127.182 ;
     RECT  8.104 66.048 8.165 69.48 ;
     RECT  8.104 55.152 8.273 55.32 ;
     RECT  8.104 46.848 8.291 47.496 ;
     RECT  8.104 48.96 8.291 48.984 ;
     RECT  8.104 51.648 8.291 52.488 ;
     RECT  8.104 62.448 8.291 64.104 ;
     RECT  8.104 17.952 8.339 17.976 ;
     RECT  8.291 62.448 8.339 63.288 ;
     RECT  8.104 50.16 8.381 50.376 ;
     RECT  8.104 59.664 8.381 61.032 ;
     RECT  8.165 66.864 8.381 69.48 ;
     RECT  8.104 56.4 8.387 56.424 ;
     RECT  8.104 21.408 8.417 21.432 ;
     RECT  8.104 71.664 8.417 73.032 ;
     RECT  8.104 74.592 8.435 75.432 ;
     RECT  8.381 66.864 8.453 67.368 ;
     RECT  8.435 74.592 8.525 75.24 ;
     RECT  8.525 74.832 8.597 75.24 ;
     RECT  8.291 51.648 8.627 52.2 ;
     RECT  8.104 77.904 8.627 78.12 ;
     RECT  8.597 75.216 8.741 75.24 ;
     RECT  8.104 83.472 8.771 86.184 ;
     RECT  8.104 88.128 8.849 88.92 ;
     RECT  8.417 72.432 8.921 73.032 ;
     RECT  8.104 76.464 8.957 76.776 ;
     RECT  8.104 27.888 8.963 27.912 ;
     RECT  8.381 68.352 8.963 69.48 ;
     RECT  8.453 66.864 8.965 67.272 ;
     RECT  8.381 59.76 8.993 61.032 ;
     RECT  8.381 50.16 9.065 50.184 ;
     RECT  8.957 76.752 9.089 76.776 ;
     RECT  8.627 77.904 9.089 78.024 ;
     RECT  9.089 76.752 9.101 78.024 ;
     RECT  8.104 33.024 9.107 33.048 ;
     RECT  8.965 66.864 9.133 66.888 ;
     RECT  8.104 70.656 9.133 70.68 ;
     RECT  8.771 83.472 9.137 86.04 ;
     RECT  8.849 88.128 9.137 88.152 ;
     RECT  8.104 30.048 9.155 30.072 ;
     RECT  9.101 77.52 9.173 78.024 ;
     RECT  8.104 22.512 9.203 22.776 ;
     RECT  9.137 83.472 9.209 84.888 ;
     RECT  9.133 70.128 9.217 70.68 ;
     RECT  9.209 83.472 9.241 84.6 ;
     RECT  8.921 72.528 9.277 73.032 ;
     RECT  8.104 31.104 9.299 31.848 ;
     RECT  8.104 81.936 9.317 81.96 ;
     RECT  9.241 83.232 9.325 84.6 ;
     RECT  9.133 66.672 9.349 66.888 ;
     RECT  9.277 72.528 9.389 73.368 ;
     RECT  8.291 46.848 9.395 46.872 ;
     RECT  8.104 79.728 9.421 79.848 ;
     RECT  9.389 72.528 9.436 72.552 ;
     RECT  9.349 66.096 9.461 66.888 ;
     RECT  9.299 31.824 9.491 31.848 ;
     RECT  8.273 55.296 9.497 55.32 ;
     RECT  9.421 79.248 9.505 79.848 ;
     RECT  9.505 79.296 9.569 79.848 ;
     RECT  9.173 77.904 9.587 78.024 ;
     RECT  9.569 79.296 9.613 79.8 ;
     RECT  9.457 73.776 9.673 73.8 ;
     RECT  9.349 22.224 9.731 22.248 ;
     RECT  9.217 70.656 9.781 70.68 ;
     RECT  8.963 68.352 9.997 68.664 ;
     RECT  9.137 86.016 10.033 86.04 ;
     RECT  9.673 73.776 10.069 74.136 ;
     RECT  9.587 78 10.181 78.024 ;
     RECT  9.781 70.656 10.217 71.112 ;
     RECT  8.993 59.76 10.22 60.408 ;
     RECT  9.493 89.424 10.261 89.448 ;
     RECT  10.033 86.016 10.289 86.616 ;
     RECT  10.22 59.424 10.307 60.408 ;
     RECT  10.069 73.776 10.541 74.76 ;
     RECT  8.104 41.568 10.577 41.592 ;
     RECT  9.325 83.472 10.681 84.6 ;
     RECT  10.261 57.552 10.757 57.576 ;
     RECT  10.217 70.656 10.757 70.68 ;
     RECT  9.205 91.2 10.757 91.224 ;
     RECT  10.609 82.08 10.789 82.104 ;
     RECT  10.681 83.424 10.789 84.6 ;
     RECT  10.261 89.424 10.835 90.024 ;
     RECT  8.339 62.448 10.837 62.472 ;
     RECT  10.717 75.648 10.837 75.672 ;
     RECT  10.289 86.592 10.865 86.616 ;
     RECT  10.837 75.648 10.883 76.968 ;
     RECT  10.837 61.584 10.901 62.472 ;
     RECT  10.901 61.584 10.924 61.608 ;
     RECT  10.789 82.08 11.041 84.6 ;
     RECT  11.041 81.6 11.081 84.6 ;
     RECT  9.461 66.144 11.084 66.888 ;
     RECT  9.997 68.352 11.084 69.288 ;
     RECT  11.084 66.144 11.125 69.288 ;
     RECT  11.125 66.144 11.171 69.576 ;
     RECT  8.104 40.416 11.189 40.44 ;
     RECT  9.613 79.728 11.221 79.8 ;
     RECT  11.081 82.8 11.221 84.6 ;
     RECT  11.171 68.352 11.261 69.576 ;
     RECT  11.185 55.296 11.269 55.32 ;
     RECT  11.185 87.792 11.269 87.816 ;
     RECT  10.249 71.904 11.317 71.928 ;
     RECT  10.541 73.776 11.363 73.8 ;
     RECT  11.221 78.96 11.365 79.8 ;
     RECT  10.883 76.176 11.369 76.968 ;
     RECT  11.317 71.904 11.404 72.072 ;
     RECT  11.171 66.144 11.411 66.888 ;
     RECT  11.081 81.6 11.411 81.624 ;
     RECT  11.221 82.8 11.411 84.936 ;
     RECT  11.365 86.064 11.449 86.088 ;
     RECT  11.564 56.352 11.605 56.376 ;
     RECT  11.605 56.352 11.651 57.144 ;
     RECT  11.411 82.8 11.801 84.36 ;
     RECT  10.835 90 11.945 90.024 ;
     RECT  11.473 77.472 12.035 77.496 ;
     RECT  11.404 71.904 12.125 71.928 ;
     RECT  11.149 63.216 12.284 63.24 ;
     RECT  11.411 66.864 12.661 66.888 ;
     RECT  11.261 68.352 12.661 68.664 ;
     RECT  11.651 57.12 12.697 57.144 ;
     RECT  8.627 52.176 12.709 52.2 ;
     RECT  8.104 36.768 13.208 36.792 ;
     RECT  11.833 40.368 13.208 40.392 ;
     RECT  11.221 41.376 13.208 41.4 ;
     RECT  12.949 42.528 13.208 42.552 ;
     RECT  11.221 46.032 13.208 46.056 ;
     RECT  12.325 47.664 13.208 47.688 ;
     RECT  12.709 52.176 13.208 52.296 ;
     RECT  12.913 55.296 13.208 55.32 ;
     RECT  12.697 57.024 13.208 57.144 ;
     RECT  10.307 60.384 13.208 60.408 ;
     RECT  12.284 62.64 13.208 63.24 ;
     RECT  11.365 64.848 13.208 64.872 ;
     RECT  12.661 66.864 13.208 68.664 ;
     RECT  12.908 73.968 13.208 73.992 ;
     RECT  11.369 76.176 13.208 76.2 ;
     RECT  11.365 78.96 13.208 80.52 ;
     RECT  11.801 83.568 13.208 84.36 ;
     RECT  12.949 85.392 13.208 85.416 ;
     RECT  12.445 86.592 13.208 86.616 ;
     RECT  13.208 2.148 13.312 127.452 ;
     RECT  13.312 2.418 13.504 127.182 ;
     RECT  13.504 42.432 13.601 42.552 ;
     RECT  13.504 76.32 13.667 76.392 ;
     RECT  13.504 78.048 13.667 79.752 ;
     RECT  13.504 57.12 13.673 57.144 ;
     RECT  13.504 68.112 13.781 68.664 ;
     RECT  13.667 76.368 14.003 76.392 ;
     RECT  13.667 78.048 14.133 78.072 ;
     RECT  13.504 40.368 14.785 40.392 ;
     RECT  13.504 83.568 14.789 83.592 ;
     RECT  14.785 40.272 14.825 40.392 ;
     RECT  16.645 82.128 16.657 82.152 ;
     RECT  16.657 82.128 16.732 82.632 ;
     RECT  16.732 82.608 16.741 82.632 ;
     RECT  13.504 45.936 17.057 45.96 ;
     RECT  13.504 85.392 18.313 85.416 ;
     RECT  13.504 36.768 18.608 36.792 ;
     RECT  14.825 40.272 18.608 40.296 ;
     RECT  13.504 41.376 18.608 41.4 ;
     RECT  13.601 42.432 18.608 42.456 ;
     RECT  17.629 45.984 18.608 46.008 ;
     RECT  13.504 47.568 18.608 47.592 ;
     RECT  13.504 52.176 18.608 52.44 ;
     RECT  13.504 66.864 18.608 66.888 ;
     RECT  13.781 68.64 18.608 68.664 ;
     RECT  13.667 79.152 18.608 79.752 ;
     RECT  18.313 85.392 18.608 85.464 ;
     RECT  16.693 92.688 18.608 92.712 ;
     RECT  18.608 2.148 18.712 127.452 ;
     RECT  18.712 2.418 18.904 127.182 ;
     RECT  18.904 36.768 24.008 36.792 ;
     RECT  18.904 40.272 24.008 40.296 ;
     RECT  18.904 41.376 24.008 41.4 ;
     RECT  18.904 42.432 24.008 42.456 ;
     RECT  18.904 45.984 24.008 46.008 ;
     RECT  18.904 47.568 24.008 47.592 ;
     RECT  18.904 52.176 24.008 52.44 ;
     RECT  18.904 66.864 24.008 66.888 ;
     RECT  18.904 68.64 24.008 68.664 ;
     RECT  18.904 79.152 24.008 79.752 ;
     RECT  18.904 85.44 24.008 85.464 ;
     RECT  18.904 92.688 24.008 92.712 ;
     RECT  24.008 2.148 24.112 127.452 ;
     RECT  24.112 2.418 24.304 127.182 ;
     RECT  24.304 66.864 24.833 66.888 ;
     RECT  24.304 92.688 27.749 92.712 ;
     RECT  24.304 36.768 29.408 36.792 ;
     RECT  24.304 40.272 29.408 40.296 ;
     RECT  24.304 41.376 29.408 41.4 ;
     RECT  24.304 42.432 29.408 42.456 ;
     RECT  24.304 45.984 29.408 46.008 ;
     RECT  24.304 47.568 29.408 47.592 ;
     RECT  24.304 52.176 29.408 52.44 ;
     RECT  25.477 67.056 29.408 67.08 ;
     RECT  24.304 68.64 29.408 68.664 ;
     RECT  24.304 79.152 29.408 79.752 ;
     RECT  24.304 85.44 29.408 85.464 ;
     RECT  29.408 2.148 29.512 127.452 ;
     RECT  29.512 2.418 29.704 127.182 ;
     RECT  29.704 36.768 34.808 36.792 ;
     RECT  29.704 40.272 34.808 40.296 ;
     RECT  29.704 41.376 34.808 41.4 ;
     RECT  29.704 42.432 34.808 42.456 ;
     RECT  29.704 45.984 34.808 46.008 ;
     RECT  29.704 47.568 34.808 47.592 ;
     RECT  29.704 52.176 34.808 52.44 ;
     RECT  29.704 67.056 34.808 67.08 ;
     RECT  29.704 68.64 34.808 68.664 ;
     RECT  29.704 79.152 34.808 79.752 ;
     RECT  29.704 85.44 34.808 85.464 ;
     RECT  34.808 2.148 34.912 127.452 ;
     RECT  34.912 2.418 35.104 127.182 ;
     RECT  35.104 52.176 35.165 52.44 ;
     RECT  35.104 79.152 40.021 79.272 ;
     RECT  35.104 36.768 40.208 36.792 ;
     RECT  35.104 40.272 40.208 40.296 ;
     RECT  35.104 41.376 40.208 41.4 ;
     RECT  35.104 42.432 40.208 42.456 ;
     RECT  35.104 45.984 40.208 46.008 ;
     RECT  35.104 47.568 40.208 47.592 ;
     RECT  35.165 52.272 40.208 52.44 ;
     RECT  40.021 66 40.208 66.024 ;
     RECT  35.104 67.056 40.208 67.08 ;
     RECT  35.104 68.64 40.208 68.664 ;
     RECT  40.021 79.008 40.208 79.272 ;
     RECT  35.104 85.44 40.208 85.464 ;
     RECT  40.208 2.148 40.312 127.452 ;
     RECT  40.312 2.418 40.504 127.182 ;
     RECT  40.504 36.768 45.608 36.792 ;
     RECT  40.504 40.272 45.608 40.296 ;
     RECT  40.504 41.376 45.608 41.4 ;
     RECT  40.504 42.432 45.608 42.456 ;
     RECT  40.504 45.984 45.608 46.008 ;
     RECT  40.504 47.568 45.608 47.592 ;
     RECT  40.504 52.272 45.608 52.296 ;
     RECT  40.504 66 45.608 66.024 ;
     RECT  40.504 67.056 45.608 67.08 ;
     RECT  40.504 68.64 45.608 68.664 ;
     RECT  40.504 79.488 45.608 79.512 ;
     RECT  40.504 85.44 45.608 85.464 ;
     RECT  45.608 2.148 45.712 127.452 ;
     RECT  45.712 2.418 45.904 127.182 ;
     RECT  45.904 36.768 51.008 36.792 ;
     RECT  45.904 40.272 51.008 40.296 ;
     RECT  45.904 41.376 51.008 41.4 ;
     RECT  45.904 42.432 51.008 42.456 ;
     RECT  45.904 45.984 51.008 46.008 ;
     RECT  45.904 47.568 51.008 47.592 ;
     RECT  45.904 52.272 51.008 52.296 ;
     RECT  45.904 66 51.008 66.024 ;
     RECT  45.904 67.056 51.008 67.08 ;
     RECT  45.904 68.64 51.008 68.664 ;
     RECT  45.904 79.488 51.008 79.512 ;
     RECT  45.904 85.44 51.008 85.464 ;
     RECT  51.008 2.148 51.112 127.452 ;
     RECT  51.112 2.418 51.304 127.182 ;
     RECT  51.304 66.048 51.635 66.072 ;
     RECT  51.304 125.424 52.019 125.448 ;
     RECT  51.304 124.272 52.06 124.44 ;
     RECT  51.304 127.056 52.085 127.08 ;
     RECT  52.06 124.272 52.093 124.296 ;
     RECT  51.304 36.768 56.408 36.792 ;
     RECT  51.304 40.272 56.408 40.296 ;
     RECT  51.304 41.376 56.408 41.4 ;
     RECT  51.304 42.432 56.408 42.456 ;
     RECT  51.304 45.984 56.408 46.008 ;
     RECT  51.304 47.568 56.408 47.592 ;
     RECT  51.304 52.272 56.408 52.296 ;
     RECT  51.304 67.056 56.408 67.08 ;
     RECT  51.304 68.64 56.408 68.664 ;
     RECT  51.304 79.488 56.408 79.512 ;
     RECT  51.304 85.44 56.408 85.464 ;
     RECT  51.304 108.336 56.408 108.36 ;
     RECT  56.408 2.148 56.512 127.452 ;
     RECT  56.512 2.418 56.704 127.182 ;
     RECT  56.704 36.768 61.808 36.792 ;
     RECT  56.704 40.272 61.808 40.296 ;
     RECT  56.704 41.376 61.808 41.4 ;
     RECT  56.704 42.432 61.808 42.456 ;
     RECT  56.704 45.984 61.808 46.008 ;
     RECT  56.704 47.568 61.808 47.592 ;
     RECT  56.704 52.272 61.808 52.296 ;
     RECT  56.704 67.056 61.808 67.08 ;
     RECT  56.704 68.64 61.808 68.664 ;
     RECT  56.704 79.488 61.808 79.512 ;
     RECT  56.704 85.44 61.808 85.464 ;
     RECT  56.704 108.336 61.808 108.36 ;
     RECT  61.808 2.148 61.912 127.452 ;
     RECT  61.912 2.418 62.104 127.182 ;
     RECT  62.104 36.768 67.208 36.792 ;
     RECT  62.104 40.272 67.208 40.296 ;
     RECT  62.104 41.376 67.208 41.4 ;
     RECT  62.104 42.432 67.208 42.456 ;
     RECT  62.104 45.984 67.208 46.008 ;
     RECT  62.104 47.568 67.208 47.592 ;
     RECT  62.104 52.272 67.208 52.296 ;
     RECT  62.104 67.056 67.208 67.08 ;
     RECT  62.104 68.64 67.208 68.664 ;
     RECT  62.104 79.488 67.208 79.512 ;
     RECT  62.104 85.44 67.208 85.464 ;
     RECT  62.104 108.336 67.208 108.36 ;
     RECT  67.208 2.148 67.312 127.452 ;
     RECT  67.312 2.418 67.504 127.182 ;
     RECT  67.504 36.768 72.608 36.792 ;
     RECT  67.504 40.272 72.608 40.296 ;
     RECT  67.504 41.376 72.608 41.4 ;
     RECT  67.504 42.432 72.608 42.456 ;
     RECT  67.504 45.984 72.608 46.008 ;
     RECT  67.504 47.568 72.608 47.592 ;
     RECT  67.504 52.272 72.608 52.296 ;
     RECT  67.504 67.056 72.608 67.08 ;
     RECT  67.504 68.64 72.608 68.664 ;
     RECT  67.504 79.488 72.608 79.512 ;
     RECT  67.504 85.44 72.608 85.464 ;
     RECT  67.504 108.336 72.608 108.36 ;
     RECT  72.608 2.148 72.712 127.452 ;
     RECT  72.712 2.418 72.904 127.182 ;
     RECT  72.904 79.488 73.571 79.752 ;
     RECT  72.904 108.288 73.693 108.36 ;
     RECT  72.904 36.768 78.008 36.792 ;
     RECT  72.904 40.272 78.008 40.296 ;
     RECT  72.904 41.376 78.008 41.4 ;
     RECT  72.904 42.432 78.008 42.456 ;
     RECT  72.904 45.984 78.008 46.008 ;
     RECT  72.904 47.568 78.008 47.592 ;
     RECT  72.904 52.272 78.008 52.296 ;
     RECT  72.904 67.056 78.008 67.08 ;
     RECT  72.904 68.64 78.008 68.664 ;
     RECT  73.571 79.728 78.008 79.752 ;
     RECT  72.904 85.44 78.008 85.464 ;
     RECT  73.693 108.336 78.008 108.36 ;
     RECT  78.008 2.148 78.112 127.452 ;
     RECT  78.112 2.418 78.304 127.182 ;
     RECT  78.304 36.768 83.408 36.792 ;
     RECT  78.304 40.272 83.408 40.296 ;
     RECT  78.304 41.376 83.408 41.4 ;
     RECT  78.304 42.432 83.408 42.456 ;
     RECT  78.304 45.984 83.408 46.008 ;
     RECT  78.304 47.568 83.408 47.592 ;
     RECT  78.304 52.272 83.408 52.296 ;
     RECT  78.304 67.056 83.408 67.08 ;
     RECT  78.304 68.64 83.408 68.664 ;
     RECT  78.304 79.728 83.408 79.752 ;
     RECT  78.304 85.44 83.408 85.464 ;
     RECT  78.304 108.336 83.408 108.36 ;
     RECT  83.408 2.148 83.512 127.452 ;
     RECT  83.512 2.418 83.704 127.182 ;
     RECT  83.704 36.768 88.808 36.792 ;
     RECT  83.704 40.272 88.808 40.296 ;
     RECT  83.704 41.376 88.808 41.4 ;
     RECT  83.704 42.432 88.808 42.456 ;
     RECT  83.704 45.984 88.808 46.008 ;
     RECT  83.704 47.568 88.808 47.592 ;
     RECT  83.704 52.272 88.808 52.296 ;
     RECT  83.704 67.056 88.808 67.08 ;
     RECT  83.704 68.64 88.808 68.664 ;
     RECT  83.704 79.728 88.808 79.752 ;
     RECT  83.704 85.44 88.808 85.464 ;
     RECT  83.704 108.336 88.808 108.36 ;
     RECT  88.808 2.148 88.912 127.452 ;
     RECT  88.912 2.418 89.104 127.182 ;
     RECT  89.104 40.272 90.637 40.296 ;
     RECT  90.637 40.128 90.677 40.296 ;
     RECT  89.104 36.768 94.208 36.792 ;
     RECT  90.677 40.128 94.208 40.152 ;
     RECT  89.104 41.376 94.208 41.4 ;
     RECT  89.104 42.432 94.208 42.456 ;
     RECT  89.104 45.984 94.208 46.008 ;
     RECT  89.104 47.568 94.208 47.592 ;
     RECT  89.104 52.272 94.208 52.296 ;
     RECT  89.104 67.056 94.208 67.08 ;
     RECT  89.104 68.64 94.208 68.664 ;
     RECT  89.104 79.728 94.208 79.752 ;
     RECT  89.104 85.44 94.208 85.464 ;
     RECT  89.104 108.336 94.208 108.36 ;
     RECT  94.208 2.148 94.312 127.452 ;
     RECT  94.312 2.418 94.504 127.182 ;
     RECT  94.504 40.128 94.673 41.4 ;
     RECT  94.504 89.952 94.979 91.464 ;
     RECT  94.504 57.456 95.315 58.728 ;
     RECT  95.315 57.456 95.357 58.152 ;
     RECT  94.673 40.128 95.429 40.44 ;
     RECT  94.504 92.688 95.459 92.712 ;
     RECT  94.504 108.336 95.459 108.36 ;
     RECT  94.504 55.392 95.497 55.416 ;
     RECT  95.497 55.296 95.537 55.416 ;
     RECT  94.504 67.056 95.537 69 ;
     RECT  94.504 64.368 95.555 64.392 ;
     RECT  95.537 67.056 95.555 68.664 ;
     RECT  95.497 86.592 95.581 86.616 ;
     RECT  94.504 52.272 95.651 52.44 ;
     RECT  94.504 76.368 95.653 76.392 ;
     RECT  94.979 90.624 95.681 91.464 ;
     RECT  95.605 53.76 95.692 53.784 ;
     RECT  95.653 76.368 95.699 78.072 ;
     RECT  94.504 79.728 95.713 79.752 ;
     RECT  95.699 77.328 95.74 78.072 ;
     RECT  95.681 91.44 95.753 91.464 ;
     RECT  94.504 47.28 95.989 47.592 ;
     RECT  95.497 74.112 95.989 74.136 ;
     RECT  95.989 72.864 96.035 74.136 ;
     RECT  96.035 72.864 96.076 73.512 ;
     RECT  95.989 47.184 96.077 48.12 ;
     RECT  95.509 65.52 96.509 65.544 ;
     RECT  95.555 68.64 96.577 68.664 ;
     RECT  95.821 84.384 96.613 84.408 ;
     RECT  96.613 84.336 96.707 84.408 ;
     RECT  94.504 81.072 96.716 81.096 ;
     RECT  94.504 44.448 96.757 44.472 ;
     RECT  95.651 52.272 96.757 52.296 ;
     RECT  96.661 82.8 96.757 82.824 ;
     RECT  96.577 68.64 96.761 68.952 ;
     RECT  96.757 44.304 96.797 44.472 ;
     RECT  96.716 80.928 96.803 81.096 ;
     RECT  96.757 51.312 96.841 52.296 ;
     RECT  95.537 55.296 96.86 55.32 ;
     RECT  96.86 55.296 96.869 55.848 ;
     RECT  96.757 82.56 96.869 82.824 ;
     RECT  96.841 52.272 96.901 52.296 ;
     RECT  96.037 62.64 96.901 62.664 ;
     RECT  95.713 79.68 96.941 79.752 ;
     RECT  96.901 52.272 96.947 52.44 ;
     RECT  96.869 55.824 96.947 55.848 ;
     RECT  95.74 77.328 97.085 77.352 ;
     RECT  96.577 78.624 97.085 78.648 ;
     RECT  95.429 40.416 97.117 40.44 ;
     RECT  96.361 60.96 97.148 60.984 ;
     RECT  94.504 45.984 97.189 46.008 ;
     RECT  97.148 60.96 97.235 61.608 ;
     RECT  97.117 40.416 97.244 40.776 ;
     RECT  97.244 39.888 97.331 40.776 ;
     RECT  96.947 52.416 97.331 52.44 ;
     RECT  96.901 75.84 97.429 75.864 ;
     RECT  96.037 71.04 97.441 71.064 ;
     RECT  94.504 36.768 97.475 37.656 ;
     RECT  97.429 75.024 97.475 75.864 ;
     RECT  97.441 70.704 97.481 71.064 ;
     RECT  96.707 84.336 97.525 84.36 ;
     RECT  94.504 85.44 97.525 85.464 ;
     RECT  97.525 85.344 97.549 85.464 ;
     RECT  97.525 83.76 97.571 84.36 ;
     RECT  97.189 45.936 97.58 46.008 ;
     RECT  97.58 45.936 97.585 46.2 ;
     RECT  96.077 47.184 97.585 47.592 ;
     RECT  97.475 36.768 97.589 37.032 ;
     RECT  97.549 85.344 97.612 85.512 ;
     RECT  97.585 45.936 97.621 47.592 ;
     RECT  96.761 68.928 97.621 68.952 ;
     RECT  94.504 88.32 97.657 88.344 ;
     RECT  97.657 88.32 97.658 88.392 ;
     RECT  97.621 68.928 97.661 69.72 ;
     RECT  97.621 45.552 97.667 47.592 ;
     RECT  96.941 79.68 97.715 79.704 ;
     RECT  95.555 67.056 97.729 67.08 ;
     RECT  97.612 85.44 97.733 85.512 ;
     RECT  97.657 71.76 97.741 71.832 ;
     RECT  96.901 62.64 97.765 62.76 ;
     RECT  96.757 65.28 97.801 65.304 ;
     RECT  97.801 65.136 97.841 65.304 ;
     RECT  94.504 42.432 98.017 42.456 ;
     RECT  96.797 44.304 98.017 44.328 ;
     RECT  97.837 59.952 98.053 59.976 ;
     RECT  96.076 73.488 98.053 73.512 ;
     RECT  97.475 75.024 98.053 75.048 ;
     RECT  98.017 42.432 98.06 44.328 ;
     RECT  97.667 45.552 98.06 45.576 ;
     RECT  97.429 38.736 98.093 38.76 ;
     RECT  97.235 60.96 98.093 60.984 ;
     RECT  97.481 70.704 98.093 70.728 ;
     RECT  98.053 72.96 98.093 73.512 ;
     RECT  98.053 74.784 98.093 75.048 ;
     RECT  98.053 59.616 98.099 59.976 ;
     RECT  98.06 42.432 98.129 45.576 ;
     RECT  97.667 47.04 98.129 47.592 ;
     RECT  98.129 42.432 98.147 44.904 ;
     RECT  97.571 83.76 98.237 83.784 ;
     RECT  95.357 58.128 98.245 58.152 ;
     RECT  98.053 56.4 98.291 56.424 ;
     RECT  98.245 57.552 98.291 58.152 ;
     RECT  97.729 66.96 98.293 67.08 ;
     RECT  97.765 62.64 98.309 63.24 ;
     RECT  98.291 57.552 98.332 57.576 ;
     RECT  98.293 66.672 98.339 67.8 ;
     RECT  98.339 66.672 98.453 66.696 ;
     RECT  95.569 49.584 98.531 49.608 ;
     RECT  98.339 67.776 98.533 67.8 ;
     RECT  98.477 50.736 98.561 50.76 ;
     RECT  98.093 72.96 98.629 72.984 ;
     RECT  98.093 74.784 98.629 74.808 ;
     RECT  98.053 90.72 98.629 90.744 ;
     RECT  97.841 65.136 98.828 65.16 ;
     RECT  97.333 78.384 98.845 78.408 ;
     RECT  98.053 51.792 98.876 51.816 ;
     RECT  97.621 52.944 98.876 52.968 ;
     RECT  98.147 42.432 98.917 43.368 ;
     RECT  98.876 51.792 98.917 52.968 ;
     RECT  98.629 87.312 98.953 87.336 ;
     RECT  97.589 37.008 99.608 37.032 ;
     RECT  97.331 40.752 99.608 40.776 ;
     RECT  98.917 42.192 99.608 43.368 ;
     RECT  98.129 47.04 99.608 47.064 ;
     RECT  98.917 51.792 99.608 53.592 ;
     RECT  98.099 59.616 99.608 59.64 ;
     RECT  98.309 63.216 99.608 63.24 ;
     RECT  98.828 64.752 99.608 65.16 ;
     RECT  98.869 66.144 99.608 66.168 ;
     RECT  98.533 67.776 99.608 68.376 ;
     RECT  97.661 69.696 99.608 69.72 ;
     RECT  97.741 71.76 99.608 71.784 ;
     RECT  98.629 72.768 99.608 72.984 ;
     RECT  98.629 74.544 99.608 74.808 ;
     RECT  98.845 78.384 99.608 79.272 ;
     RECT  98.629 81.456 99.608 81.48 ;
     RECT  98.629 83.232 99.608 83.256 ;
     RECT  97.733 85.488 99.608 85.512 ;
     RECT  98.953 87.168 99.608 87.336 ;
     RECT  97.658 88.368 99.608 88.392 ;
     RECT  98.629 90.384 99.608 90.744 ;
     RECT  99.608 2.148 99.712 127.452 ;
     RECT  99.712 2.418 99.904 127.182 ;
     RECT  99.904 88.32 101.189 88.344 ;
     RECT  101.509 53.52 102.013 53.544 ;
     RECT  101.365 38.832 102.481 38.856 ;
     RECT  102.013 48.336 102.517 48.36 ;
     RECT  102.013 59.136 102.517 59.16 ;
     RECT  102.481 38.4 102.553 38.856 ;
     RECT  102.013 40.992 102.553 41.016 ;
     RECT  102.013 43.584 102.553 43.608 ;
     RECT  101.977 44.88 102.553 44.904 ;
     RECT  102.517 48.336 102.553 49.224 ;
     RECT  102.013 52.656 102.553 53.544 ;
     RECT  102.517 56.976 102.553 57 ;
     RECT  102.517 59.136 102.553 60.024 ;
     RECT  102.517 61.296 102.553 61.32 ;
     RECT  102.013 64.752 102.553 64.776 ;
     RECT  102.013 66.912 102.553 66.936 ;
     RECT  101.977 69.072 102.553 69.096 ;
     RECT  102.013 70.368 102.553 70.392 ;
     RECT  102.517 73.392 102.553 73.416 ;
     RECT  102.517 75.12 102.553 75.144 ;
     RECT  102.517 77.712 102.553 77.736 ;
     RECT  102.013 88.08 102.553 88.104 ;
     RECT  102.013 89.376 102.553 89.4 ;
     RECT  102.013 91.536 102.553 92.424 ;
     RECT  101.041 37.104 102.589 37.128 ;
     RECT  102.553 38.4 102.589 92.856 ;
     RECT  102.589 37.104 102.625 92.856 ;
     RECT  102.625 36.672 103.644 92.856 ;
    LAYER M5 ;
     RECT  2.4 2.137 2.52 2.151 ;
     RECT  7.8 2.137 7.92 2.151 ;
     RECT  13.2 2.137 13.32 2.151 ;
     RECT  18.6 2.137 18.72 2.151 ;
     RECT  24 2.137 24.12 2.151 ;
     RECT  29.4 2.137 29.52 2.151 ;
     RECT  34.8 2.137 34.92 2.151 ;
     RECT  40.2 2.137 40.32 2.151 ;
     RECT  45.6 2.137 45.72 2.151 ;
     RECT  51 2.137 51.12 2.151 ;
     RECT  56.4 2.137 56.52 2.151 ;
     RECT  61.8 2.137 61.92 2.151 ;
     RECT  67.2 2.137 67.32 2.151 ;
     RECT  72.6 2.137 72.72 2.151 ;
     RECT  78 2.137 78.12 2.151 ;
     RECT  83.4 2.137 83.52 2.151 ;
     RECT  88.8 2.137 88.92 2.151 ;
     RECT  94.2 2.137 94.32 2.151 ;
     RECT  99.6 2.137 99.72 2.151 ;
     RECT  7.8 2.151 8.112 9.349 ;
     RECT  5.088 8.821 5.112 9.683 ;
     RECT  6.864 9.349 8.112 12.035 ;
     RECT  4.8 11.365 4.824 12.517 ;
     RECT  2.4 2.151 2.712 12.901 ;
     RECT  2.4 12.901 3.288 13.045 ;
     RECT  6.768 12.373 6.792 13.573 ;
     RECT  2.4 13.045 3.816 14.291 ;
     RECT  4.8 12.517 5.352 14.387 ;
     RECT  3.792 14.291 3.816 15.349 ;
     RECT  4.8 14.387 4.824 15.349 ;
     RECT  6.336 13.573 6.792 15.877 ;
     RECT  7.8 12.035 8.112 15.877 ;
     RECT  6.336 15.877 8.112 17.941 ;
     RECT  2.4 14.291 2.712 18.181 ;
     RECT  3.792 15.349 4.824 18.181 ;
     RECT  2.4 18.181 4.824 18.565 ;
     RECT  2.4 18.565 5.352 20.197 ;
     RECT  6.336 17.941 8.328 20.197 ;
     RECT  2.4 20.197 8.328 21.443 ;
     RECT  3.792 21.443 8.328 22.501 ;
     RECT  3.792 22.501 8.424 22.741 ;
     RECT  9.696 22.213 9.72 22.741 ;
     RECT  2.4 21.443 2.712 23.317 ;
     RECT  3.792 22.741 9.72 23.317 ;
     RECT  2.4 23.317 9.72 25.043 ;
     RECT  3.792 25.043 9.72 26.725 ;
     RECT  2.4 25.043 2.712 28.837 ;
     RECT  3.696 26.725 9.72 28.837 ;
     RECT  97.44 37.621 97.464 38.771 ;
     RECT  99.6 2.151 99.912 40.741 ;
     RECT  98.928 40.741 99.912 42.227 ;
     RECT  13.2 2.151 13.512 42.517 ;
     RECT  97.296 39.877 97.32 43.333 ;
     RECT  97.296 43.333 98.136 44.915 ;
     RECT  97.296 44.915 97.656 46.211 ;
     RECT  12.96 42.517 13.512 47.653 ;
     RECT  96 47.173 96.024 48.131 ;
     RECT  97.296 46.211 97.32 49.573 ;
     RECT  98.496 49.573 98.52 50.771 ;
     RECT  96.768 49.573 97.32 51.347 ;
     RECT  99.6 42.227 99.912 51.781 ;
     RECT  40.2 2.151 40.512 52.405 ;
     RECT  96.912 51.347 97.32 52.451 ;
     RECT  98.928 51.781 99.912 53.603 ;
     RECT  11.232 46.021 11.256 55.331 ;
     RECT  95.616 52.405 95.64 55.331 ;
     RECT  12.336 47.653 13.512 56.341 ;
     RECT  11.616 56.341 13.512 57.155 ;
     RECT  94.2 2.151 94.512 57.445 ;
     RECT  2.4 28.837 9.72 57.541 ;
     RECT  98.256 56.389 98.28 58.163 ;
     RECT  94.2 57.445 95.304 58.739 ;
     RECT  2.4 57.541 10.296 59.459 ;
     RECT  98.064 59.605 98.088 59.987 ;
     RECT  96.912 52.451 96.936 60.949 ;
     RECT  10.848 60.373 10.872 61.619 ;
     RECT  96.912 60.949 97.224 61.619 ;
     RECT  12.336 57.155 13.512 62.675 ;
     RECT  96.912 61.619 96.936 62.771 ;
     RECT  99.6 53.603 99.912 63.205 ;
     RECT  51 2.151 51.312 66.037 ;
     RECT  11.376 63.205 11.4 66.179 ;
     RECT  98.88 63.205 99.912 66.179 ;
     RECT  13.2 62.675 13.512 67.141 ;
     RECT  94.2 58.739 94.512 67.717 ;
     RECT  95.52 64.357 95.544 67.717 ;
     RECT  94.2 67.717 95.544 67.763 ;
     RECT  98.304 66.661 98.328 67.765 ;
     RECT  98.304 67.765 98.616 67.811 ;
     RECT  98.544 67.811 98.616 67.861 ;
     RECT  99.6 66.179 99.912 67.861 ;
     RECT  12.672 67.141 13.512 68.387 ;
     RECT  98.544 67.861 99.912 68.387 ;
     RECT  94.2 67.763 95.208 69.011 ;
     RECT  11.136 67.765 11.16 69.587 ;
     RECT  98.544 68.387 98.568 69.731 ;
     RECT  99.6 68.387 99.912 71.749 ;
     RECT  98.64 71.749 99.912 71.797 ;
     RECT  11.328 72.037 11.352 73.765 ;
     RECT  10.848 73.765 11.352 73.811 ;
     RECT  13.2 68.387 13.512 73.957 ;
     RECT  2.4 59.459 9.72 74.147 ;
     RECT  96 72.853 96.024 74.147 ;
     RECT  97.68 71.797 99.912 74.579 ;
     RECT  98.928 74.579 99.912 74.819 ;
     RECT  97.68 74.579 97.704 75.013 ;
     RECT  97.44 75.013 97.704 75.875 ;
     RECT  12.96 73.957 13.512 76.309 ;
     RECT  12.96 76.309 13.656 76.357 ;
     RECT  10.848 73.811 10.872 76.979 ;
     RECT  12.96 76.357 13.992 77.461 ;
     RECT  2.4 74.147 9.48 77.893 ;
     RECT  12 77.461 13.992 78.037 ;
     RECT  95.664 76.357 95.688 78.083 ;
     RECT  99.6 74.819 99.912 78.373 ;
     RECT  12 78.037 14.088 78.949 ;
     RECT  11.232 78.949 14.088 79.043 ;
     RECT  40.032 52.405 40.512 79.283 ;
     RECT  99.024 78.373 99.912 79.283 ;
     RECT  2.4 77.893 9.576 79.331 ;
     RECT  12.96 79.043 14.088 79.475 ;
     RECT  72.6 2.151 72.912 79.477 ;
     RECT  72.6 79.477 73.56 79.717 ;
     RECT  97.68 75.875 97.704 80.917 ;
     RECT  96.768 80.917 97.704 81.445 ;
     RECT  99.6 79.283 99.912 81.445 ;
     RECT  16.656 79.429 16.68 82.163 ;
     RECT  96.768 81.445 99.912 82.595 ;
     RECT  11.232 79.043 11.4 82.885 ;
     RECT  10.8 82.885 11.4 82.931 ;
     RECT  2.4 79.331 9.288 83.267 ;
     RECT  97.68 82.595 99.912 83.267 ;
     RECT  10.8 82.931 11.256 83.459 ;
     RECT  96.672 82.789 96.696 83.749 ;
     RECT  97.68 83.267 97.704 83.749 ;
     RECT  96.672 83.749 97.704 84.419 ;
     RECT  11.232 83.459 11.256 84.901 ;
     RECT  97.536 84.419 97.704 85.379 ;
     RECT  12.96 79.475 13.512 85.427 ;
     RECT  99.6 83.267 99.912 85.477 ;
     RECT  2.4 83.267 9.096 85.859 ;
     RECT  11.232 84.901 11.4 86.099 ;
     RECT  2.4 85.859 8.76 86.195 ;
     RECT  97.68 85.379 97.704 87.301 ;
     RECT  99.168 85.477 99.912 87.301 ;
     RECT  2.4 86.195 8.112 87.779 ;
     RECT  4.32 87.779 8.112 87.827 ;
     RECT  11.232 86.099 11.256 87.827 ;
     RECT  94.2 69.011 94.512 88.309 ;
     RECT  95.52 86.581 95.544 88.309 ;
     RECT  94.2 88.309 95.544 88.355 ;
     RECT  97.68 87.301 99.912 88.403 ;
     RECT  4.896 87.827 8.112 89.699 ;
     RECT  6.048 89.699 8.112 89.795 ;
     RECT  10.8 89.413 10.824 89.989 ;
     RECT  10.272 89.989 10.824 90.035 ;
     RECT  98.64 88.403 99.912 90.755 ;
     RECT  10.272 90.035 10.296 91.235 ;
     RECT  94.2 88.355 94.968 91.429 ;
     RECT  2.4 87.779 3.24 92.533 ;
     RECT  4.896 89.699 4.92 92.533 ;
     RECT  16.704 82.597 16.728 92.723 ;
     RECT  6.048 89.795 6.072 92.963 ;
     RECT  7.104 89.795 8.112 92.965 ;
     RECT  2.4 92.533 4.92 93.539 ;
     RECT  3.984 93.539 4.92 94.067 ;
     RECT  6.24 92.965 8.112 94.979 ;
     RECT  2.4 93.539 2.808 95.219 ;
     RECT  4.896 94.067 4.92 96.277 ;
     RECT  7.104 94.979 8.112 96.947 ;
     RECT  4.512 96.277 4.92 97.669 ;
     RECT  7.8 96.947 8.112 98.245 ;
     RECT  3.744 97.669 4.92 98.627 ;
     RECT  2.4 95.219 2.712 98.869 ;
     RECT  3.744 98.627 4.632 98.869 ;
     RECT  2.4 98.869 4.632 98.915 ;
     RECT  7.248 98.245 8.112 100.261 ;
     RECT  7.152 100.261 8.112 102.083 ;
     RECT  2.4 98.915 3.432 102.419 ;
     RECT  4.608 98.915 4.632 103.093 ;
     RECT  3.888 103.093 4.632 103.381 ;
     RECT  3.888 103.381 5.208 104.819 ;
     RECT  2.4 102.419 2.712 106.021 ;
     RECT  4.608 104.819 5.208 106.165 ;
     RECT  4.56 106.165 5.208 106.211 ;
     RECT  2.4 106.021 2.856 107.219 ;
     RECT  4.56 106.211 4.632 108.323 ;
     RECT  72.6 79.717 73.656 108.323 ;
     RECT  51 66.037 51.624 108.325 ;
     RECT  94.2 91.429 95.448 108.371 ;
     RECT  2.4 107.219 2.808 108.899 ;
     RECT  4.608 108.323 4.632 110.533 ;
     RECT  2.4 108.899 2.712 111.061 ;
     RECT  4.608 110.533 5.112 111.541 ;
     RECT  2.4 111.061 2.856 112.355 ;
     RECT  6.432 110.485 6.456 112.403 ;
     RECT  4.608 111.541 5.208 114.035 ;
     RECT  4.896 114.035 5.208 114.275 ;
     RECT  2.4 112.355 2.712 114.805 ;
     RECT  2.4 114.805 3.384 116.723 ;
     RECT  6.096 116.005 6.12 117.443 ;
     RECT  4.896 114.275 4.92 120.323 ;
     RECT  51 108.325 52.056 124.307 ;
     RECT  51 124.307 52.008 125.459 ;
     RECT  51 125.459 51.624 127.045 ;
     RECT  2.4 116.723 2.712 127.449 ;
     RECT  7.8 102.083 8.112 127.449 ;
     RECT  13.2 85.427 13.512 127.449 ;
     RECT  18.6 2.151 18.912 127.449 ;
     RECT  24 2.151 24.312 127.449 ;
     RECT  29.4 2.151 29.712 127.449 ;
     RECT  34.8 2.151 35.112 127.449 ;
     RECT  40.2 79.283 40.512 127.449 ;
     RECT  45.6 2.151 45.912 127.449 ;
     RECT  56.4 2.151 56.712 127.449 ;
     RECT  61.8 2.151 62.112 127.449 ;
     RECT  67.2 2.151 67.512 127.449 ;
     RECT  72.6 108.323 72.912 127.449 ;
     RECT  78 2.151 78.312 127.449 ;
     RECT  83.4 2.151 83.712 127.449 ;
     RECT  88.8 2.151 89.112 127.449 ;
     RECT  94.2 108.371 94.512 127.449 ;
     RECT  99.6 90.755 99.912 127.449 ;
     RECT  2.4 127.449 2.52 127.463 ;
     RECT  7.8 127.449 7.92 127.463 ;
     RECT  13.2 127.449 13.32 127.463 ;
     RECT  18.6 127.449 18.72 127.463 ;
     RECT  24 127.449 24.12 127.463 ;
     RECT  29.4 127.449 29.52 127.463 ;
     RECT  34.8 127.449 34.92 127.463 ;
     RECT  40.2 127.449 40.32 127.463 ;
     RECT  45.6 127.449 45.72 127.463 ;
     RECT  51 127.045 52.056 127.463 ;
     RECT  56.4 127.449 56.52 127.463 ;
     RECT  61.8 127.449 61.92 127.463 ;
     RECT  67.2 127.449 67.32 127.463 ;
     RECT  72.6 127.449 72.72 127.463 ;
     RECT  78 127.449 78.12 127.463 ;
     RECT  83.4 127.449 83.52 127.463 ;
     RECT  88.8 127.449 88.92 127.463 ;
     RECT  94.2 127.449 94.32 127.463 ;
     RECT  99.6 127.449 99.72 127.463 ;
     RECT  51.6 127.463 52.056 129.552 ;
     RECT  6.864 12.035 7.8 12.373 ;
     RECT  6.792 12.373 7.8 15.877 ;
     RECT  5.352 12.517 6.768 13.573 ;
     RECT  3.288 12.901 4.8 13.045 ;
     RECT  3.816 13.045 4.8 15.349 ;
     RECT  5.352 13.573 6.336 14.387 ;
     RECT  2.712 14.291 3.792 18.181 ;
     RECT  4.824 14.387 6.336 18.565 ;
     RECT  5.352 18.565 6.336 20.197 ;
     RECT  2.712 21.443 3.792 23.317 ;
     RECT  8.328 22.213 9.696 22.501 ;
     RECT  8.424 22.501 9.696 22.741 ;
     RECT  2.712 25.043 3.792 26.725 ;
     RECT  2.712 26.725 3.696 28.837 ;
     RECT  98.928 42.227 99.6 43.333 ;
     RECT  98.136 43.333 99.6 44.915 ;
     RECT  9.72 46.021 11.232 55.331 ;
     RECT  94.512 47.173 96 48.131 ;
     RECT  96.024 47.173 97.296 48.131 ;
     RECT  11.256 47.653 12.336 55.331 ;
     RECT  96.768 48.131 97.296 49.573 ;
     RECT  97.32 49.573 98.496 50.771 ;
     RECT  98.52 49.573 99.6 50.771 ;
     RECT  98.928 50.771 99.6 51.781 ;
     RECT  96.768 51.347 96.912 52.405 ;
     RECT  94.512 52.405 95.616 55.331 ;
     RECT  95.64 52.405 96.912 55.331 ;
     RECT  11.616 55.331 12.336 56.341 ;
     RECT  96.936 56.389 98.256 58.163 ;
     RECT  98.28 56.389 99.6 58.163 ;
     RECT  96.936 58.163 99.6 59.605 ;
     RECT  9.72 59.459 10.296 60.373 ;
     RECT  96.936 59.605 98.064 59.987 ;
     RECT  98.088 59.605 99.6 59.987 ;
     RECT  96.936 59.987 97.224 60.949 ;
     RECT  9.72 60.373 10.848 61.619 ;
     RECT  10.872 60.373 12.336 61.619 ;
     RECT  94.512 64.357 95.52 67.717 ;
     RECT  98.88 66.179 99.6 66.661 ;
     RECT  98.328 66.661 99.6 67.765 ;
     RECT  9.72 67.765 11.136 69.587 ;
     RECT  11.16 67.765 12.672 68.387 ;
     RECT  98.616 67.765 99.6 67.861 ;
     RECT  98.568 68.387 99.6 69.731 ;
     RECT  94.512 72.853 96 74.147 ;
     RECT  9.72 73.765 10.848 74.147 ;
     RECT  9.48 74.147 10.848 76.979 ;
     RECT  97.704 74.579 98.928 74.819 ;
     RECT  94.512 76.357 95.664 78.083 ;
     RECT  9.48 76.979 9.576 77.893 ;
     RECT  97.704 78.373 99.024 79.283 ;
     RECT  96.768 82.595 97.68 82.789 ;
     RECT  96.696 82.789 97.68 83.749 ;
     RECT  9.288 82.885 10.8 83.267 ;
     RECT  97.704 85.477 99.168 87.301 ;
     RECT  94.512 86.581 95.52 88.309 ;
     RECT  3.24 87.779 4.32 87.827 ;
     RECT  4.92 89.699 6.048 92.963 ;
     RECT  6.072 89.795 7.104 92.963 ;
     RECT  4.92 92.963 7.104 92.965 ;
     RECT  4.92 92.965 6.24 94.979 ;
     RECT  2.808 93.539 3.984 94.067 ;
     RECT  7.248 96.947 7.8 98.245 ;
     RECT  2.712 97.669 3.744 98.869 ;
     RECT  3.432 98.915 4.608 102.419 ;
     RECT  2.712 102.419 4.608 103.093 ;
     RECT  2.712 103.093 3.888 104.819 ;
     RECT  2.712 104.819 2.856 106.021 ;
     RECT  4.56 104.819 4.608 106.165 ;
     RECT  6.456 110.485 7.8 112.403 ;
     RECT  5.112 110.533 6.432 111.541 ;
     RECT  5.208 111.541 6.432 112.403 ;
     RECT  4.608 114.035 4.896 114.805 ;
     RECT  3.384 114.805 4.896 116.723 ;
     RECT  4.92 116.005 6.096 117.443 ;
  END
END dsfd_vm_static_read_q4_p
END LIBRARY
